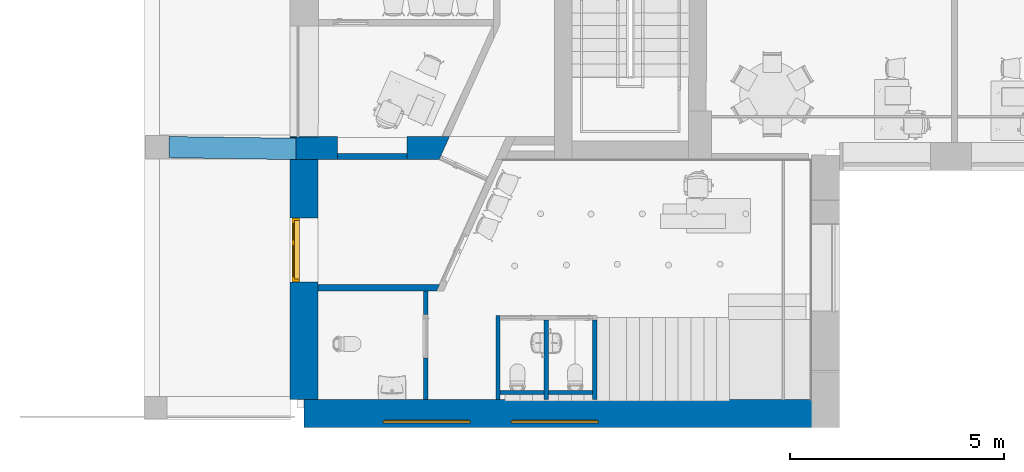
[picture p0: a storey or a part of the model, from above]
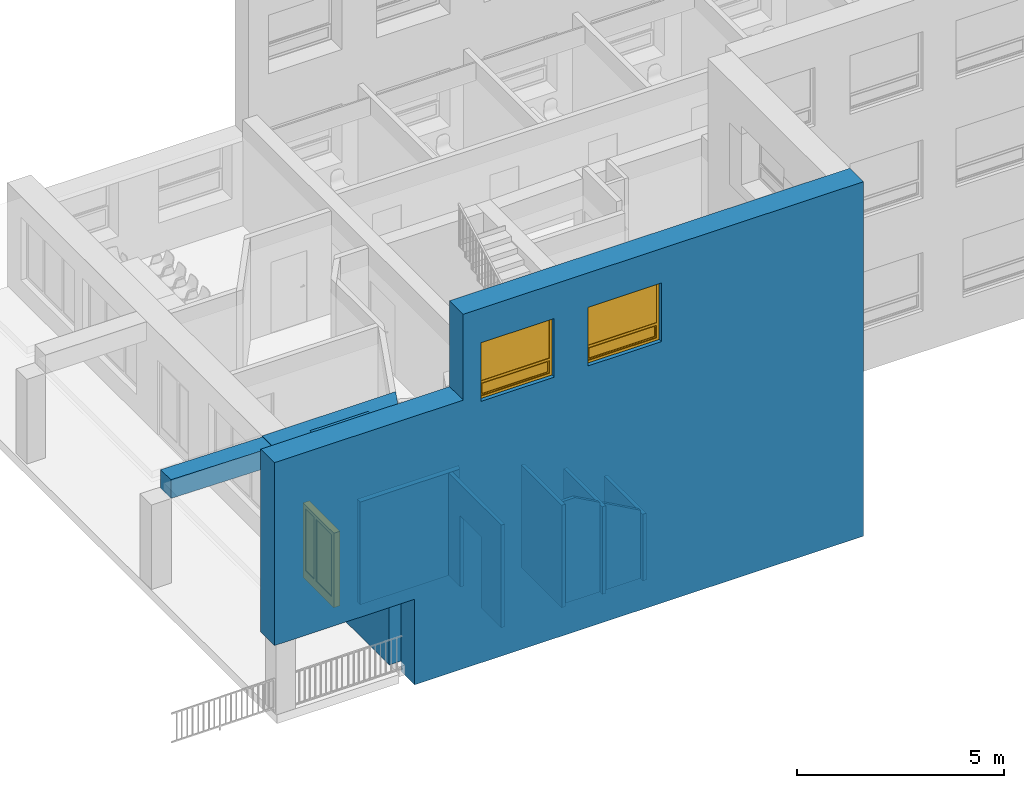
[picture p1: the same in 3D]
Properties of the parts of a building model (IFC2X3), part 1 of 3

# File
Description: ViewDefinition [CoordinationView_V2.0]
Time: 2020-02-19T11:18:32
Written by: The EXPRESS Data Manager Version 5.02.0100.07 : 28 Aug 2013
Made in: 20170223_1515(x64) - Exporter 18.0.0.420 - Alternate UI 18.0.0.420
Comment: STEP Physical File produced by: The EXPRESS Data Manager Version 5.02.0100.07 : 28 Aug 2013 * Module: EDMstepFileFactory/EDMstandAlone * Creation date: Wed Feb 19 11:18:32 2020 * Host: DESKTOP-DB93PQP * Database: C:\Users\Andres\AppData\Local\Temp\{21E9D2BA-BC34-44B0-9190-4E70AA4820ED}\ifc * Database version: 5507 * Database creation date: Wed Feb 19 11:18:06 2020 * Schema: IFC2X3 * Model: DataRepository.ifc * Model creation date: Wed Feb 19 11:18:07 2020 * Header model: DataRepository.ifc_HeaderModel * Header model creation date: Wed Feb 19 11:18:07 2020 * EDMuser: sdai-user * EDMgroup: sdai-group * License ID and type: 5605 : Permanent license. Expiry date: * EDMstepFileFactory options: 020000

# IfcSite, Surface:5336751
RefLatitude: 59, 26, 11, 44921; RefLongitude: 24, 45, 9, 146118; RefElevation: -1800 mm

# IfcBuilding
Pset_BuildingCommon - NumberOfStoreys: 8

# IfcBuildingStorey (8)
Name | LongName | Elevation (mm)
Kelder | Kelder | -1490
1 korrus | 1 korrus | 1800
2 korrus | 2 korrus | 5125
3 korrus | 3 korrus | 8315
Saali lagi | Saali lagi | 8815
Katus 3 | Katus 3 | 9115
Katus | Katus | 11960
Katus 2 | Katus 2 | 14000

# IfcSpace (115)
InteriorOrExteriorSpace: INTERNAL
Pset_SpaceCommon - Category: Rooms
Name | In | LongName = 01 Nimetus | Reference | CeilingCovering | WallCovering | FloorCovering | 02 Number | 03 Kategooria | 04 Ruumi pindala (m2) | 05 Ruumi kõrgus
121 | 1 korrus | KOOSOLEKURUUM | KOOSOLEKURUUM 121 | Akustiline moodulripplagi Ecophon Focus E 600x600x20 T15 karkass valge | Pesemiskindel poolmatt siseviimistlusvärv, värvitoon: Caparol Coelin 50 - hele hall | Linoleum - Forbo Marmoleum 3424 CHAGALL'S CIRCUS 2,5mm helesinine | 121 | Büroo | 27.3967 | 2600
102 | 1 korrus | KABINET | KABINET 102 | Akustiline moodulripplagi Ecophon Focus E 600x600x20 T15 karkass valge | Pesemiskindel poolmatt siseviimistlusvärv värvitoon: Caparol Curry 30 - hele hall | Linoleum - Forbo Marmoleum 2499 SAND 2,5mm helehall | 102 | Büroo | 15.9356 | 2500
103 | 1 korrus | WC | WC 103 | Vinüülkipslagi Gyptone Satinspar 600x600 T15 karkass valge | Keraamiline plaat CE.SI. I COLORI 200 x 200 mm x 6,5 mm, helehall SALGEMMA läikiv; WC tagasein, mosaiik 2.5x2.5 300 x 300 x 5,5 mm võrgul, SHETLAND Sinised toonid | Keraamiline plaat CE.SI I COLORI 200X200 MATT PERLA helehall. Vuugi laius 3 mm. Vuugisegu hall MIRA 121 või analoog. | 103 | Abiruum | 2.84378 | 2400
104 | 1 korrus | WC | WC 104 | Vinüülkipslagi Gyptone Satinspar 600x600 T15 karkass valge | Keraamiline plaat CE.SI. I COLORI 200 x 200 mm x 6,5 mm, helehall SALGEMMA läikiv; WC tagasein, mosaiik 2.5x2.5 300 x 300 x 5,5 mm võrgul, SHETLAND Sinised toonid | Keraamiline plaat CE.SI I COLORI 200X200 MATT PERLA helehall. Vuugi laius 3 mm. Vuugisegu hall MIRA 121 või analoog. | 104 | Abiruum | 2.13432 | 2400
105 | 1 korrus | EESRUUM | EESRUUM 105 | Akustiline moodulripplagi Ecophon Focus E 600x600x20 T15 karkass valge | Pesemiskindel poolmatt siseviimistlusvärv värvitoon: Caparol Coelin 90 - helesinine | Linoleum - Forbo Marmoleum 3219 SPA 2,5mm helesinine | 105 | Abiruum | 5.14885 | 2500
106 | 1 korrus | KABINET | KABINET 106 | Akustiline moodulripplagi Ecophon Focus E 600x600x20 T15 karkass valge | Pesemiskindel poolmatt siseviimistlusvärv värvitoon: Caparol Curry 30 - hele hall | Linoleum - Forbo Marmoleum 2499 SAND 2,5mm helehall | 106 | Büroo | 9.25155 | 2500
107 | 1 korrus | KORISTAJA | KORISTAJA 107 | Poolmatt pestav lateksvärv - toon valge | Pesemiskindel poolmatt siseviimistlusvärv värvitoon: Caparol Granit 55 - hele hall | Keraamiline plaat CE.SI I COLORI 200X200 MATT PERLA helehall. Vuugi laius 3 mm. Vuugisegu hall MIRA 121 või analoog. | 107 | Abiruum | 3.51314 | 2500
108 | 1 korrus | KABINET | KABINET 108 | Akustiline moodulripplagi Ecophon Focus E 600x600x20 T15 karkass valge | Pesemiskindel poolmatt siseviimistlusvärv värvitoon: Caparol Curry 30 - hele hall | Linoleum - Forbo Marmoleum 2499 SAND 2,5mm helehall | 108 | Büroo | 10.4447 | 2500
109 | 1 korrus | KABINET | KABINET 109 | Akustiline moodulripplagi Ecophon Focus E 600x600x20 T15 karkass valge | Pesemiskindel poolmatt siseviimistlusvärv värvitoon: Caparol Curry 30 - hele hall | Linoleum - Forbo Marmoleum 2499 SAND 2,5mm helehall | 109 | Büroo | 16.3038 | 2500
110 | 1 korrus | KORIDOR | KORIDOR 110 | Akustiline moodulripplagi Ecophon Focus E 600x600x20 T15 karkass valge | Pesemiskindel poolmatt siseviimistlusvärv värvitoon: Caparol Coelin 90 - helesinine | Linoleum - Forbo Marmoleum 3219 SPA 2,5mm helesinine | 110 | Abiruum | 51.6014 | 2500
111 | 1 korrus | KABINET | KABINET 111 | Akustiline moodulripplagi Ecophon Focus E 600x600x20 T15 karkass valge | Pesemiskindel poolmatt siseviimistlusvärv värvitoon: Caparol Curry 30 - hele hall | Linoleum - Forbo Marmoleum 2499 SAND 2,5mm helehall | 111 | Büroo | 10.3762 | 2500
112 | 1 korrus | KABINET | KABINET 112 | Akustiline moodulripplagi Ecophon Focus E 600x600x20 T15 karkass valge | Pesemiskindel poolmatt siseviimistlusvärv värvitoon: Caparol Curry 30 - hele hall | Linoleum - Forbo Marmoleum 2499 SAND 2,5mm helehall | 112 | Büroo | 16.3831 | 2500
113 | 1 korrus | KABINET | KABINET 113 | Akustiline moodulripplagi Ecophon Focus E 600x600x20 T15 karkass valge | Pesemiskindel poolmatt siseviimistlusvärv värvitoon: Caparol Curry 30 - hele hall | Linoleum - Forbo Marmoleum 2499 SAND 2,5mm helehall | 113 | Büroo | 10.0195 | 2500
114 | 1 korrus | KABINET | KABINET 114 | Akustiline moodulripplagi Ecophon Focus E 600x600x20 T15 karkass valge | Pesemiskindel poolmatt siseviimistlusvärv värvitoon: Caparol Curry 30 - hele hall | Linoleum - Forbo Marmoleum 2499 SAND 2,5mm helehall | 114 | Büroo | 16.0859 | 2500
115 | 1 korrus | KABINET | KABINET 115 | Akustiline moodulripplagi Ecophon Focus E 600x600x20 T15 karkass valge | Pesemiskindel poolmatt siseviimistlusvärv värvitoon: Caparol Curry 30 - hele hall | Linoleum - Forbo Marmoleum 2499 SAND 2,5mm helehall | 115 | Büroo | 10.4483 | 2500
116 | 1 korrus | KABINET | KABINET 116 | Akustiline moodulripplagi Ecophon Focus E 600x600x20 T15 karkass valge | Pesemiskindel poolmatt siseviimistlusvärv värvitoon: Caparol Curry 30 - hele hall | Linoleum - Forbo Marmoleum 2499 SAND 2,5mm helehall | 116 | Büroo | 28.0264 | 2500
117 | 1 korrus | KABINET | KABINET 117 | Akustiline moodulripplagi Ecophon Focus E 600x600x20 T15 karkass valge | Pesemiskindel poolmatt siseviimistlusvärv värvitoon: Caparol Curry 30 - hele hall | Linoleum - Forbo Marmoleum 2499 SAND 2,5mm helehall | 117 | Büroo | 10.4122 | 2500
118 | 1 korrus | KABINET | KABINET 118 | Akustiline moodulripplagi Ecophon Focus E 600x600x20 T15 karkass valge | Pesemiskindel poolmatt siseviimistlusvärv värvitoon: Caparol Curry 30 - hele hall | Linoleum - Forbo Marmoleum 2499 SAND 2,5mm helehall | 118 | Büroo | 10.088 | 2500
119 | 1 korrus | KABINET | KABINET 119 | Akustiline moodulripplagi Ecophon Focus E 600x600x20 T15 karkass valge | Pesemiskindel poolmatt siseviimistlusvärv värvitoon: Caparol Curry 30 - hele hall | Linoleum - Forbo Marmoleum 2499 SAND 2,5mm helehall | 119 | Büroo | 10.1385 | 2500
120 | 1 korrus | KABINET | KABINET 120 | Akustiline moodulripplagi Ecophon Focus E 600x600x20 T15 karkass valge | Pesemiskindel poolmatt siseviimistlusvärv värvitoon: Caparol Curry 30 - hele hall | Linoleum - Forbo Marmoleum 2499 SAND 2,5mm helehall | 120 | Büroo | 9.63311 | 2500
122 | 1 korrus | OOTERUUM | OOTERUUM 122 | Akustiline moodulripplagi Ecophon Focus E 600x600x20 T15 karkass valge | Pesemiskindel poolmatt siseviimistlusvärv värvitoon: Caparol Coelin 90 - helesinine | Osaliselt - Täismass plaat Mirage GloCal Perfect GC 02 NAT 300x300 helehall. Vuugi laius 3 mm. Vuugisegu hall MIRA 121 või analoog Osaliselt - Harjasmatt Silver Brush 17mm süvistatud | 122 | Abiruum | 17.1304 | 2500
123 | 1 korrus | KORIDOR | KORIDOR 123 | Akustiline moodulripplagi Ecophon Focus E 600x600x20 T15 karkass valge | Pesemiskindel poolmatt siseviimistlusvärv värvitoon: Caparol Coelin 90 - helesinine | Täismass plaat Mirage GloCal Perfect GC 02 NAT 600x300 hall. Vuugi laius 3 mm. Vuugisegu helehall MIRA 121 või analoog. | 123 | Abiruum | 9.21743 | 2500
124 | 1 korrus | TUULEKODA | TUULEKODA 124 | Akustiline moodulripplagi Ecophon Focus E 600x600x20 T15 karkass valge | Pesemiskindel poolmatt siseviimistlusvärv värvitoon: Caparol Coelin 90 - helesinine | Osaliselt - Täismass plaat Mirage GloCal Perfect GC 02 NAT 300x300 helehall. Vuugi laius 3 mm. Vuugisegu hall MIRA 121 või analoog Osaliselt - Harjasmatt Silver Brush 17mm süvistatud | 124 | Abiruum | 9.91318 | 2500
125 | 1 korrus | WC | WC 125 | Vinüülkipslagi Gyptone Satinspar 600x600 T15 karkass valge | Keraamiline plaat CE.SI. I COLORI 200 x 200 mm x 6,5 mm, helehall SALGEMMA läikiv; WC tagasein, mosaiik 2.5x2.5 300 x 300 x 5,5 mm võrgul, SHETLAND Sinised toonid | Keraamiline plaat CE.SI I COLORI 200X200 MATT PERLA helehall. Vuugi laius 3 mm. Vuugisegu hall MIRA 121 või analoog. | 125 | Abiruum | 1.70724 | 2400
126 | 1 korrus | WC | WC 126 | Vinüülkipslagi Gyptone Satinspar 600x600 T15 karkass valge | Keraamiline plaat CE.SI. I COLORI 200 x 200 mm x 6,5 mm, helehall SALGEMMA läikiv; WC tagasein, mosaiik 2.5x2.5 300 x 300 x 5,5 mm võrgul, SHETLAND Sinised toonid | Keraamiline plaat CE.SI I COLORI 200X200 MATT PERLA helehall. Vuugi laius 3 mm. Vuugisegu hall MIRA 121 või analoog. | 126 | Abiruum | 1.70724 | 2400
127 | 1 korrus | KORIDOR | KORIDOR 127 | Akustiline moodulripplagi Ecophon Focus E 600x600x20 T15 karkass valge | Pesemiskindel poolmatt siseviimistlusvärv värvitoon: Caparol Curry 30 - hele hall | Täismass plaat Mirage GloCal Perfect GC 02 NAT 600x300 hall. Vuugi laius 3 mm. Vuugisegu helehall MIRA 121 või analoog. | 127 | Abiruum | 42.2552 | 2500
128 | 1 korrus | INVA WC | INVA WC 128 | Vinüülkipslagi Gyptone Satinspar 600x600 T15 karkass valge | Keraamiline plaat CE.SI. I COLORI 200 x 200 mm x 6,5 mm, helehall SALGEMMA läikiv; WC tagasein, mosaiik 2.5x2.5 300 x 300 x 5,5 mm võrgul, SHETLAND Sinised toonid | Keraamiline plaat CE.SI I COLORI 200X200 MATT PERLA helehall. Vuugi laius 3 mm. Vuugisegu hall MIRA 121 või analoog. | 128 | Abiruum | 6.27659 | 2400
129 | 1 korrus | TREPIKODA | TREPIKODA 129 | Poolmatt pestav lateksvärv - toon valge | Pesemiskindel poolmatt siseviimistlusvärv värvitoon: Caparol Curry 30 - hele hall | Täismass plaat Mirage GloCal Perfect GC 02 NAT 600x300 hall. Trepiastmetel kasutada astmeplaati GRADINO G 300X600. Vuugi laius 3 mm. Vuugisegu helehall MIRA 121 või analoog. | 129 | Abiruum | 13.7087 | 3300
101 | 1 korrus | TREPIKODA | TREPIKODA 101 | Poolmatt pestav lateksvärv - toon valge | Pesemiskindel poolmatt siseviimistlusvärv värvitoon: Caparol Granit 55 - hele hall | Jääb olemasolev | 101 | Abiruum | 16.1449 | 3300
130 | 1 korrus | EESRUUM | EESRUUM 130 | Akustiline moodulripplagi Ecophon Focus E 600x600x20 T15 karkass valge | Pesemiskindel poolmatt siseviimistlusvärv värvitoon: Caparol Coelin 90 - helesinine | Linoleum - Forbo Marmoleum 3219 SPA 2,5mm helesinine | 130 | Abiruum | 9.22994 | 2500
131 | 1 korrus | LIFT | LIFT 131 | Stainless steal Lugano Matt Finish, Spot lightining | Lucerne Brushed | Rubber speckled Anthracite | 131 | Abiruum | 3.55834 | 3300
132 | 1 korrus | KABINET | KABINET 132 | Akustiline moodulripplagi Ecophon Focus E 600x600x20 T15 karkass valge | Pesemiskindel poolmatt siseviimistlusvärv värvitoon: Caparol Curry 30 - hele hall | Linoleum - Forbo Marmoleum 2499 SAND 2,5mm helehall | 132 | Büroo | 15.5216 | 2500
133 | 1 korrus | VARJUALUNE | VARJUALUNE 133 |  |  |  | 133 |  | 62.0822
201 | 2 korrus | TREPIKODA | TREPIKODA 201 | Poolmatt pestav lateksvärv - toon valge | Pesemiskindel poolmatt siseviimistlusvärv värvitoon: Caparol Granit 55 - hele hall | Jääb olemasolev | 201 | Abiruum | 16.857 | 3300
202 | 2 korrus | KABINET | KABINET 202 | Akustiline moodulripplagi Ecophon Focus E 600x600x20 T15 karkass valge | Pesemiskindel poolmatt siseviimistlusvärv värvitoon: Caparol Curry 30 - hele hall | Linoleum - Forbo Marmoleum 3881 GREEN WELLNESS 2,5mm heleroheline | 202 | Büroo | 14.9514 | 2500
203 | 2 korrus | WC | WC 203 | Vinüülkipslagi Gyptone Satinspar 600x600 T15 karkass valge | Plaaditud, CE.SI. I COLORI 200 x 200 mm x 6,5 mm, helehall SALGEMMA läikiv; WC tagasein, mosaiik 2.5x2.5 300 x 300 x 5,5 mm võrgul, FAROER Helesinised toonid | Keraamiline plaat CE.SI I COLORI 200X200 MATT PERLA helehall. Vuugi laius 3 mm. Vuugisegu hall MIRA 121 või analoog. | 203 | Abiruum | 2.85941 | 2400
204 | 2 korrus | WC | WC 204 | Vinüülkipslagi Gyptone Satinspar 600x600 T15 karkass valge | Plaaditud, CE.SI. I COLORI 200 x 200 mm x 6,5 mm, helehall SALGEMMA läikiv; WC tagasein, mosaiik 2.5x2.5 300 x 300 x 5,5 mm võrgul, FAROER Helesinised toonid | Keraamiline plaat CE.SI I COLORI 200X200 MATT PERLA helehall. Vuugi laius 3 mm. Vuugisegu hall MIRA 121 või analoog. | 204 | Abiruum | 2.48936 | 2400
205 | 2 korrus | PESURUUM | PESURUUM 205 | Vinüülkipslagi Gyptone Satinspar 600x600 T15 karkass valge | Keraamiline plaat, CE.SI. I COLORI 200 x 200 mm x 6,5 mm, helehall SALGEMMA läikiv. Vuugi laius 3 mm. Vuugisegu hall MIRA 112 või analoog. | Keraamiline plaat Ce.Si I Colori 200x200 antislip Onno helehalll. Vuugi laius 3 mm. Vuugisegu hall MIRA 121 või analoog. | 205 | Abiruum | 2.55895 | 2400
206 | 2 korrus | KABINET | KABINET 206 | Akustiline moodulripplagi Ecophon Focus E 600x600x20 T15 karkass valge | Pesemiskindel poolmatt siseviimistlusvärv värvitoon: Caparol Curry 30 - hele hall | Linoleum - Forbo Marmoleum 3881 GREEN WELLNESS 2,5mm heleroheline | 206 | Büroo | 8.7395 | 2500
207 | 2 korrus | KABINET | KABINET 207 | Akustiline moodulripplagi Ecophon Focus E 600x600x20 T15 karkass valge | Pesemiskindel poolmatt siseviimistlusvärv värvitoon: Caparol Curry 30 - hele hall | Linoleum - Forbo Marmoleum 3881 GREEN WELLNESS 2,5mm heleroheline | 207 | Büroo | 19.0907 | 2500
208 | 2 korrus | KABINET | KABINET 208 | Akustiline moodulripplagi Ecophon Focus E 600x600x20 T15 karkass valge | Pesemiskindel poolmatt siseviimistlusvärv värvitoon: Caparol Curry 30 - hele hall | Linoleum - Forbo Marmoleum 3881 GREEN WELLNESS 2,5mm heleroheline | 208 | Büroo | 12.2472 | 2500
209 | 2 korrus | KABINET | KABINET 209 | Akustiline moodulripplagi Ecophon Focus E 600x600x20 T15 karkass valge | Pesemiskindel poolmatt siseviimistlusvärv värvitoon: Caparol Curry 30 - hele hall | Linoleum - Forbo Marmoleum 3881 GREEN WELLNESS 2,5mm heleroheline | 209 | Büroo | 30.9839 | 2500
210 | 2 korrus | KABINET | KABINET 210 | Akustiline moodulripplagi Ecophon Focus E 600x600x20 T15 karkass valge | Pesemiskindel poolmatt siseviimistlusvärv, värvitoon: Caparol Onyx 235 - heleoranž | Linoleum - Forbo Marmoleum 3881 GREEN WELLNESS 2,5mm heleroheline | 210 | Büroo | 8.67233 | 2500
211 | 2 korrus | KORIDOR | KORIDOR 211 | Akustiline moodulripplagi Ecophon Focus E 600x600x20 T15 karkass valge | Pesemiskindel poolmatt siseviimistlusvärv värvitoon: Caparol Curry 30 - hele hall | Linoleum - Forbo Marmoleum 3120 ASIAN TIGER 2,5mm oranžikirju | 211 | Abiruum | 76.1199 | 2500
212 | 2 korrus | KABINET | KABINET 212 | Akustiline moodulripplagi Ecophon Focus E 600x600x20 T15 karkass valge | Pesemiskindel poolmatt siseviimistlusvärv värvitoon: Caparol Curry 30 - hele hall | Linoleum - Forbo Marmoleum 3881 GREEN WELLNESS 2,5mm heleroheline | 212 | Büroo | 12.2525 | 2500
213 | 2 korrus | KABINET | KABINET 213 | Akustiline moodulripplagi Ecophon Focus E 600x600x20 T15 karkass valge | Pesemiskindel poolmatt siseviimistlusvärv värvitoon: Caparol Curry 30 - hele hall | Linoleum - Forbo Marmoleum 3881 GREEN WELLNESS 2,5mm heleroheline | 213 | Büroo | 13.6208 | 2500
214 | 2 korrus | KABINET | KABINET 214 | Akustiline moodulripplagi Ecophon Focus E 600x600x20 T15 karkass valge | Pesemiskindel poolmatt siseviimistlusvärv värvitoon: Caparol Curry 30 - hele hall | Linoleum - Forbo Marmoleum 3881 GREEN WELLNESS 2,5mm heleroheline | 214 | Büroo | 8.51741 | 2500
215 | 2 korrus | KABINET | KABINET 215 | Akustiline moodulripplagi Ecophon Focus E 600x600x20 T15 karkass valge | Pesemiskindel poolmatt siseviimistlusvärv värvitoon: Caparol Curry 30 - hele hall | Linoleum - Forbo Marmoleum 3881 GREEN WELLNESS 2,5mm heleroheline | 215 | Büroo | 18.1581 | 2500
216 | 2 korrus | KABINET | KABINET 216 | Akustiline moodulripplagi Ecophon Focus E 600x600x20 T15 karkass valge | Pesemiskindel poolmatt siseviimistlusvärv värvitoon: Caparol Curry 30 - hele hall | Linoleum - Forbo Marmoleum 3881 GREEN WELLNESS 2,5mm heleroheline | 216 | Büroo | 12.4762 | 2500
217 | 2 korrus | KABINET | KABINET 217 | Akustiline moodulripplagi Ecophon Focus E 600x600x20 T15 karkass valge | Pesemiskindel poolmatt siseviimistlusvärv värvitoon: Caparol Curry 30 - hele hall | Linoleum - Forbo Marmoleum 3881 GREEN WELLNESS 2,5mm heleroheline | 217 | Büroo | 9.39956 | 2500
218 | 2 korrus | KABINET | KABINET 218 | Akustiline moodulripplagi Ecophon Focus E 600x600x20 T15 karkass valge | Pesemiskindel poolmatt siseviimistlusvärv värvitoon: Caparol Curry 30 - hele hall | Linoleum - Forbo Marmoleum 3881 GREEN WELLNESS 2,5mm heleroheline | 218 | Büroo | 10.2245 | 2500
220 | 2 korrus | TREPIKODA | TREPIKODA 220 | Poolmatt pestav lateksvärv - toon valge | Pesemiskindel poolmatt siseviimistlusvärv värvitoon: Caparol Curry 30 - hele hall | Täismass plaat Mirage GloCal Perfect GC 02 NAT 600x300 hall. Trepiastmetel kasutada astmeplaati GRADINO G 300X600. Vuugi laius 3 mm. Vuugisegu helehall MIRA 121 või analoog. | 220 | Abiruum | 13.8479 | 3300
221 | 2 korrus | SAAL | SAAL 221 | Akustiline moodulripplagi Ecophon Focus E 600x600x20 T15 karkass valge | Pesemiskindel poolmatt siseviimistlusvärv, värvitoon: Caparol Coelin 50 - hele hall | Linoleum - Forbo Marmoleum 3424 CHAGALL'S CIRCUS 2,5mm helesinine | 221 | Büroo | 52.0077 | 3000
222 | 2 korrus | KORIDOR | KORIDOR 222 | Akustiline moodulripplagi Ecophon Focus E 600x600x20 T15 karkass valge | Pesemiskindel poolmatt siseviimistlusvärv, värvitoon: Caparol Onyx 235 - heleoranž | Linoleum - Forbo Marmoleum 3120 ASIAN TIGER 2,5mm oranžikirju | 222 | Abiruum | 46.6454 | 2500
223 | 2 korrus | KABINET | KABINET 223 | Akustiline moodulripplagi Ecophon Focus E 600x600x20 T15 karkass valge | Pesemiskindel poolmatt siseviimistlusvärv värvitoon: Caparol Curry 30 - hele hall | Linoleum - Forbo Marmoleum 3881 GREEN WELLNESS 2,5mm heleroheline | 223 | Büroo | 10.2749 | 2500
224 | 2 korrus | KOOSOLEKURUUM | KOOSOLEKURUUM 224 | Akustiline moodulripplagi Ecophon Focus E 600x600x20 T15 karkass valge | Pesemiskindel poolmatt siseviimistlusvärv, värvitoon: Caparol Coelin 50 - hele hall | Linoleum - Forbo Marmoleum 3424 CHAGALL'S CIRCUS 2,5mm helesinine | 224 | Büroo | 28.8901 | 2600
225 | 2 korrus | KÖÖK | KÖÖK 225 | Akustiline moodulripplagi Ecophon Focus E 600x600x20 T15 karkass valge | Pesemiskindel poolmatt siseviimistlusvärv, värvitoon: Caparol Coelin 50 - hele hall | Linoleum - Forbo Marmoleum 3424 CHAGALL'S CIRCUS 2,5mm helesinine | 225 | Abiruum | 30.3508 | 3000
226 | 2 korrus | KABINET | KABINET 226 | Akustiline moodulripplagi Ecophon Focus E 600x600x20 T15 karkass valge | Pesemiskindel poolmatt siseviimistlusvärv värvitoon: Caparol Curry 30 - hele hall | Linoleum - Forbo Marmoleum 3881 GREEN WELLNESS 2,5mm heleroheline | 226 | Büroo | 11.8837 | 2500
227 | 2 korrus | EESRUUM | EESRUUM 227 | Akustiline moodulripplagi Ecophon Focus E 600x600x20 T15 karkass valge | Pesemiskindel poolmatt siseviimistlusvärv, värvitoon: Caparol Onyx 235 - heleoranž | Linoleum - Forbo Marmoleum 3120 ASIAN TIGER 2,5mm oranžikirju | 227 | Abiruum | 3.68256 | 2500
228 | 2 korrus | LIFT | LIFT 228 | Stainless steal Lugano Matt Finish, Spot lightining | Lucerne Brushed | Rubber speckled Anthracite | 228 |  | 3.21463 | 3300
301 | 3 korrus | TREPIKODA | TREPIKODA 301 | Poolmatt pestav lateksvärv - toon valge | Pesemiskindel poolmatt siseviimistlusvärv värvitoon: Caparol Granit 55 - hele hall | Jääb olemasolev | 301 | Abiruum | 17.6939 | 3300
302 | 3 korrus | KABINET | KABINET 302 | Akustiline moodulripplagi Ecophon Focus E 600x600x20 T15 karkass valge | Pesemiskindel poolmatt siseviimistlusvärv värvitoon: Caparol Curry 30 - hele hall | Linoleum - Forbo Marmoleum 3413 GREEN MELODY 2,5mm rohelisekirju | 302 | Büroo | 13.4872 | 2500
303 | 3 korrus | WC | WC 303 | Vinüülkipslagi Gyptone Satinspar 600x600 T15 karkass valge | Keraamiline plaat, CE.SI. I COLORI 200 x 200 mm x 6,5 mm, helehall SALGEMMA läikiv; WC tagasein, mosaiik 2.5x2.5 300 x 300 x 5,5 mm võrgul, FALKLAND Helerohelised toonid | Keraamiline plaat CE.SI I COLORI 200X200 MATT PERLA helehall. Vuugi laius 3 mm. Vuugisegu hall MIRA 121 või analoog. | 303 | Abiruum | 3.53134 | 2400
304 | 3 korrus | WC | WC 304 | Vinüülkipslagi Gyptone Satinspar 600x600 T15 karkass valge | Keraamiline plaat, CE.SI. I COLORI 200 x 200 mm x 6,5 mm, helehall SALGEMMA läikiv; WC tagasein, mosaiik 2.5x2.5 300 x 300 x 5,5 mm võrgul, FALKLAND Helerohelised toonid | Keraamiline plaat CE.SI I COLORI 200X200 MATT PERLA helehall. Vuugi laius 3 mm. Vuugisegu hall MIRA 121 või analoog. | 304 | Abiruum | 2.49685 | 2400
305 | 3 korrus | SERVER | SERVER 305 | Poolmatt pestav lateksvärv - toon valge | Pesemiskindel poolmatt siseviimistlusvärv värvitoon: Caparol Curry 30 - hele hall | Antistaatiline kate PVC Upofloor Estrad ESD 47064 roheline | 305 | Tehniline ruum | 4.17183 | 3000
306 | 3 korrus | KABINET | KABINET 306 | Akustiline moodulripplagi Ecophon Focus E 600x600x20 T15 karkass valge | Pesemiskindel poolmatt siseviimistlusvärv värvitoon: Caparol Curry 30 - hele hall | Linoleum - Forbo Marmoleum 3413 GREEN MELODY 2,5mm rohelisekirju | 306 | Büroo | 9.72057 | 2500
307 | 3 korrus | KABINET | KABINET 307 | Akustiline moodulripplagi Ecophon Focus E 600x600x20 T15 karkass valge | Pesemiskindel poolmatt siseviimistlusvärv värvitoon: Caparol Curry 30 - hele hall | Linoleum - Forbo Marmoleum 3413 GREEN MELODY 2,5mm rohelisekirju | 307 | Büroo | 15.807 | 2500
308 | 3 korrus | KABINET | KABINET 308 | Akustiline moodulripplagi Ecophon Focus E 600x600x20 T15 karkass valge | Pesemiskindel poolmatt siseviimistlusvärv värvitoon: Caparol Curry 30 - hele hall | Linoleum - Forbo Marmoleum 3413 GREEN MELODY 2,5mm rohelisekirju | 308 | Büroo | 9.83531 | 2500
311 | 3 korrus | KABINET | KABINET 311 | Akustiline moodulripplagi Ecophon Focus E 600x600x20 T15 karkass valge | Pesemiskindel poolmatt siseviimistlusvärv värvitoon: Caparol Curry 30 - hele hall | Linoleum - Forbo Marmoleum 3413 GREEN MELODY 2,5mm rohelisekirju | 311 | Büroo | 13.0631 | 2500
312 | 3 korrus | KABINET | KABINET 312 | Akustiline moodulripplagi Ecophon Focus E 600x600x20 T15 karkass valge | Pesemiskindel poolmatt siseviimistlusvärv värvitoon: Caparol Curry 30 - hele hall | Linoleum - Forbo Marmoleum 3413 GREEN MELODY 2,5mm rohelisekirju | 312 | Büroo | 16.2423 | 2500
313 | 3 korrus | KABINET | KABINET 313 | Akustiline moodulripplagi Ecophon Focus E 600x600x20 T15 karkass valge | Pesemiskindel poolmatt siseviimistlusvärv värvitoon: Caparol Curry 30 - hele hall | Linoleum - Forbo Marmoleum 3413 GREEN MELODY 2,5mm rohelisekirju | 313 | Büroo | 8.65819 | 2500
314 | 3 korrus | KABINET | KABINET 314 | Akustiline moodulripplagi Ecophon Focus E 600x600x20 T15 karkass valge | Pesemiskindel poolmatt siseviimistlusvärv värvitoon: Caparol Curry 30 - hele hall | Linoleum - Forbo Marmoleum 3413 GREEN MELODY 2,5mm rohelisekirju | 314 | Büroo | 13.139 | 2500
315 | 3 korrus | KABINET | KABINET 315 | Akustiline moodulripplagi Ecophon Focus E 600x600x20 T15 karkass valge | Pesemiskindel poolmatt siseviimistlusvärv värvitoon: Caparol Curry 30 - hele hall | Linoleum - Forbo Marmoleum 3413 GREEN MELODY 2,5mm rohelisekirju | 315 | Büroo | 8.6595 | 2500
316 | 3 korrus | KABINET | KABINET 316 | Akustiline moodulripplagi Ecophon Focus E 600x600x20 T15 karkass valge | Pesemiskindel poolmatt siseviimistlusvärv värvitoon: Caparol Curry 30 - hele hall | Linoleum - Forbo Marmoleum 3413 GREEN MELODY 2,5mm rohelisekirju | 316 | Büroo | 11.9991 | 2500
317 | 3 korrus | KABINET | KABINET 317 | Akustiline moodulripplagi Ecophon Focus E 600x600x20 T15 karkass valge | Pesemiskindel poolmatt siseviimistlusvärv värvitoon: Caparol Curry 30 - hele hall | Linoleum - Forbo Marmoleum 3413 GREEN MELODY 2,5mm rohelisekirju | 317 | Büroo | 15.2359 | 2500
318 | 3 korrus | TREPIKODA | TREPIKODA 318 | Poolmatt pestav lateksvärv - toon valge | Pesemiskindel poolmatt siseviimistlusvärv värvitoon: Caparol Curry 30 - hele hall | Täismass plaat Mirage GloCal Perfect GC 02 NAT 600x300 hall. Trepiastmetel kasutada astmeplaati GRADINO G 300X600. Vuugi laius 3 mm. Vuugisegu helehall MIRA 121 või analoog. | 318 | Abiruum | 13.3701 | 3300
319 | 3 korrus | KOHVIRUUM | KOHVIRUUM 319 | Akustiline moodulripplagi Ecophon Focus E 600x600x20 T15 karkass valge | Pesemiskindel poolmatt siseviimistlusvärv värvitoon: Caparol Curry 30 - hele hall | Linoleum - Forbo Marmoleum 3413 GREEN MELODY 2,5mm rohelisekirju | 319 | Abiruum | 22.1718 | 2600
320 | 3 korrus | KOOSOLEKURUUM | KOOSOLEKURUUM 320 | Akustiline moodulripplagi Ecophon Focus E 600x600x20 T15 karkass valge | Pesemiskindel poolmatt siseviimistlusvärv värvitoon: Caparol Curry 30 - hele hall | Linoleum - Forbo Marmoleum 3413 GREEN MELODY 2,5mm rohelisekirju | 320 | Büroo | 31.4117 | 2600
321 | 3 korrus | KABINET | KABINET 321 | Akustiline moodulripplagi Ecophon Focus E 600x600x20 T15 karkass valge | Pesemiskindel poolmatt siseviimistlusvärv värvitoon: Caparol Curry 30 - hele hall | Linoleum - Forbo Marmoleum 3413 GREEN MELODY 2,5mm rohelisekirju | 321 | Büroo | 15.7154 | 2500
322 | 3 korrus | KABINET | KABINET 322 | Akustiline moodulripplagi Ecophon Focus E 600x600x20 T15 karkass valge | Pesemiskindel poolmatt siseviimistlusvärv värvitoon: Caparol Curry 30 - hele hall | Linoleum - Forbo Marmoleum 3413 GREEN MELODY 2,5mm rohelisekirju | 322 | Büroo | 15.695 | 2500
323 | 3 korrus | EESRUUM | EESRUUM 323 | Akustiline moodulripplagi Ecophon Focus E 600x600x20 T15 karkass valge | Pesemiskindel poolmatt siseviimistlusvärv, värvitoon: Caparol Ginster 110 - helekollane | Linoleum - Forbo Marmoleum 3411 SUNNY DAY 2,5mm kollasekirju | 323 | Abiruum | 3.663 | 2500
324 | 3 korrus | LIFT | LIFT 324 | Stainless steal Lugano Matt Finish, Spot lightining | Lucerne Brushed | Rubber speckled Anthracite | 324 | Abiruum | 3.21463 | 3300
309 | 3 korrus | KABINET | KABINET 309 | Akustiline moodulripplagi Ecophon Focus E 600x600x20 T15 karkass valge | Pesemiskindel poolmatt siseviimistlusvärv värvitoon: Caparol Curry 30 - hele hall | Linoleum - Forbo Marmoleum 3413 GREEN MELODY 2,5mm rohelisekirju | 309 | Büroo | 16.2118 | 2500
325 | 3 korrus | PÖÖNING | PÖÖNING 325 | Poolmatt pestav lateksvärv - toon valge | Pesemiskindel poolmatt siseviimistlusvärv värvitoon: Caparol Granit 55 - hele hall | Tolmuvaba betoon + pinnakõvendi | 325 | Abiruum | 26.4649 | 2600
001 | Kelder | TREPIKODA | TREPIKODA 001 | Poolmatt pestav lateksvärv - toon valge | Pesemiskindel poolmatt siseviimistlusvärv värvitoon: Caparol Granit 55 - hele hall | Jääb olemasolev | 001 | Abiruum | 12.8142 | 3300
002 | Kelder | LADU | LADU 002 | Poolmatt pestav lateksvärv - toon valge | Pesemiskindel poolmatt siseviimistlusvärv värvitoon: Caparol Granit 55 - hele hall | Tolmuvaba betoon + pinnakõvendi | 002 | Abiruum | 22.364 | 2900
003 | Kelder | KORISTAJA | KORISTAJA 003 | Poolmatt pestav lateksvärv - toon valge | Pesemiskindel poolmatt siseviimistlusvärv värvitoon: Caparol Granit 55 - hele hall | Keraamiline plaat CE.SI I COLORI 200X200 MATT PERLA helehall. Vuugi laius 3 mm. Vuugisegu hall MIRA 121 või analoog. | 003 | Abiruum | 6.34179 | 2900
004 | Kelder | EESRUUM | EESRUUM 004 | Poolmatt pestav lateksvärv - toon valge | Pesemiskindel poolmatt siseviimistlusvärv värvitoon: Caparol Granit 55 - hele hall | Täismass plaat Mirage GloCal Classic GC 05 NAT 300x300 tumehall. Vuugi laius 3 mm. Vuugisegu hall MIRA 123 või analoog | 004 | Abiruum | 3.92672 | 2900
005 | Kelder | GARAAŽ | GARAAŽ 005 | Poolmatt pestav lateksvärv - toon valge | Pesemiskindel poolmatt siseviimistlusvärv värvitoon: Caparol Granit 55 - hele hall | Tolmuvaba betoon + pinnakõvendi | 005 | Abiruum | 87.115 | 2900
006 | Kelder | GARAAŽ | GARAAŽ 006 | Poolmatt pestav lateksvärv - toon valge | Pesemiskindel poolmatt siseviimistlusvärv värvitoon: Caparol Granit 55 - hele hall | Tolmuvaba betoon + pinnakõvendi | 006 | Abiruum | 79.2197 | 2900
007 | Kelder | ELEKTRIKILP | ELEKTRIKILP 007 | Poolmatt pestav lateksvärv - toon valge | Pesemiskindel poolmatt siseviimistlusvärv värvitoon: Caparol Granit 55 - hele hall | Tolmuvaba betoon + pinnakõvendi | 007 | Tehniline ruum | 3.61702 | 2900
008 | Kelder | NÕRKVOOL | NÕRKVOOL 008 | Poolmatt pestav lateksvärv - toon valge | Pesemiskindel poolmatt siseviimistlusvärv värvitoon: Caparol Granit 55 - hele hall | Tolmuvaba betoon + pinnakõvendi | 008 | Tehniline ruum | 3.9547 | 2900
009 | Kelder | PESURUUM | PESURUUM 009 | Vinüülkipslagi Gyptone Satinspar 600x600 T15 karkass valge | Keraamiline plaat, CE.SI. I COLORI 200 x 200 mm x 6,5 mm, helehall SALGEMMA läikiv. Vuugi laius 3 mm. Vuugisegu hall MIRA 112 või analoog. | Keraamiline plaat Ce.Si I Colori 200x200 antislip Onno helehalll. Vuugi laius 3 mm. Vuugisegu hall MIRA 121 või analoog. | 009 | Abiruum | 3.03917 | 2900
010 | Kelder | ABIRUUM | ABIRUUM 010 | Poolmatt pestav lateksvärv - toon valge | Pesemiskindel poolmatt siseviimistlusvärv värvitoon: Caparol Granit 55 - hele hall | Antistaatiline kate PVC Upofloor Estrad ESD 47064 roheline | 010 | Abiruum | 3.80988 | 2900
011 | Kelder | EESRUUM | EESRUUM 011 | Poolmatt pestav lateksvärv - toon valge | Pesemiskindel poolmatt siseviimistlusvärv värvitoon: Caparol Granit 55 - hele hall | Antistaatiline kate PVC Upofloor Estrad ESD 47064 roheline | 011 | Abiruum | 4.68155 | 2900
012 | Kelder | WC | WC 012 | Vinüülkipslagi Gyptone Satinspar 600x600 T15 karkass valge | Keraamiline plaat, CE.SI. I COLORI 200 x 200 mm x 6,5 mm, helehall SALGEMMA läikiv. Vuugi laius 3 mm. Vuugisegu hall MIRA 112 või analoog. | Keraamiline plaat CE.SI I COLORI 200X200 MATT PERLA helehall. Vuugi laius 3 mm. Vuugisegu hall MIRA 121 või analoog. | 012 | Abiruum | 1.98973 | 2400
013 | Kelder | TREPIKODA | TREPIKODA 013 | Poolmatt pestav lateksvärv - toon valge | Pesemiskindel poolmatt siseviimistlusvärv värvitoon: Caparol Curry 30 - hele hall | Täismass plaat Mirage GloCal Perfect GC 02 NAT 600x300 hall. Trepiastmetel kasutada astmeplaati GRADINO G 300X600 Vuugi laius 3 mm. Vuugisegu helehall MIRA 121 või analoog. | 013 | Abiruum | 15.4067 | 3300
014 | Kelder | KORIDOR | KORIDOR 014 | Akustiline moodulripplagi Ecophon Focus E 600x600x20 T15 karkass valge | Pesemiskindel poolmatt siseviimistlusvärv värvitoon: Caparol Granit 55 - hele hall | Täismass plaat Mirage GloCal Perfect GC 02 NAT 600x300 hall. Vuugi laius 3 mm. Vuugisegu helehall MIRA 121 või analoog. | 014 | Abiruum | 10.0462 | 2900
015 | Kelder | LADU | LADU 015 | Poolmatt pestav lateksvärv - toon valge | Pesemiskindel poolmatt siseviimistlusvärv värvitoon: Caparol Granit 55 - hele hall | Antistaatiline kate PVC Upofloor Estrad ESD 47064 roheline | 015 | Abiruum | 6.26584 | 2900
016 | Kelder | ARHIIV | ARHIIV 016 | Poolmatt pestav lateksvärv - toon valge | Pesemiskindel poolmatt siseviimistlusvärv värvitoon: Caparol Granit 55 - hele hall | Antistaatiline kate PVC Upofloor Estrad ESD 47064 roheline | 016 | Abiruum | 8.4526 | 2900
017 | Kelder | PUHKERUUM | PUHKERUUM 017 | Akustiline moodulripplagi Ecophon Focus E 600x600x20 T15 karkass valge | Pesemiskindel poolmatt siseviimistlusvärv värvitoon: Caparol Granit 55 - hele hall | Antistaatiline kate PVC Upofloor Estrad ESD 47064 roheline | 017 | Abiruum | 16.7952 | 2500
020 | Kelder | GARAAŽ | GARAAŽ 020 | Poolmatt pestav lateksvärv - toon valge | Pesemiskindel poolmatt siseviimistlusvärv värvitoon: Caparol Granit 55 - hele hall | Tolmuvaba betoon + pinnakõvendi | 020 | Abiruum | 63.9531 | 2900
021 | Kelder | LADU | LADU 021 | Poolmatt pestav lateksvärv - toon valge | Pesemiskindel poolmatt siseviimistlusvärv värvitoon: Caparol Granit 55 - hele hall | Tolmuvaba betoon + pinnakõvendi | 021 | Abiruum | 27.0433 | 2900
022 | Kelder | EESRUUM | EESRUUM 022 | Vinüülkipslagi Gyptone Satinspar 600x600 T15 karkass valge | Pesemiskindel poolmatt siseviimistlusvärv värvitoon: Caparol Granit 55 - hele hall | Osaliselt - Täismass plaat Mirage GloCal Classic GC 05 NAT 300x300 tumehall. Vuugi laius 3 mm. Vuugisegu hall MIRA 123 või analoog Osaliselt - Harjasmatt Silver Brush 17mm süvistatud | 022 | Abiruum | 3.84935 | 2400
023 | Kelder | LIFT | LIFT 023 | Stainless steal Lugano Matt Finish, Spot lightining | Lucerne Brushed | Rubber speckled Anthracite | 023 | Abiruum | 3.42531 | 3300
024 | Kelder | EESRUUM | EESRUUM 024 | Poolmatt pestav lateksvärv - toon valge | Pesemiskindel poolmatt siseviimistlusvärv värvitoon: Caparol Granit 55 - hele hall | Tolmuvaba betoon + pinnakõvendi | 024 | Abiruum | 3.02912 | 2900
025 | Kelder | JAHUTUSE RUUM | JAHUTUSE RUUM 025 | Poolmatt pestav lateksvärv - toon valge | Pesemiskindel poolmatt siseviimistlusvärv värvitoon: Caparol Granit 55 - hele hall | Tolmuvaba betoon + pinnakõvendi | 025 | Tehniline ruum | 3.90322 | 2900
019 | Kelder | SOOJASÕLM | SOOJASÕLM 019 | Poolmatt pestav lateksvärv - toon valge | Pesemiskindel poolmatt siseviimistlusvärv värvitoon: Caparol Granit 55 - hele hall | Tolmuvaba betoon + pinnakõvendi | 019 | Tehniline ruum | 13.004 | 2900
026 | Kelder | VENTILATSIOONIRUUM | VENTILATSIOONIRUUM 026 | Poolmatt pestav lateksvärv - toon valge | Pesemiskindel poolmatt siseviimistlusvärv värvitoon: Caparol Granit 55 - hele hall | Tolmuvaba betoon + pinnakõvendi | 026 | Tehniline ruum | 7.30595 | 2900
018 | Kelder | JÕUSAAL | JÕUSAAL 018 | Akustiline moodulripplagi Ecophon Focus E 600x600x20 T15 karkass valge | Pesemiskindel poolmatt siseviimistlusvärv värvitoon: Caparol Granit 55 - hele hall | Antistaatiline kate PVC Upofloor Estrad ESD 47064 roheline | 018 | Abiruum | 27.9172
018 | Kelder | JÕUSAAL | JÕUSAAL 018 | Akustiline moodulripplagi Ecophon Focus E 600x600x20 T15 karkass valge | Pesemiskindel poolmatt siseviimistlusvärv värvitoon: Caparol Granit 55 - hele hall | Antistaatiline kate PVC Upofloor Estrad ESD 47064 roheline | 018 | Abiruum | 10.0721
018 | Kelder | JÕUSAAL | JÕUSAAL 018 | Akustiline moodulripplagi Ecophon Focus E 600x600x20 T15 karkass valge | Pesemiskindel poolmatt siseviimistlusvärv värvitoon: Caparol Granit 55 - hele hall | Antistaatiline kate PVC Upofloor Estrad ESD 47064 roheline | 018 | Abiruum | 2.41939
310 | 3 korrus | KORIDOR | KORIDOR 310 | Akustiline moodulripplagi Ecophon Focus E 600x600x20 T15 karkass valge | Pesemiskindel poolmatt siseviimistlusvärv, värvitoon: Caparol Ginster 110 - helekollane | Linoleum - Forbo Marmoleum 3411 SUNNY DAY 2,5mm kollasekirju | 310 | Abiruum | 64.714
401 | Katus 3 | VENTILATSIOONIRUUM | VENTILATSIOONIRUUM 401 | Poolmatt pestav lateksvärv - toon valge | Pesemiskindel poolmatt siseviimistlusvärv värvitoon: Caparol Granit 55 - hele hall | Tolmuvaba betoon + pinnakõvendi | 401 | Abiruum | 92.8242
402 | Katus 3 | ÕHUVÕTURUUM | ÕHUVÕTURUUM 402 |  |  |  | 402 |  | 12.4294

# IfcBuildingElementProxy: Default (69)
Type - Material: 829cfb70_be20_4581_b42e_32c71af93796, 7ca0c13d_ce7b_4c37_8589_5645d207e611, b13fd3e2_9592_4012_855b_3a5f8c0977f9
Pset_BuildingElementProxyCommon - Reference: Default
Name (hag_tribute_9021:Default:...) | In | Group
5790902 | 302 | Model Group:Tookoht:5794390
5794472 | 307 | Model Group:Tookoht:5794474
5794535 | 302 | Model Group:Tookoht:5794537
5794660 | 307 | Model Group:Tookoht:5794662
5794718 | 309 | Model Group:Tookoht:5794720
5794768 | 309 | Model Group:Tookoht:5794770
5795206 | 312 | Model Group:Tookoht:5795208
5795210 | 312 | Model Group:Tookoht:5795212
5796124 | 322 | Model Group:Tookoht:5796126
5796189 | 322 | Model Group:Tookoht:5796191
5796258 | 321 | Model Group:Tookoht:5796260
5796307 | 321 | Model Group:Tookoht:5796309
5796707 | 306 | Model Group:Tookoht:5796709
5796770 | 308 | Model Group:Tookoht:5796772
5796822 | 311 | Model Group:Tookoht:5796824
5796874 | 311 | Model Group:Tookoht:5796876
5796992 | 313 | Model Group:Tookoht:5796994
5797046 | 314 | Model Group:Tookoht:5797048
5797050 | 314 | Model Group:Tookoht:5797052
5797100 | 315 | Model Group:Tookoht:5797102
5797151 | 316 | Model Group:Tookoht:5797153
5797155 | 316 | Model Group:Tookoht:5797157
5797212 | 317 | Model Group:Tookoht:5797214
5797309 | 317 | Model Group:Tookoht:5797311
6143709 | 102 | Model Group:Tookoht:6143710
6143715 | 102 | Model Group:Tookoht:6143716
6143718 | 109 | Model Group:Tookoht:6143719
6143721 | 112 | Model Group:Tookoht:6143722
6143739 | 116 | Model Group:Tookoht:6143740
6143745 | 106 | Model Group:Tookoht:6143746
6143748 | 108 | Model Group:Tookoht:6143749
6143751 | 111 | Model Group:Tookoht:6143752
6143757 | 113 | Model Group:Tookoht:6143758
6143760 | 115 | Model Group:Tookoht:6143761
6143766 | 117 | Model Group:Tookoht:6143767
6143769 | 118 | Model Group:Tookoht:6143770
6143775 | 119 | Model Group:Tookoht:6143776
6144008 | 202 | Model Group:Tookoht:6144009
6144014 | 202 | Model Group:Tookoht:6144015
6144026 | 209 | Model Group:Tookoht:6144027
6144029 | 209 | Model Group:Tookoht:6144030
6144035 | 213 | Model Group:Tookoht:6144036
6144038 | 215 | Model Group:Tookoht:6144039
6144044 | 206 | Model Group:Tookoht:6144045
6144047 | 210 | Model Group:Tookoht:6144048
6144050 | 208 | Model Group:Tookoht:6144051
6144053 | 208 | Model Group:Tookoht:6144054
6144059 | 216 | Model Group:Tookoht:6144060
6144062 | 216 | Model Group:Tookoht:6144063
6144065 | 214 | Model Group:Tookoht:6144066
6144074 | 218 | Model Group:Tookoht:6144075
6144663 | 114 | Model Group:Tookoht:6144664
6145406 | 132 | Model Group:Tookoht:6145407
6145640 | 116 | Model Group:Tookoht:6145641
6145697 | 116 | Model Group:Tookoht:6145698
6146131 | 120 | Model Group:Tookoht:6146132
6159965 | 127
6160802 | 215 | Model Group:Tookoht:6160803
6160864 | 213 | Model Group:Tookoht:6160865
6161207 | 215 | Model Group:Tookoht:6161208
6161503 | 207 | Model Group:Tookoht:6161504
6161506 | 207 | Model Group:Tookoht:6161507
6161626 | 209 | Model Group:Tookoht:6161627
6161779 | 209 | Model Group:Tookoht:6161780
6163061 | 212 | Model Group:Tookoht:6163062
6163064 | 212 | Model Group:Tookoht:6163065
6163354 | 217 | Model Group:Tookoht:6163355
6163758 | 226 | Model Group:Tookoht:6163759
6163761 | 226 | Model Group:Tookoht:6163762

# IfcBuildingElementProxy: Generic Models 1, Generic Models 1:Generic Models 1:5060365
In: Kelder
Pset_BuildingElementProxyCommon - Reference: Generic Models 1

# IfcBuildingElementProxy: Generic Models 2, Generic Models 2:Generic Models 2:5065068
In: Kelder
Pset_BuildingElementProxyCommon - Reference: Generic Models 2

# IfcBuildingElementProxy: Generic Models 3, Generic Models 3:Generic Models 3:5134194
In: 001
Pset_BuildingElementProxyCommon - Reference: Generic Models 3

# IfcBuildingElementProxy: Generic Models 4 (2)
In: 001
Pset_BuildingElementProxyCommon - Reference: Generic Models 4
Name
Generic Models 4:Generic Models 4:5137445
Generic Models 5:Generic Models 4:5137557

# IfcBuildingElementProxy: Generic Models 6, Generic Models 6:Generic Models 6:5158038
In: 220
Pset_BuildingElementProxyCommon - Reference: Generic Models 6

# IfcBuildingElementProxy: Generic Models 7 (2)
In: 013
Pset_BuildingElementProxyCommon - Reference: Generic Models 7
Name
Generic Models 7:Generic Models 7:5181193
Generic Models 8:Generic Models 7:5181278

# IfcBuildingElementProxy: Stairs1, Stairs1:Stairs1:5011987
In: Kelder
Pset_BuildingElementProxyCommon - Reference: Stairs1

# IfcBuildingElementProxy: Stairs10 (2)
In: Kelder
Pset_BuildingElementProxyCommon - Reference: Stairs10
Name
Stairs10:Stairs10:5133257
Stairs5:Stairs10:5133334

# IfcBuildingElementProxy: Stairs11, Stairs11:Stairs11:5137849
In: 101
Pset_BuildingElementProxyCommon - Reference: Stairs11

# IfcBuildingElementProxy: Stairs12 (2)
In: 101
Pset_BuildingElementProxyCommon - Reference: Stairs12
Name
Stairs12:Stairs12:5138728
Stairs8:Stairs12:5138837

# IfcBuildingElementProxy: Stairs13, Stairs13:Stairs13:5139831
In: 101
Pset_BuildingElementProxyCommon - Reference: Stairs13

# IfcBuildingElementProxy: Stairs14 (2)
In: 101
Pset_BuildingElementProxyCommon - Reference: Stairs14
Name
Stairs14:Stairs14:5140665
Stairs9:Stairs14:5140731

# IfcBuildingElementProxy: Stairs15, Stairs15:Stairs15:5141020
In: 201
Pset_BuildingElementProxyCommon - Reference: Stairs15

# IfcBuildingElementProxy: Stairs16 (2)
In: 201
Pset_BuildingElementProxyCommon - Reference: Stairs16
Name
Stairs16:Stairs16:5141555
Stairs17:Stairs16:5141586

# IfcBuildingElementProxy: Stairs18, Stairs18:Stairs18:5141838
In: 201
Pset_BuildingElementProxyCommon - Reference: Stairs18

# IfcBuildingElementProxy: Stairs19 (2)
In: 201
Pset_BuildingElementProxyCommon - Reference: Stairs19
Name
Stairs19:Stairs19:5142468
Stairs20:Stairs19:5142519

# IfcBuildingElementProxy: Stairs2, Stairs2:Stairs2:5060902
In: Kelder
Pset_BuildingElementProxyCommon - Reference: Stairs2

# IfcBuildingElementProxy: Stairs21, Stairs21:Stairs21:5146002
In: Kelder
Pset_BuildingElementProxyCommon - Reference: Stairs21

# IfcBuildingElementProxy: Stairs22, Stairs22:Stairs22:5159116
In: 013
Pset_BuildingElementProxyCommon - Reference: Stairs22

# IfcBuildingElementProxy: Stairs23, Stairs23:Stairs23:5162899
In: 220
Pset_BuildingElementProxyCommon - Reference: Stairs23

# IfcBuildingElementProxy: Stairs24, Stairs24:Stairs24:5164293
In: 013
Pset_BuildingElementProxyCommon - Reference: Stairs24

# IfcBuildingElementProxy: Stairs25, Stairs25:Stairs25:5169592
In: 127
Pset_BuildingElementProxyCommon - Reference: Stairs25

# IfcBuildingElementProxy: Stairs26 (2)
In: 127
Pset_BuildingElementProxyCommon - Reference: Stairs26
Name
Stairs26:Stairs26:5170209
Stairs27:Stairs26:5186881

# IfcBuildingElementProxy: Stairs3, Stairs3:Stairs3:5061628
In: Kelder
Pset_BuildingElementProxyCommon - Reference: Stairs3

# IfcBuildingElementProxy: Stairs4, Stairs4:Stairs4:5062771
In: Kelder
Pset_BuildingElementProxyCommon - Reference: Stairs4

# IfcBuildingElementProxy: Stairs6, Stairs6:Stairs6:5065630
In: Kelder
Pset_BuildingElementProxyCommon - Reference: Stairs6

# IfcBuildingElementProxy: Stairs7, Stairs7:Stairs7:5066274
In: Kelder
Pset_BuildingElementProxyCommon - Reference: Stairs7

# IfcColumn: Columns 1 (4)
In: 1 korrus
Type - ElementType: Columns 1; PredefinedType: COLUMN
Pset_ColumnCommon - LoadBearing: no; Reference: Columns 1; IsExternal: no
Name | 06 Maht (kubatuur) (m3)
Columns 1:Columns 1:4951457 | 0.734817
Columns 2:Columns 1:4951597 | 0.676053
Columns 3:Columns 1:4951648 | 0.764975
Columns 5:Columns 1:5071633 | 0.705528

# IfcColumn: Columns 6, Columns 6:Columns 6:5130703
In: Kelder
Type - ElementType: Columns 6; PredefinedType: COLUMN
Pset_ColumnCommon - LoadBearing: no; IsExternal: no; Reference: Columns 6
KONSTRUKTSIOON - 06 Maht (kubatuur): 2.98246 m3

# IfcCovering: Ceilings 12:Ceilings 12, Ceilings 12:Ceilings 12:5203873
In: 2 korrus
PredefinedType: CEILING
Pset_CoveringCommon - Reference: Ceilings 12
ARHITEKTUUR(SISEVIIMISTLUS, RIPPLAGI, PINNAKATED) - 05 Pindala: 0.481374 m2

# IfcCovering: Ceilings 15:Ceilings 15, Ceilings 15:Ceilings 15:5236957
In: 1 korrus
PredefinedType: CEILING
Pset_CoveringCommon - Reference: Ceilings 15
ARHITEKTUUR(SISEVIIMISTLUS, RIPPLAGI, PINNAKATED) - 05 Pindala: 0.468121 m2

# IfcCovering: Ceilings 17:Ceilings 17, Ceilings 17:Ceilings 17:5512851
In: 1 korrus
PredefinedType: CEILING
Pset_CoveringCommon - Reference: Ceilings 17
ARHITEKTUUR(SISEVIIMISTLUS, RIPPLAGI, PINNAKATED) - 05 Pindala: 1.46998 m2

# IfcCovering: Ceilings 1:Ceilings 12, Ceilings 1:Ceilings 12:5512624
In: Katus 3
PredefinedType: CEILING
Pset_CoveringCommon - Reference: Ceilings 12
ARHITEKTUUR(SISEVIIMISTLUS, RIPPLAGI, PINNAKATED) - 05 Pindala: 0.5023 m2

# IfcCovering: Ceilings 5:Ceilings 5, Ceilings 5:Ceilings 5:5183146
In: 1 korrus
PredefinedType: CEILING
Pset_CoveringCommon - Reference: Ceilings 5
ARHITEKTUUR(SISEVIIMISTLUS, RIPPLAGI, PINNAKATED) - 05 Pindala: 1.03788 m2

# IfcCovering: Ceilings 9:Ceilings 9, Ceilings 9:Ceilings 9:5191175
In: 2 korrus
PredefinedType: CEILING
Pset_CoveringCommon - Reference: Ceilings 9
ARHITEKTUUR(SISEVIIMISTLUS, RIPPLAGI, PINNAKATED) - 05 Pindala: 0.969392 m2

# IfcCovering: Compound Ceiling:600 x 600mm Vinyyl (11)
PredefinedType: CEILING; Material: Default 36 mm, Ceiling Tile 600 x 600 8 mm
Pset_CoveringCommon - Reference: 600 x 600mm Vinyyl; Finish: Ceiling Tile 600 x 600;; TotalThickness: 44 mm
Pset_ManufacturerTypeInformation - Manufacturer: Gyptone
ARHITEKTUUR(SISEVIIMISTLUS, RIPPLAGI, PINNAKATED) - 03 Kategooria/Tüüp: RL-2; 04 Paksus: 44 mm; 06 Niiskuskindlus: Max 90% suhteline õhuniiskus; 07 Karkass: T-15; 08 Tulekindlusklass: B-S1,d=; 13 Tootja: Gyptone; 14 Mudel/Toote nimetus: Satinspar
Name (Compound Ceiling:600 x 600mm Vinyyl:...) | In | 05 Pindala (m2)
5541863 | 1 korrus | 6.27659
5541988 | 1 korrus | 1.70724
5542000 | 126 | 1.03193
5543438 | 1 korrus | 9.83869
5543791 | 104 | 2.13432
5543799 | 103 | 2.84189
5548062 | 203 | 2.80485
5548070 | 204 | 2.45478
5556498 | 303 | 3.52497
5556513 | 304 | 2.49635
5558779 | 012 | 2.1182

# IfcCovering: Compound Ceiling:600x600 Focus (69)
PredefinedType: CEILING; Material: EST. Ripplagi. Moodullagi. 600 x 600 mm 35 mm
Pset_CoveringCommon - Reference: 600x600 Focus; Finish: EST. Ripplagi. Moodullagi. 600 x 600 mm;; TotalThickness: 35 mm
Pset_ManufacturerTypeInformation - Manufacturer: Ecophone
ARHITEKTUUR(SISEVIIMISTLUS, RIPPLAGI, PINNAKATED) - 01 Nimetus: Moodulripplagi; 03 Kategooria/Tüüp: RL-1; 04 Paksus: 35 mm; 06 Niiskuskindlus: Max 95% suhteline õhuniiskus; 07 Karkass: T-15; 08 Tulekindlusklass: A2-s1,d0; 13 Tootja: Ecophone; 14 Mudel/Toote nimetus: Focus E
Name (Compound Ceiling:600x600 Focus:...) | In | 05 Pindala (m2)
5539452 | 1 korrus | 27.4541
5539545 | 1 korrus | 8.54706
5539710 | 1 korrus | 8.50449
5539730 | 1 korrus | 8.77784
5539738 | 1 korrus | 8.80822
5539746 | 1 korrus | 8.44672
5539754 | 1 korrus | 8.74747
5539762 | 1 korrus | 8.80523
5539770 | 1 korrus | 7.80127
5539783 | 1 korrus | 14.1304
5539802 | 1 korrus | 14.6047
5539810 | 1 korrus | 14.3233
5539818 | 1 korrus | 13.8208
5539834 | 1 korrus | 14.591
5540613 | 1 korrus | 16.7994
5540630 | 1 korrus | 24.0879
5541447 | 1 korrus | 3.92585
5542360 | 127 | 33.5391
5543060 | 1 korrus | 8.51976
5543078 | 1 korrus | 9.06013
5543812 | 1 korrus | 4.54605
5545509 | 1 korrus | 52.6679
5546838 | 2 korrus | 8.65218
5546846 | 2 korrus | 7.94614
5546854 | 2 korrus | 10.547
5546862 | 2 korrus | 7.2004
5546870 | 2 korrus | 10.3579
5546878 | 2 korrus | 7.33136
5546886 | 2 korrus | 10.3534
5546894 | 2 korrus | 7.38365
5546902 | 2 korrus | 27.7073
5546910 | 2 korrus | 12.1923
5546920 | 2 korrus | 17.0352
5546930 | 2 korrus | 10.5436
5546993 | 2 korrus | 16.3718
5547540 | 2 korrus | 13.2995
5548091 | 2 korrus | 4.503
5548577 | 2 korrus | 3.024
5548845 | 2 korrus | 12.1314
5549146 | 224 | 28.9347
5549826 | 2 korrus | 46.4438
5550362 | 2 korrus | 57.8506
5552509 | 2 korrus | 10.1141
5552517 | 225 | 30.3825
5552529 | 221 | 54.1177
5553212 | 3 korrus | 13.7089
5553220 | 3 korrus | 10.2767
5553228 | 3 korrus | 7.36988
5553236 | 3 korrus | 11.1823
5553244 | 3 korrus | 7.36876
5553252 | 3 korrus | 11.1177
5553260 | 3 korrus | 8.37058
5553268 | 3 korrus | 8.26911
5553276 | 3 korrus | 14.5108
5553284 | 3 korrus | 14.4569
5553293 | 3 korrus | 14.1136
5553302 | 3 korrus | 11.7083
5553311 | 3 korrus | 14.0518
5553410 | 3 korrus | 31.4117
5554081 | 3 korrus | 22.1508
5554463 | 3 korrus | 15.5115
5555039 | 3 korrus | 43.517
5556257 | 3 korrus | 3.10177
5556901 | 3 korrus | 5.6784
5557231 | 018 | 29.6471
5557765 | Kelder | 11.03
5558368 | Kelder | 17.6599
5573121 | 1 korrus | 3.10177
5675611 | 3 korrus | 13.9769

# IfcCovering: Compound Ceiling:Alumiinumripplagi (3)
In: 1 korrus
PredefinedType: CEILING; Material: Aluminium, värvitud valge 10 mm
Pset_CoveringCommon - Reference: Alumiinumripplagi; Finish: Aluminium, värvitud valge;; TotalThickness: 10 mm
Pset_ManufacturerTypeInformation - Manufacturer: Profiline
ARHITEKTUUR(SISEVIIMISTLUS, RIPPLAGI, PINNAKATED) - 01 Nimetus: Metallprofiilist ripplag; 03 Kategooria/Tüüp: RL-4; 04 Paksus: 10 mm; 06 Niiskuskindlus: Jah; 07 Karkass: JK100-4; 08 Tulekindlusklass: A-1; 13 Tootja: Profiline; 14 Mudel/Toote nimetus: Profiline U 100/4
Name (Compound Ceiling:Alumiinumripplagi:...) | 05 Pindala (m2)
5694783 | 16.9077
5695327 | 16.8337
5695712 | 16.9645

# IfcDoor: 1000 x 2100mm SU-9 Tuletokke, sma_D01:1000 x 2100mm SU-9 Tuletokke:5131036
In: Kelder
Type - OperationType: SINGLE_SWING_LEFT; ParameterTakesPrecedence: no; Sizeable: no; Material: Metal - Aluminium, Metalli - teras- valge
Type - sma_D01:1000 x 2100mm SU-9 Tuletokke:5131036 - PanelOperation: SWINGING
OverallHeight: 2100 mm; OverallWidth: 1000 mm
Pset_DoorCommon - IsExternal: no; Reference: 1000 x 2100mm SU-9 Tuletokke; FireRating: EI-30
ARHITEKTUUR(AVATÄITED) - 05 Asukoha info: no; 01 Nimetus: Tuletõkkekuks; 19 Mudel/Toote nimetus: Metalluks, sileuks

# IfcDoor: 1000 x 2100mm SU-9 Tuletokke, sma_D01:1000 x 2100mm SU-9 Tuletokke:5131187
In: Kelder
Type - OperationType: SINGLE_SWING_LEFT; ParameterTakesPrecedence: no; Sizeable: no; Material: Metal - Aluminium, Metalli - teras- valge
Type - sma_D01:1000 x 2100mm SU-9 Tuletokke:5131187 - PanelOperation: SWINGING
OverallHeight: 2100 mm; OverallWidth: 1000 mm
Pset_DoorCommon - IsExternal: no; Reference: 1000 x 2100mm SU-9 Tuletokke; FireRating: EI-30
ARHITEKTUUR(AVATÄITED) - 05 Asukoha info: no; 01 Nimetus: Tuletõkkekuks; 19 Mudel/Toote nimetus: Metalluks, sileuks

# IfcDoor: 1000 x 2100mm SU-9 Tuletokke, sma_D01:1000 x 2100mm SU-9 Tuletokke:5175119
In: Kelder
Type - OperationType: SINGLE_SWING_LEFT; ParameterTakesPrecedence: no; Sizeable: no; Material: Metal - Aluminium, Metalli - teras- valge
Type - sma_D01:1000 x 2100mm SU-9 Tuletokke:5175119 - PanelOperation: SWINGING
OverallHeight: 2100 mm; OverallWidth: 1000 mm
Pset_DoorCommon - IsExternal: no; Reference: 1000 x 2100mm SU-9 Tuletokke; FireRating: EI-30
ARHITEKTUUR(AVATÄITED) - 05 Asukoha info: no; 01 Nimetus: Tuletõkkekuks; 19 Mudel/Toote nimetus: Metalluks, sileuks

# IfcDoor: 1000 x 2100mm SU-9 Tuletokke, sma_D01:1000 x 2100mm SU-9 Tuletokke:5175751
In: Kelder
Type - OperationType: SINGLE_SWING_LEFT; ParameterTakesPrecedence: no; Sizeable: no; Material: Metal - Aluminium, Metalli - teras- valge
Type - sma_D01:1000 x 2100mm SU-9 Tuletokke:5175751 - PanelOperation: SWINGING
OverallHeight: 2100 mm; OverallWidth: 1000 mm
Pset_DoorCommon - IsExternal: no; Reference: 1000 x 2100mm SU-9 Tuletokke; FireRating: EI-30
ARHITEKTUUR(AVATÄITED) - 05 Asukoha info: no; 01 Nimetus: Tuletõkkekuks; 19 Mudel/Toote nimetus: Metalluks, sileuks

# IfcDoor: 1000 x 2100mm SU-9 Tuletokke, sma_D01:1000 x 2100mm SU-9 Tuletokke:5177906
In: Kelder
Type - OperationType: SINGLE_SWING_LEFT; ParameterTakesPrecedence: no; Sizeable: no; Material: Metal - Aluminium, Metalli - teras- valge
Type - sma_D01:1000 x 2100mm SU-9 Tuletokke:5177906 - PanelOperation: SWINGING
OverallHeight: 2100 mm; OverallWidth: 1000 mm
Pset_DoorCommon - IsExternal: no; Reference: 1000 x 2100mm SU-9 Tuletokke; FireRating: EI-30
ARHITEKTUUR(AVATÄITED) - 05 Asukoha info: no; 01 Nimetus: Tuletõkkekuks; 19 Mudel/Toote nimetus: Metalluks, sileuks

# IfcDoor: 1000 x 2100mm SU-9 Tuletokke, sma_D01:1000 x 2100mm SU-9 Tuletokke:5422734
In: 1 korrus
Type - OperationType: SINGLE_SWING_RIGHT; ParameterTakesPrecedence: no; Sizeable: no; Material: Metal - Aluminium, Metalli - teras- valge
Type - sma_D01:1000 x 2100mm SU-9 Tuletokke:5422734 - PanelOperation: SWINGING
OverallHeight: 2100 mm; OverallWidth: 1000 mm
Pset_DoorCommon - IsExternal: no; Reference: 1000 x 2100mm SU-9 Tuletokke; FireRating: EI-30
ARHITEKTUUR(AVATÄITED) - 05 Asukoha info: no; 01 Nimetus: Tuletõkkekuks; 19 Mudel/Toote nimetus: Metalluks, sileuks

# IfcDoor: 1000 x 2100mm SU-9 Tuletokke, sma_D01:1000 x 2100mm SU-9 Tuletokke:5520833
In: Kelder
Type - OperationType: SINGLE_SWING_RIGHT; ParameterTakesPrecedence: no; Sizeable: no; Material: Metal - Aluminium, Metalli - teras- valge
Type - sma_D01:1000 x 2100mm SU-9 Tuletokke:5520833 - PanelOperation: SWINGING
OverallHeight: 2100 mm; OverallWidth: 1000 mm
Pset_DoorCommon - IsExternal: no; Reference: 1000 x 2100mm SU-9 Tuletokke; FireRating: EI-30
ARHITEKTUUR(AVATÄITED) - 05 Asukoha info: no; 01 Nimetus: Tuletõkkekuks; 19 Mudel/Toote nimetus: Metalluks, sileuks

# IfcDoor: 1000 x 2100mm SU-9 Tuletokke, sma_D01:1000 x 2100mm SU-9 Tuletokke:5645348
In: Saali lagi
Type - OperationType: SINGLE_SWING_RIGHT; ParameterTakesPrecedence: no; Sizeable: no; Material: Metal - Aluminium, Metalli - teras- valge
Type - sma_D01:1000 x 2100mm SU-9 Tuletokke:5645348 - PanelOperation: SWINGING
OverallHeight: 2100 mm; OverallWidth: 1000 mm
Pset_DoorCommon - IsExternal: no; Reference: 1000 x 2100mm SU-9 Tuletokke; FireRating: EI-30
ARHITEKTUUR(AVATÄITED) - 05 Asukoha info: no; 01 Nimetus: Tuletõkkekuks; 19 Mudel/Toote nimetus: Metalluks, sileuks

# IfcDoor: 1000 x 2100mm SU-9 Tuletokke, sma_D01:1000 x 2100mm SU-9 Tuletokke:5678858
In: Kelder
Type - OperationType: SINGLE_SWING_RIGHT; ParameterTakesPrecedence: no; Sizeable: no; Material: Metal - Aluminium, Metalli - teras- valge
Type - sma_D01:1000 x 2100mm SU-9 Tuletokke:5678858 - PanelOperation: SWINGING
OverallHeight: 2100 mm; OverallWidth: 1000 mm
Pset_DoorCommon - IsExternal: no; Reference: 1000 x 2100mm SU-9 Tuletokke; FireRating: EI-30
ARHITEKTUUR(AVATÄITED) - 05 Asukoha info: no; 01 Nimetus: Tuletõkkekuks; 19 Mudel/Toote nimetus: Metalluks, sileuks

# IfcDoor: 1000 x 2100mm Tuletokke_old, sma_D01:1000 x 2100mm Tuletokke_old:5520700
In: Kelder
Type - OperationType: SINGLE_SWING_LEFT; ParameterTakesPrecedence: no; Sizeable: no; Material: Metal - Aluminium, NCS S 2005-Y50R Vaalea beige, matta, ruisku
Type - sma_D01:1000 x 2100mm Tuletokke_old:5520700 - PanelOperation: SWINGING
OverallHeight: 2100 mm; OverallWidth: 1000 mm
Pset_DoorCommon - IsExternal: no; Reference: 1000 x 2100mm Tuletokke_old
ARHITEKTUUR(AVATÄITED) - 05 Asukoha info: no

# IfcDoor: 1010 x 2110_SU-03 Siseuks, sma_D01:1010 x 2110_SU-03 Siseuks:5175248
In: Kelder
Type - OperationType: SINGLE_SWING_LEFT; ConstructionType: USERDEFINED; ParameterTakesPrecedence: no; Sizeable: no; Material: Metal - Aluminium, Door - Panel_valge
Type - sma_D01:1010 x 2110_SU-03 Siseuks:5175248 - PanelOperation: SWINGING
OverallHeight: 2100 mm; OverallWidth: 1010 mm
Pset_DoorCommon - IsExternal: no; Reference: 1010 x 2110_SU-03 Siseuks
ARHITEKTUUR(AVATÄITED) - 05 Asukoha info: no; 01 Nimetus: Siseuks; 08 Veepidavus: -; 09 Õhuläbilaskvus: -; 11 Vastupanu tuulekoormusele: -; 14 Päikesekiirgustegur: -; 16 Liigendatus: -

# IfcDoor: 1010 x 2110_SU-03 Siseuks, sma_D01:1010 x 2110_SU-03 Siseuks:5217891
In: 3 korrus
Type - OperationType: SINGLE_SWING_LEFT; ConstructionType: USERDEFINED; ParameterTakesPrecedence: no; Sizeable: no; Material: Metal - Aluminium, Door - Panel_valge
Type - sma_D01:1010 x 2110_SU-03 Siseuks:5217891 - PanelOperation: SWINGING
OverallHeight: 2100 mm; OverallWidth: 1010 mm
Pset_DoorCommon - IsExternal: no; Reference: 1010 x 2110_SU-03 Siseuks
ARHITEKTUUR(AVATÄITED) - 05 Asukoha info: no; 01 Nimetus: Siseuks; 08 Veepidavus: -; 09 Õhuläbilaskvus: -; 11 Vastupanu tuulekoormusele: -; 14 Päikesekiirgustegur: -; 16 Liigendatus: -

# IfcDoor: 1010 x 2110_SU-03 Siseuks, sma_D01:1010 x 2110_SU-03 Siseuks:5538980
In: Kelder
Type - OperationType: SINGLE_SWING_LEFT; ConstructionType: USERDEFINED; ParameterTakesPrecedence: no; Sizeable: no; Material: Metal - Aluminium, Door - Panel_valge
Type - sma_D01:1010 x 2110_SU-03 Siseuks:5538980 - PanelOperation: SWINGING
OverallHeight: 2100 mm; OverallWidth: 1010 mm
Pset_DoorCommon - IsExternal: no; Reference: 1010 x 2110_SU-03 Siseuks
ARHITEKTUUR(AVATÄITED) - 05 Asukoha info: no; 01 Nimetus: Siseuks; 08 Veepidavus: -; 09 Õhuläbilaskvus: -; 11 Vastupanu tuulekoormusele: -; 14 Päikesekiirgustegur: -; 16 Liigendatus: -

# IfcDoor: 1010 x 2110_SU-03 Siseuks, sma_D01:1010 x 2110_SU-03 Siseuks:5423794
In: 1 korrus
Type - OperationType: SINGLE_SWING_RIGHT; ConstructionType: USERDEFINED; ParameterTakesPrecedence: no; Sizeable: no; Material: Metal - Aluminium, Door - Panel_valge
Type - sma_D01:1010 x 2110_SU-03 Siseuks:5423794 - PanelOperation: SWINGING
OverallHeight: 2100 mm; OverallWidth: 1010 mm
Pset_DoorCommon - IsExternal: no; Reference: 1010 x 2110_SU-03 Siseuks
ARHITEKTUUR(AVATÄITED) - 05 Asukoha info: no; 01 Nimetus: Siseuks; 08 Veepidavus: -; 09 Õhuläbilaskvus: -; 11 Vastupanu tuulekoormusele: -; 14 Päikesekiirgustegur: -; 16 Liigendatus: -

# IfcDoor: 1010 x 2110_SU-05 Siseuks, sma_D01:1010 x 2110_SU-05 Siseuks:5418990
In: 1 korrus
Type - OperationType: SINGLE_SWING_RIGHT; ParameterTakesPrecedence: no; Sizeable: no; Material: Metal - Aluminium, Door - Panel_valge
Type - sma_D01:1010 x 2110_SU-05 Siseuks:5418990 - PanelOperation: SWINGING
OverallHeight: 2100 mm; OverallWidth: 1010 mm
Pset_DoorCommon - IsExternal: no; Reference: 1010 x 2110_SU-05 Siseuks; FireRating: -
ARHITEKTUUR(AVATÄITED) - 05 Asukoha info: no; 01 Nimetus: Puituks siirdeõhurestiga 400 x100; 08 Veepidavus: -; 09 Õhuläbilaskvus: -; 11 Vastupanu tuulekoormusele: -; 14 Päikesekiirgustegur: -; 16 Liigendatus: -

# IfcDoor: 1010 x 2110_SU-05 Siseuks, sma_D01:1010 x 2110_SU-05 Siseuks:5424565
In: 1 korrus
Type - OperationType: SINGLE_SWING_RIGHT; ParameterTakesPrecedence: no; Sizeable: no; Material: Metal - Aluminium, Door - Panel_valge
Type - sma_D01:1010 x 2110_SU-05 Siseuks:5424565 - PanelOperation: SWINGING
OverallHeight: 2100 mm; OverallWidth: 1010 mm
Pset_DoorCommon - IsExternal: no; Reference: 1010 x 2110_SU-05 Siseuks; FireRating: -
ARHITEKTUUR(AVATÄITED) - 05 Asukoha info: no; 01 Nimetus: Puituks siirdeõhurestiga 400 x100; 08 Veepidavus: -; 09 Õhuläbilaskvus: -; 11 Vastupanu tuulekoormusele: -; 14 Päikesekiirgustegur: -; 16 Liigendatus: -

# IfcDoor: 1010 x 2110_Siseuks, sma_D01:1010 x 2110_Siseuks:5678905
In: Kelder
Type - OperationType: SINGLE_SWING_LEFT; ParameterTakesPrecedence: no; Sizeable: no; Material: Metal - Aluminium, Door - Frame, Door - Panel
Type - sma_D01:1010 x 2110_Siseuks:5678905 - PanelOperation: SWINGING
OverallHeight: 2100 mm; OverallWidth: 1000 mm
Pset_DoorCommon - IsExternal: no; Reference: 1010 x 2110_Siseuks
ARHITEKTUUR(AVATÄITED) - 05 Asukoha info: no

# IfcDoor: 1010 x 2110_Siseuks, sma_D01:1010 x 2110_Siseuks:5679099
In: Kelder
Type - OperationType: SINGLE_SWING_RIGHT; ParameterTakesPrecedence: no; Sizeable: no; Material: Metal - Aluminium, Door - Frame, Door - Panel
Type - sma_D01:1010 x 2110_Siseuks:5679099 - PanelOperation: SWINGING
OverallHeight: 2100 mm; OverallWidth: 1000 mm
Pset_DoorCommon - IsExternal: no; Reference: 1010 x 2110_Siseuks
ARHITEKTUUR(AVATÄITED) - 05 Asukoha info: no

# IfcDoor: 1200 x 2100mm SU-11 Tuletokke (6)
Type - ParameterTakesPrecedence: no; Sizeable: no; Material: Metal - Aluminium
OverallHeight: 2100 mm; OverallWidth: 1200 mm
Pset_DoorCommon - IsExternal: no; Reference: 1200 x 2100mm SU-11 Tuletokke; FireRating: EI-30
ARHITEKTUUR(AVATÄITED) - 05 Asukoha info: no; 01 Nimetus: Tuletõkkekuks liigendiga; 08 Veepidavus: -; 09 Õhuläbilaskvus: -; 11 Vastupanu tuulekoormusele: -; 14 Päikesekiirgustegur: -; 16 Liigendatus: Liigendiga siseuks; 19 Mudel/Toote nimetus: Metalluks, sileuks
Name (sma_D02:1200 x 2100mm SU-11 Tuletokke:...) | In
5504033 | 3 korrus
5505960 | 3 korrus
5522984 | 1 korrus
5524844 | 2 korrus
5525689 | 2 korrus
5734521 | 1 korrus

# IfcDoor: 1200 x 2100mm SU-7 Liigendiga siseuks (3)
In: 1 korrus
Type - ConstructionType: USERDEFINED; ParameterTakesPrecedence: no; Sizeable: no; Material: Metal - Aluminium
OverallHeight: 2100 mm; OverallWidth: 1200 mm
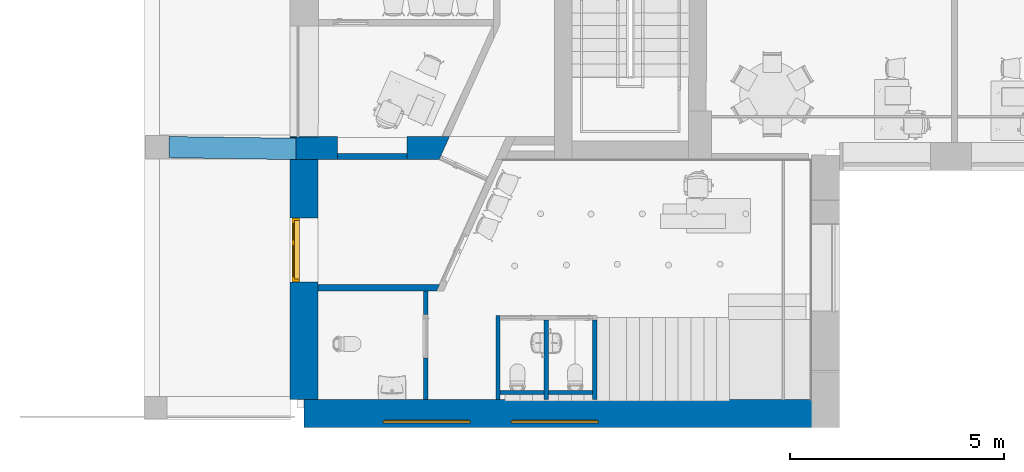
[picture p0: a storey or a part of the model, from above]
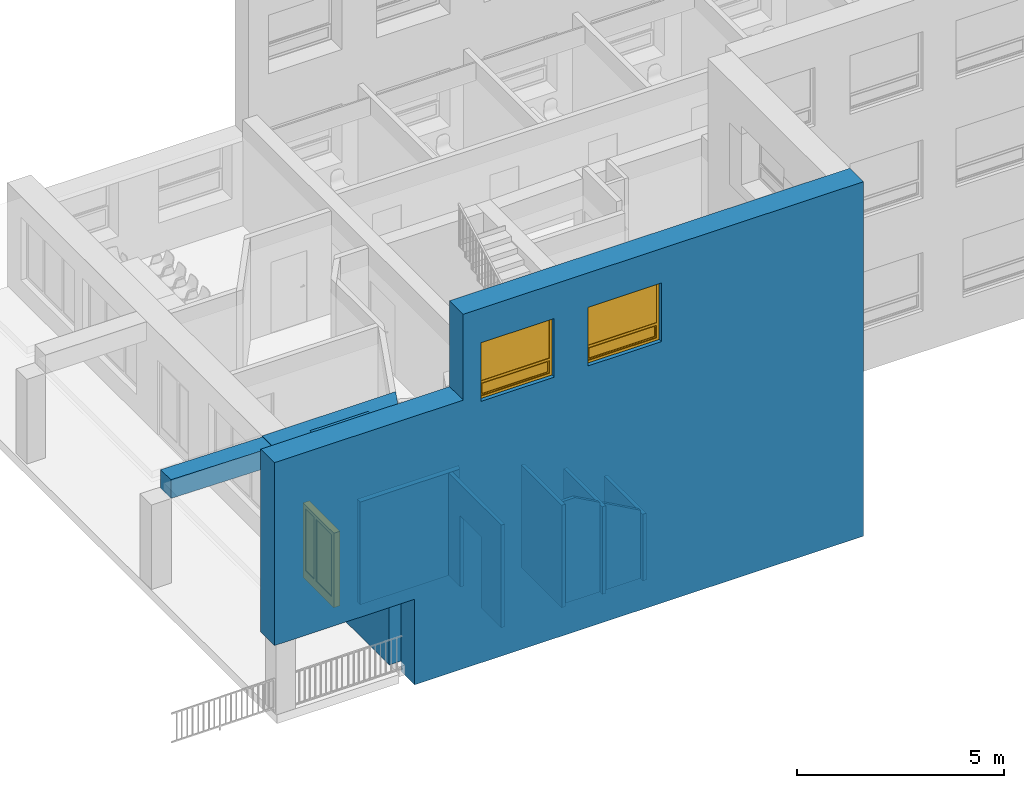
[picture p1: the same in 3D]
Properties of the parts of a building model (IFC2X3), part 2 of 3

# IfcDoor: 1200 x 2100mm SU-7 Liigendiga siseuks (3)
Pset_DoorCommon - IsExternal: no; Reference: 1200 x 2100mm SU-7 Liigendiga siseuks
ARHITEKTUUR(AVATÄITED) - 05 Asukoha info: no; 08 Veepidavus: -; 09 Õhuläbilaskvus: -; 11 Vastupanu tuulekoormusele: -; 14 Päikesekiirgustegur: -; 16 Liigendatus: Liigendiga siseuks
Name (sma_D02:1200 x 2100mm SU-7 Liigendiga siseuks:...)
5421839
5598054
5662786

# IfcDoor: 1200 x 2200mm, Concept ExtSgl:1200 x 2200mm:5030536
In: 1 korrus
Type - OperationType: SINGLE_SWING_RIGHT; ParameterTakesPrecedence: no; Sizeable: no; Material: Concept
Type - Concept ExtSgl:1200 x 2200mm:5030536 - PanelOperation: SWINGING
OverallHeight: 2200 mm; OverallWidth: 1200 mm
Pset_DoorCommon - IsExternal: yes; Reference: 1200 x 2200mm
ARHITEKTUUR(AVATÄITED) - 05 Asukoha info: yes

# IfcDoor: 1300 x 2290mm 3, sma_D01:1300 x 2290mm 3:5024698
In: Kelder
Type - OperationType: SINGLE_SWING_RIGHT; ParameterTakesPrecedence: no; Sizeable: no; Material: Metal - Aluminium
Type - sma_D01:1300 x 2290mm 3:5024698 - PanelOperation: SWINGING
OverallHeight: 2290 mm; OverallWidth: 1300 mm
Pset_DoorCommon - IsExternal: no; Reference: 1300 x 2290mm 3
ARHITEKTUUR(AVATÄITED) - 05 Asukoha info: no

# IfcDoor: 1360 x 2270mm 2, sma_D01:1360 x 2270mm 2:5024613
In: Kelder
Type - OperationType: SINGLE_SWING_LEFT; ParameterTakesPrecedence: no; Sizeable: no; Material: Metal - Aluminium
Type - sma_D01:1360 x 2270mm 2:5024613 - PanelOperation: SWINGING
OverallHeight: 2270 mm; OverallWidth: 1360 mm
Pset_DoorCommon - IsExternal: no; Reference: 1360 x 2270mm 2
ARHITEKTUUR(AVATÄITED) - 05 Asukoha info: no

# IfcDoor: 1400x2200 VU-1 Välisuks, ULO1 - ulkolasipariovi:1400x2200 VU-1 Välisuks:5497654
In: 1 korrus
Type - OperationType: DOUBLE_DOOR_SINGLE_SWING; ConstructionType: USERDEFINED; ParameterTakesPrecedence: no; Sizeable: no; Material: Metal - Paint Finish - Grey, Metal, Lasi - 1 lasilevy, kuvio, RAL Classic 9010, matta, ruisku
Type - ULO1 - ulkolasipariovi:1400x2200 VU-1 Välisuks:5497654 - PanelOperation: SWINGING
OverallHeight: 2200 mm; OverallWidth: 1490 mm
Pset_DoorCommon - IsExternal: yes; Reference: 1400x2200 VU-1 Välisuks; FireRating: -
Pset_ManufacturerTypeInformation - Manufacturer: -
ARHITEKTUUR(AVATÄITED) - 05 Asukoha info: yes; 01 Nimetus: -; 08 Veepidavus: 2A; 09 Õhuläbilaskvus: klass 1; 11 Vastupanu tuulekoormusele: C1; 14 Päikesekiirgustegur: -; 19 Mudel/Toote nimetus: -; 20 Tootja: -

# IfcDoor: 1400x2200 VU-2 Välisuks, ULO1 - ulkolasipariovi:1400x2200 VU-2 Välisuks:5497573
In: 1 korrus
Type - OperationType: DOUBLE_DOOR_SINGLE_SWING; ConstructionType: USERDEFINED; ParameterTakesPrecedence: no; Sizeable: no; Material: Metal - Paint Finish - Grey, Metal, Lasi - 1 lasilevy, kuvio, RAL Classic 9010, matta, ruisku
Type - ULO1 - ulkolasipariovi:1400x2200 VU-2 Välisuks:5497573 - PanelOperation: SWINGING
OverallHeight: 2200 mm; OverallWidth: 1490 mm
Pset_DoorCommon - IsExternal: yes; Reference: 1400x2200 VU-2 Välisuks; FireRating: -
Pset_ManufacturerTypeInformation - Manufacturer: -
ARHITEKTUUR(AVATÄITED) - 05 Asukoha info: yes; 01 Nimetus: -; 08 Veepidavus: 2A; 09 Õhuläbilaskvus: klass 1; 11 Vastupanu tuulekoormusele: C1; 14 Päikesekiirgustegur: -; 19 Mudel/Toote nimetus: -; 20 Tootja: -

# IfcDoor: 1600X2100 SU-6 Kahepoolne siseuks (2)
In: 2 korrus
Type - ParameterTakesPrecedence: no; Sizeable: no; Classification: B2030200 (Uniformat); Material: Metal - Stainless Steel, Cherry, EST. Puit. Avatäited. Värvitud. Valge
OverallHeight: 2200 mm; OverallWidth: 1700 mm
Pset_DoorCommon - IsExternal: yes; Reference: 1600X2100 SU-6 Kahepoolne siseuks
ARHITEKTUUR(AVATÄITED) - 05 Asukoha info: yes; 08 Veepidavus: -; 09 Õhuläbilaskvus: -; 11 Vastupanu tuulekoormusele: -; 14 Päikesekiirgustegur: -; 16 Liigendatus: Kahepoolne
Name (M_Door-Exterior-Double:1600X2100 SU-6 Kahepoolne siseuks:...)
5526639
5526771

# IfcDoor: 285 x 228mm (2)
In: Kelder
Type - OperationType: SINGLE_SWING_RIGHT; ParameterTakesPrecedence: no; Sizeable: no; Material: NCS S 1502-G50Y Helmenharmaa, matta, ruisku
Type - SMA_Overhead-Sectional_3000mm +käiguuks 1000.0002:285 x 228mm:5028002 - PanelOperation: SWINGING
OverallHeight: 2280 mm; OverallWidth: 2850 mm
Pset_DoorCommon - IsExternal: yes; Reference: 285 x 228mm
ARHITEKTUUR(AVATÄITED) - 05 Asukoha info: yes
Name (SMA_Overhead-Sectional_3000mm +käiguuks 1000.0002:285 x 228mm:...)
5028002
5028430

# IfcDoor: 2890 x 2470mm 2, SMA_Overhead-Sectional_3000mm +käiguuks 1000.0002:2890 x 2470mm 2:5028620
In: Kelder
Type - OperationType: SINGLE_SWING_RIGHT; ParameterTakesPrecedence: no; Sizeable: no; Material: NCS S 1502-G50Y Helmenharmaa, matta, ruisku
Type - SMA_Overhead-Sectional_3000mm +käiguuks 1000.0002:2890 x 2470mm 2:5028620 - PanelOperation: SWINGING
OverallHeight: 2470 mm; OverallWidth: 2890 mm
Pset_DoorCommon - IsExternal: yes; Reference: 2890 x 2470mm 2
ARHITEKTUUR(AVATÄITED) - 05 Asukoha info: yes

# IfcDoor: 700 x 2100mm PVC siseuks, sma_D01:700 x 2100mm PVC siseuks:5177202
In: Kelder
Type - OperationType: SINGLE_SWING_RIGHT; ConstructionType: USERDEFINED; ParameterTakesPrecedence: no; Sizeable: no; Material: Metal - Aluminium, PVC
Type - sma_D01:700 x 2100mm PVC siseuks:5177202 - PanelOperation: SWINGING
OverallHeight: 2100 mm; OverallWidth: 700 mm
Pset_DoorCommon - IsExternal: no; Reference: 700 x 2100mm PVC siseuks; FireRating: -
ARHITEKTUUR(AVATÄITED) - 05 Asukoha info: no; 01 Nimetus: PVC siseuks; 08 Veepidavus: -; 09 Õhuläbilaskvus: -; 11 Vastupanu tuulekoormusele: -; 14 Päikesekiirgustegur: -; 16 Liigendatus: -

# IfcDoor: 700 x 2100mm PVC siseuks, sma_D01:700 x 2100mm PVC siseuks:5177402
In: Kelder
Type - OperationType: SINGLE_SWING_RIGHT; ConstructionType: USERDEFINED; ParameterTakesPrecedence: no; Sizeable: no; Material: Metal - Aluminium, PVC
Type - sma_D01:700 x 2100mm PVC siseuks:5177402 - PanelOperation: SWINGING
OverallHeight: 2100 mm; OverallWidth: 700 mm
Pset_DoorCommon - IsExternal: no; Reference: 700 x 2100mm PVC siseuks; FireRating: -
ARHITEKTUUR(AVATÄITED) - 05 Asukoha info: no; 01 Nimetus: PVC siseuks; 08 Veepidavus: -; 09 Õhuläbilaskvus: -; 11 Vastupanu tuulekoormusele: -; 14 Päikesekiirgustegur: -; 16 Liigendatus: -

# IfcDoor: 700 x 2100mm SU-13 Tuletokke, sma_D01:700 x 2100mm SU-13 Tuletokke:5656155
In: 2 korrus
Type - OperationType: SINGLE_SWING_LEFT; ParameterTakesPrecedence: no; Sizeable: no; Material: Metal - Aluminium, Metalli - teras- valge
Type - sma_D01:700 x 2100mm SU-13 Tuletokke:5656155 - PanelOperation: SWINGING
OverallHeight: 2100 mm; OverallWidth: 700 mm
Pset_DoorCommon - IsExternal: no; Reference: 700 x 2100mm SU-13 Tuletokke; FireRating: EI-30
ARHITEKTUUR(AVATÄITED) - 05 Asukoha info: no; 01 Nimetus: Tuletõkkekuks; 09 Õhuläbilaskvus: -; 14 Päikesekiirgustegur: -; 16 Liigendatus: -; 19 Mudel/Toote nimetus: Metalluks, sileuks

# IfcDoor: 700 x 2100mm SU-13 Tuletokke, sma_D01:700 x 2100mm SU-13 Tuletokke:5659354
In: 3 korrus
Type - OperationType: SINGLE_SWING_LEFT; ParameterTakesPrecedence: no; Sizeable: no; Material: Metal - Aluminium, Metalli - teras- valge
Type - sma_D01:700 x 2100mm SU-13 Tuletokke:5659354 - PanelOperation: SWINGING
OverallHeight: 2100 mm; OverallWidth: 700 mm
Pset_DoorCommon - IsExternal: no; Reference: 700 x 2100mm SU-13 Tuletokke; FireRating: EI-30
ARHITEKTUUR(AVATÄITED) - 05 Asukoha info: no; 01 Nimetus: Tuletõkkekuks; 09 Õhuläbilaskvus: -; 14 Päikesekiirgustegur: -; 16 Liigendatus: -; 19 Mudel/Toote nimetus: Metalluks, sileuks

# IfcDoor: 700 x 2100mm Tuletokke, sma_D01:700 x 2100mm Tuletokke:5655986
In: 1 korrus
Type - OperationType: SINGLE_SWING_LEFT; ParameterTakesPrecedence: no; Sizeable: no; Material: Metal - Aluminium, NCS S 2005-Y50R Vaalea beige, matta, ruisku
Type - sma_D01:700 x 2100mm Tuletokke:5655986 - PanelOperation: SWINGING
OverallHeight: 2100 mm; OverallWidth: 700 mm
Pset_DoorCommon - IsExternal: no; Reference: 700 x 2100mm Tuletokke
ARHITEKTUUR(AVATÄITED) - 05 Asukoha info: no

# IfcDoor: 810 x 2110_SU-01 Siseuks (2)
In: Kelder
Type - OperationType: SINGLE_SWING_LEFT; ParameterTakesPrecedence: no; Sizeable: no; Material: Metal - Aluminium, Door - Panel_valge
Type - sma_D01:810 x 2110_SU-01 Siseuks:5176089 - PanelOperation: SWINGING
OverallHeight: 2100 mm; OverallWidth: 810 mm
Pset_DoorCommon - IsExternal: no; Reference: 810 x 2110_SU-01 Siseuks; FireRating: -
ARHITEKTUUR(AVATÄITED) - 05 Asukoha info: no; 08 Veepidavus: -; 09 Õhuläbilaskvus: -; 11 Vastupanu tuulekoormusele: -; 14 Päikesekiirgustegur: -; 16 Liigendatus: -
Name (sma_D01:810 x 2110_SU-01 Siseuks:...)
5176089
5176099

# IfcDoor: 810 x 2110_SU-01 Siseuks (27)
Type - OperationType: SINGLE_SWING_LEFT; ParameterTakesPrecedence: no; Sizeable: no; Material: Metal - Aluminium, Door - Panel_valge
Type - sma_D01:810 x 2110_SU-01 Siseuks:5419649 - PanelOperation: SWINGING
OverallHeight: 2100 mm; OverallWidth: 810 mm
Pset_DoorCommon - IsExternal: no; Reference: 810 x 2110_SU-01 Siseuks; FireRating: -
ARHITEKTUUR(AVATÄITED) - 05 Asukoha info: no; 08 Veepidavus: -; 09 Õhuläbilaskvus: -; 11 Vastupanu tuulekoormusele: -; 14 Päikesekiirgustegur: -; 16 Liigendatus: -
Name (sma_D01:810 x 2110_SU-01 Siseuks:...) | In
5419649 | 1 korrus
5419751 | 1 korrus
5420076 | 1 korrus
5420207 | 1 korrus
5420376 | 1 korrus
5420581 | 1 korrus
5420668 | 1 korrus
5420805 | 1 korrus
5501827 | 2 korrus
5501829 | 2 korrus
5501831 | 2 korrus
5501832 | 2 korrus
5501833 | 2 korrus
5501834 | 2 korrus
5501856 | 3 korrus
5501857 | 3 korrus
5501858 | 3 korrus
5501859 | 3 korrus
5501860 | 3 korrus
5501861 | 3 korrus
5501862 | 3 korrus
5505673 | 3 korrus
5525862 | 2 korrus
5525972 | 2 korrus
5659131 | 3 korrus
6162313 | 2 korrus
6162709 | 2 korrus

# IfcDoor: 810 x 2110_SU-01 Siseuks, sma_D01:810 x 2110_SU-01 Siseuks:5421560
In: 1 korrus
Type - OperationType: SINGLE_SWING_LEFT; ParameterTakesPrecedence: no; Sizeable: no; Material: Metal - Aluminium, Door - Panel_valge
Type - sma_D01:810 x 2110_SU-01 Siseuks:5421560 - PanelOperation: SWINGING
OverallHeight: 2100 mm; OverallWidth: 810 mm
Pset_DoorCommon - IsExternal: no; Reference: 810 x 2110_SU-01 Siseuks; FireRating: -
ARHITEKTUUR(AVATÄITED) - 05 Asukoha info: no; 08 Veepidavus: -; 09 Õhuläbilaskvus: -; 11 Vastupanu tuulekoormusele: -; 14 Päikesekiirgustegur: -; 16 Liigendatus: -

# IfcDoor: 810 x 2110_SU-01 Siseuks (2)
Type - OperationType: SINGLE_SWING_LEFT; ParameterTakesPrecedence: no; Sizeable: no; Material: Metal - Aluminium, Door - Panel_valge
Type - sma_D01:810 x 2110_SU-01 Siseuks:5505375 - PanelOperation: SWINGING
OverallHeight: 2100 mm; OverallWidth: 810 mm
Pset_DoorCommon - IsExternal: no; Reference: 810 x 2110_SU-01 Siseuks; FireRating: -
ARHITEKTUUR(AVATÄITED) - 05 Asukoha info: no; 08 Veepidavus: -; 09 Õhuläbilaskvus: -; 11 Vastupanu tuulekoormusele: -; 14 Päikesekiirgustegur: -; 16 Liigendatus: -
Name (sma_D01:810 x 2110_SU-01 Siseuks:...) | In
5505375 | 3 korrus
5525801 | 2 korrus

# IfcDoor: 810 x 2110_SU-01 Siseuks, sma_D01:810 x 2110_SU-01 Siseuks:5605626
In: 2 korrus
Type - OperationType: SINGLE_SWING_LEFT; ParameterTakesPrecedence: no; Sizeable: no; Material: Metal - Aluminium, Door - Panel_valge
Type - sma_D01:810 x 2110_SU-01 Siseuks:5605626 - PanelOperation: SWINGING
OverallHeight: 2100 mm; OverallWidth: 810 mm
Pset_DoorCommon - IsExternal: no; Reference: 810 x 2110_SU-01 Siseuks; FireRating: -
ARHITEKTUUR(AVATÄITED) - 05 Asukoha info: no; 08 Veepidavus: -; 09 Õhuläbilaskvus: -; 11 Vastupanu tuulekoormusele: -; 14 Päikesekiirgustegur: -; 16 Liigendatus: -

# IfcDoor: 810 x 2110_SU-01 Siseuks, sma_D01:810 x 2110_SU-01 Siseuks:5176282
In: Kelder
Type - OperationType: SINGLE_SWING_RIGHT; ParameterTakesPrecedence: no; Sizeable: no; Material: Metal - Aluminium, Door - Panel_valge
Type - sma_D01:810 x 2110_SU-01 Siseuks:5176282 - PanelOperation: SWINGING
OverallHeight: 2100 mm; OverallWidth: 810 mm
Pset_DoorCommon - IsExternal: no; Reference: 810 x 2110_SU-01 Siseuks; FireRating: -
ARHITEKTUUR(AVATÄITED) - 05 Asukoha info: no; 08 Veepidavus: -; 09 Õhuläbilaskvus: -; 11 Vastupanu tuulekoormusele: -; 14 Päikesekiirgustegur: -; 16 Liigendatus: -

# IfcDoor: 810 x 2110_SU-01 Siseuks, sma_D01:810 x 2110_SU-01 Siseuks:5176459
In: Kelder
Type - OperationType: SINGLE_SWING_RIGHT; ParameterTakesPrecedence: no; Sizeable: no; Material: Metal - Aluminium, Door - Panel_valge
Type - sma_D01:810 x 2110_SU-01 Siseuks:5176459 - PanelOperation: SWINGING
OverallHeight: 2100 mm; OverallWidth: 810 mm
Pset_DoorCommon - IsExternal: no; Reference: 810 x 2110_SU-01 Siseuks; FireRating: -
ARHITEKTUUR(AVATÄITED) - 05 Asukoha info: no; 08 Veepidavus: -; 09 Õhuläbilaskvus: -; 11 Vastupanu tuulekoormusele: -; 14 Päikesekiirgustegur: -; 16 Liigendatus: -

# IfcDoor: 810 x 2110_SU-01 Siseuks (4)
Type - OperationType: SINGLE_SWING_RIGHT; ParameterTakesPrecedence: no; Sizeable: no; Material: Metal - Aluminium, Door - Panel_valge
Type - sma_D01:810 x 2110_SU-01 Siseuks:5212508 - PanelOperation: SWINGING
OverallHeight: 2100 mm; OverallWidth: 810 mm
Pset_DoorCommon - IsExternal: no; Reference: 810 x 2110_SU-01 Siseuks; FireRating: -
ARHITEKTUUR(AVATÄITED) - 05 Asukoha info: no; 08 Veepidavus: -; 09 Õhuläbilaskvus: -; 11 Vastupanu tuulekoormusele: -; 14 Päikesekiirgustegur: -; 16 Liigendatus: -
Name (sma_D01:810 x 2110_SU-01 Siseuks:...) | In
5212508 | 3 korrus
5525805 | 2 korrus
5525809 | 2 korrus
5525812 | 2 korrus

# IfcDoor: 810 x 2110_SU-01 Siseuks (6)
Type - OperationType: SINGLE_SWING_RIGHT; ParameterTakesPrecedence: no; Sizeable: no; Material: Metal - Aluminium, Door - Panel_valge
Type - sma_D01:810 x 2110_SU-01 Siseuks:5212962 - PanelOperation: SWINGING
OverallHeight: 2100 mm; OverallWidth: 810 mm
Pset_DoorCommon - IsExternal: no; Reference: 810 x 2110_SU-01 Siseuks; FireRating: -
ARHITEKTUUR(AVATÄITED) - 05 Asukoha info: no; 08 Veepidavus: -; 09 Õhuläbilaskvus: -; 11 Vastupanu tuulekoormusele: -; 14 Päikesekiirgustegur: -; 16 Liigendatus: -
Name (sma_D01:810 x 2110_SU-01 Siseuks:...) | In
5212962 | 3 korrus
5213255 | 3 korrus
5421071 | 1 korrus
5421125 | 1 korrus
5421278 | 1 korrus
5529007 | 1 korrus

# IfcDoor: 810 x 2110_SU-01 Siseuks, sma_D01:810 x 2110_SU-01 Siseuks:5213346
In: 3 korrus
Type - OperationType: SINGLE_SWING_RIGHT; ParameterTakesPrecedence: no; Sizeable: no; Material: Metal - Aluminium, Door - Panel_valge
Type - sma_D01:810 x 2110_SU-01 Siseuks:5213346 - PanelOperation: SWINGING
OverallHeight: 2100 mm; OverallWidth: 810 mm
Pset_DoorCommon - IsExternal: no; Reference: 810 x 2110_SU-01 Siseuks; FireRating: -
ARHITEKTUUR(AVATÄITED) - 05 Asukoha info: no; 08 Veepidavus: -; 09 Õhuläbilaskvus: -; 11 Vastupanu tuulekoormusele: -; 14 Päikesekiirgustegur: -; 16 Liigendatus: -

# IfcDoor: 810 x 2110_SU-01 Siseuks (2)
In: 1 korrus
Type - OperationType: SINGLE_SWING_RIGHT; ParameterTakesPrecedence: no; Sizeable: no; Material: Metal - Aluminium, Door - Panel_valge
Type - sma_D01:810 x 2110_SU-01 Siseuks:5421597 - PanelOperation: SWINGING
OverallHeight: 2100 mm; OverallWidth: 810 mm
Pset_DoorCommon - IsExternal: no; Reference: 810 x 2110_SU-01 Siseuks; FireRating: -
ARHITEKTUUR(AVATÄITED) - 05 Asukoha info: no; 08 Veepidavus: -; 09 Õhuläbilaskvus: -; 11 Vastupanu tuulekoormusele: -; 14 Päikesekiirgustegur: -; 16 Liigendatus: -
Name (sma_D01:810 x 2110_SU-01 Siseuks:...)
5421597
5423834

# IfcDoor: 810 x 2110_SU-04 Siseuks, sma_D01:810 x 2110_SU-04 Siseuks:5176937
In: Kelder
Type - OperationType: SINGLE_SWING_LEFT; ParameterTakesPrecedence: no; Sizeable: no; Material: Metal - Aluminium, Door - Panel_valge
Type - sma_D01:810 x 2110_SU-04 Siseuks:5176937 - PanelOperation: SWINGING
OverallHeight: 2100 mm; OverallWidth: 810 mm
Pset_DoorCommon - IsExternal: no; Reference: 810 x 2110_SU-04 Siseuks; FireRating: -
ARHITEKTUUR(AVATÄITED) - 05 Asukoha info: no; 01 Nimetus: Puituks siirdeõhurestiga 400 x100; 08 Veepidavus: -; 09 Õhuläbilaskvus: -; 11 Vastupanu tuulekoormusele: -; 14 Päikesekiirgustegur: -; 16 Liigendatus: -

# IfcDoor: 810 x 2110_SU-04 Siseuks (6)
Type - OperationType: SINGLE_SWING_LEFT; ParameterTakesPrecedence: no; Sizeable: no; Material: Metal - Aluminium, Door - Panel_valge
Type - sma_D01:810 x 2110_SU-04 Siseuks:5418429 - PanelOperation: SWINGING
OverallHeight: 2100 mm; OverallWidth: 810 mm
Pset_DoorCommon - IsExternal: no; Reference: 810 x 2110_SU-04 Siseuks; FireRating: -
ARHITEKTUUR(AVATÄITED) - 05 Asukoha info: no; 01 Nimetus: Puituks siirdeõhurestiga 400 x100; 08 Veepidavus: -; 09 Õhuläbilaskvus: -; 11 Vastupanu tuulekoormusele: -; 14 Päikesekiirgustegur: -; 16 Liigendatus: -
Name (sma_D01:810 x 2110_SU-04 Siseuks:...) | In
5418429 | 1 korrus
5418777 | 1 korrus
5501825 | 2 korrus
5501826 | 2 korrus
5501854 | 3 korrus
5501855 | 3 korrus

# IfcDoor: 810 x 2110_SU-04 Siseuks (2)
In: 1 korrus
Type - OperationType: SINGLE_SWING_LEFT; ParameterTakesPrecedence: no; Sizeable: no; Material: Metal - Aluminium, Door - Panel_valge
Type - sma_D01:810 x 2110_SU-04 Siseuks:5424028 - PanelOperation: SWINGING
OverallHeight: 2100 mm; OverallWidth: 810 mm
Pset_DoorCommon - IsExternal: no; Reference: 810 x 2110_SU-04 Siseuks; FireRating: -
ARHITEKTUUR(AVATÄITED) - 05 Asukoha info: no; 01 Nimetus: Puituks siirdeõhurestiga 400 x100; 08 Veepidavus: -; 09 Õhuläbilaskvus: -; 11 Vastupanu tuulekoormusele: -; 14 Päikesekiirgustegur: -; 16 Liigendatus: -
Name (sma_D01:810 x 2110_SU-04 Siseuks:...)
5424028
5424665

# IfcDoor: 810 x 2110_SU-04 Siseuks, sma_D01:810 x 2110_SU-04 Siseuks:5525817
In: 2 korrus
Type - OperationType: SINGLE_SWING_RIGHT; ParameterTakesPrecedence: no; Sizeable: no; Material: Metal - Aluminium, Door - Panel_valge
Type - sma_D01:810 x 2110_SU-04 Siseuks:5525817 - PanelOperation: SWINGING
OverallHeight: 2100 mm; OverallWidth: 810 mm
Pset_DoorCommon - IsExternal: no; Reference: 810 x 2110_SU-04 Siseuks; FireRating: -
ARHITEKTUUR(AVATÄITED) - 05 Asukoha info: no; 01 Nimetus: Puituks siirdeõhurestiga 400 x100; 08 Veepidavus: -; 09 Õhuläbilaskvus: -; 11 Vastupanu tuulekoormusele: -; 14 Päikesekiirgustegur: -; 16 Liigendatus: -

# IfcDoor: 810 x 2110_SU-08 Tuletõkkeuks, sma_D01:810 x 2110_SU-08 Tuletõkkeuks:5644861
In: Saali lagi
Type - OperationType: SINGLE_SWING_LEFT; ParameterTakesPrecedence: no; Sizeable: no; Material: Metal - Aluminium, EST. Metall. Teras. Värvitud. RAL9010 (Valge)
Type - sma_D01:810 x 2110_SU-08 Tuletõkkeuks:5644861 - PanelOperation: SWINGING
OverallHeight: 2100 mm; OverallWidth: 910 mm
Pset_DoorCommon - IsExternal: no; Reference: 810 x 2110_SU-08 Tuletõkkeuks; FireRating: EI-30
ARHITEKTUUR(AVATÄITED) - 05 Asukoha info: no; 08 Veepidavus: -; 09 Õhuläbilaskvus: -; 11 Vastupanu tuulekoormusele: -; 14 Päikesekiirgustegur: -; 16 Liigendatus: -

# IfcDoor: 810 x 2110_SU-08 Tuletõkkeuks, sma_D01:810 x 2110_SU-08 Tuletõkkeuks:5505347
In: 3 korrus
Type - OperationType: SINGLE_SWING_RIGHT; ParameterTakesPrecedence: no; Sizeable: no; Material: Metal - Aluminium, EST. Metall. Teras. Värvitud. RAL9010 (Valge)
Type - sma_D01:810 x 2110_SU-08 Tuletõkkeuks:5505347 - PanelOperation: SWINGING
OverallHeight: 2100 mm; OverallWidth: 910 mm
Pset_DoorCommon - IsExternal: no; Reference: 810 x 2110_SU-08 Tuletõkkeuks; FireRating: EI-30
ARHITEKTUUR(AVATÄITED) - 05 Asukoha info: no; 08 Veepidavus: -; 09 Õhuläbilaskvus: -; 11 Vastupanu tuulekoormusele: -; 14 Päikesekiirgustegur: -; 16 Liigendatus: -

# IfcDoor: 900 x 2100mm Tuletokke, sma_D01:900 x 2100mm Tuletokke:5125999
In: Kelder
Type - OperationType: SINGLE_SWING_LEFT; ParameterTakesPrecedence: no; Sizeable: no; Material: Metal - Aluminium, Metalli - teras- valge
Type - sma_D01:900 x 2100mm Tuletokke:5125999 - PanelOperation: SWINGING
OverallHeight: 2100 mm; OverallWidth: 900 mm
Pset_DoorCommon - IsExternal: no; Reference: 900 x 2100mm Tuletokke; FireRating: EI-30
ARHITEKTUUR(AVATÄITED) - 05 Asukoha info: no; 01 Nimetus: Tuletõkkekuks; 19 Mudel/Toote nimetus: Metalluks, sileuks

# IfcDoor: 900 x 2100mm Tuletokke (2)
In: Kelder
Type - OperationType: SINGLE_SWING_LEFT; ParameterTakesPrecedence: no; Sizeable: no; Material: Metal - Aluminium, Metalli - teras- valge
Type - sma_D01:900 x 2100mm Tuletokke:5539298 - PanelOperation: SWINGING
OverallHeight: 2100 mm; OverallWidth: 900 mm
Pset_DoorCommon - IsExternal: no; Reference: 900 x 2100mm Tuletokke; FireRating: EI-30
ARHITEKTUUR(AVATÄITED) - 05 Asukoha info: no; 01 Nimetus: Tuletõkkekuks; 19 Mudel/Toote nimetus: Metalluks, sileuks
Name (sma_D01:900 x 2100mm Tuletokke:...)
5539298
5663521

# IfcDoor: 910 x 2110_SU-02 Siseuks, sma_D01:910 x 2110_SU-02 Siseuks:5216460
In: 3 korrus
Type - OperationType: SINGLE_SWING_LEFT; ParameterTakesPrecedence: no; Sizeable: no; Material: Metal - Aluminium, Door - Panel_valge
Type - sma_D01:910 x 2110_SU-02 Siseuks:5216460 - PanelOperation: SWINGING
OverallHeight: 2100 mm; OverallWidth: 910 mm
Pset_DoorCommon - IsExternal: no; Reference: 910 x 2110_SU-02 Siseuks
ARHITEKTUUR(AVATÄITED) - 05 Asukoha info: no; 08 Veepidavus: -; 09 Õhuläbilaskvus: -; 11 Vastupanu tuulekoormusele: -; 14 Päikesekiirgustegur: -; 16 Liigendatus: -

# IfcDoor: 910 x 2110_SU-02 Siseuks (2)
Type - OperationType: SINGLE_SWING_LEFT; ParameterTakesPrecedence: no; Sizeable: no; Material: Metal - Aluminium, Door - Panel_valge
Type - sma_D01:910 x 2110_SU-02 Siseuks:5526233 - PanelOperation: SWINGING
OverallHeight: 2100 mm; OverallWidth: 910 mm
Pset_DoorCommon - IsExternal: no; Reference: 910 x 2110_SU-02 Siseuks
ARHITEKTUUR(AVATÄITED) - 05 Asukoha info: no; 08 Veepidavus: -; 09 Õhuläbilaskvus: -; 11 Vastupanu tuulekoormusele: -; 14 Päikesekiirgustegur: -; 16 Liigendatus: -
Name (sma_D01:910 x 2110_SU-02 Siseuks:...) | In
5526233 | 2 korrus
5610694 | 3 korrus

# IfcDoor: 910 x 2110_SU-02 Siseuks, sma_D01:910 x 2110_SU-02 Siseuks:5526406
In: 2 korrus
Type - OperationType: SINGLE_SWING_RIGHT; ParameterTakesPrecedence: no; Sizeable: no; Material: Metal - Aluminium, Door - Panel_valge
Type - sma_D01:910 x 2110_SU-02 Siseuks:5526406 - PanelOperation: SWINGING
OverallHeight: 2100 mm; OverallWidth: 910 mm
Pset_DoorCommon - IsExternal: no; Reference: 910 x 2110_SU-02 Siseuks
ARHITEKTUUR(AVATÄITED) - 05 Asukoha info: no; 08 Veepidavus: -; 09 Õhuläbilaskvus: -; 11 Vastupanu tuulekoormusele: -; 14 Päikesekiirgustegur: -; 16 Liigendatus: -

# IfcDoor: Tostuks 200 x 228mm, SMA_Overhead-Sectional_3000mm +käiguuks 1000.0002:Tostuks 200 x 228mm:5521871
In: Kelder
Type - OperationType: SINGLE_SWING_RIGHT; ParameterTakesPrecedence: no; Sizeable: no; Material: NCS S 1502-G50Y Helmenharmaa, matta, ruisku
Type - SMA_Overhead-Sectional_3000mm +käiguuks 1000.0002:Tostuks 200 x 228mm:5521871 - PanelOperation: SWINGING
OverallHeight: 2280 mm; OverallWidth: 2050 mm
Pset_DoorCommon - IsExternal: yes; Reference: Tostuks 200 x 228mm
ARHITEKTUUR(AVATÄITED) - 05 Asukoha info: yes

# IfcDoor: Valisuks 1000x2100, M_Door-Exterior-Single-Two_Lite:Valisuks 1000x2100:5521471
In: Kelder
Type - ParameterTakesPrecedence: no; Sizeable: no; Classification: B2030100 (Uniformat); Material: Metal - Stainless Steel, Metal - Painted - Grey
OverallHeight: 2200 mm; OverallWidth: 1100 mm
Pset_DoorCommon - IsExternal: yes; Reference: Valisuks 1000x2100
ARHITEKTUUR(AVATÄITED) - 05 Asukoha info: yes; 01 Nimetus: Välisuks; 19 Mudel/Toote nimetus: Metalluks, sileuks

# IfcFlowTerminal: 152mm Incandescent - 120V (10)
In: 127
Type - Classification: D5020220 (Uniformat); Material: Steel, Paint Finish, Dark Gray, Matte, Glass, White, High Luminance
Pset_DistributionFlowElementCommon - Reference: 152mm Incandescent - 120V
Name (M_Downlight - Recessed Can:152mm Incandescent - 120V:...)
5771424
5771944
5772568
5772926
5773659
5773799
5774183
5774771
5775035
5776111

# IfcFlowTerminal: 455 mmx455 mm - Public (3)
Material: Aluminio, Metal - Stainless Steel,Polished
Pset_DistributionFlowElementCommon - Reference: 455 mmx455 mm - Public
Name (Sink - Island - Single:455 mmx455 mm - Public:...) | In
6143539 | 319
6168684 | 225
6186155 | 224

# IfcFlowTerminal: 470 x 320 (2)
Material: Metalli - teräs, kromattu, Posliini - valkoinen, Muovi - valkoinen
Pset_ManufacturerTypeInformation - Manufacturer: -
Pset_DistributionFlowElementCommon - Reference: 470 x 320
Name (Pesuallas Pieni:470 x 320:...) | In
5757311 | 125
5757312 | 126

# IfcFlowTerminal: 560 x 420 (6)
Material: Muovi - valkoinen, Metalli - teräs, kromattu, Posliini - valkoinen
Pset_ManufacturerTypeInformation - Manufacturer: -
Pset_DistributionFlowElementCommon - Reference: 560 x 420
Name (Pesuallas Iso:560 x 420:...) | In
5757309 | 104
5757310 | 103
5758418 | 303
5758437 | 204
5758556 | 203
5758622 | 304

# IfcFlowTerminal: D0280/01, Sanitary_Accessories_Goman_D0280-01:D0280/01:5757344
In: 128
Material: White
Pset_DistributionFlowElementCommon - Reference: D0280/01

# IfcFlowTerminal: WC-istuin seinäk (8)
Material: Posliini - valkoinen, Muovi - valkoinen
Pset_ManufacturerTypeInformation - Manufacturer: -
Pset_DistributionFlowElementCommon - Reference: WC-istuin seinäk
Name (wc-istuin_seinäkiinnitteinen:WC-istuin seinäk:...) | In
5757480 | 125
5757505 | 126
5757745 | 104
5757793 | 103
5758072 | 204
5758073 | 203
5758079 | 303
5758133 | 304

# IfcFlowTerminal: Wc-istuin, wc-istuin:Wc-istuin:5757313
In: 128
Material: Muovi - valkoinen, Posliini - valkoinen
Pset_ManufacturerTypeInformation - Manufacturer: -
Pset_DistributionFlowElementCommon - Reference: Wc-istuin

# IfcFlowTerminal: shower_head_elephant_8031 (2)
Material: Metal
Pset_DistributionFlowElementCommon - Reference: shower_head_elephant_8031
Name (shower_head_elephant_8031:shower_head_elephant_8031:...) | In
5179004 | 009
5203363 | 205

# IfcFurnishingElement: 1525mm Diameter (3)
Type - ElementType: 1525mm Diameter; Material: Pine, Laminate, Linen, Matte
Name (M_Table-Dining Round w Chairs:1525mm Diameter:...) | In
5783165 | 116
5784111 | 225
5784385 | 319

# IfcFurnishingElement: 2200x1100mm (7)
In: 221
Type - ElementType: 2200x1100mm; Material: ABS Plastic
Pset_ManufacturerTypeInformation - Manufacturer: Andersen Furniture
Name (Furniture_Table_IconsOfDenmark_byKato_Unlimited:2200x1100mm:...)
6180233
6180863
6180921
6180922
6180969
6180970
6181127

# IfcFurnishingElement: 64321 (7)
Type - ElementType: 64321; Classification: E2020200 (Uniformat); Material: Fabric - Sauder® Manufacturing Co - Sample - Linen Beige, Wood - Sauder® Manufacturing Co - Sample - Cherry - Stained
Pset_ManufacturerTypeInformation - Manufacturer: Sauder® Manufacturing Co
Name (Chair-Sauder_MFG_CO.-Rally-Indulge:64321:...) | In
6123977 | 310
6170457 | 225
6170573 | 225
6181462 | 222
6181466 | 222
6181666 | 017
6181670 | 017

# IfcFurnishingElement: Barlow Coffee Table (4)
Type - ElementType: Barlow Coffee Table; Material: Meyer Wells - Metal - Matte Black, Meyer Wells - Specialty Veneer - Gun Metal Ebony
Pset_ManufacturerTypeInformation - Manufacturer: Meyer Wells
Name (Furniture_Tables_Meyer-Wells_Barlow-Coffee-Table-Veneer:Barlow Coffee Table:...) | In
6126424 | 310
6170460 | 225
6181465 | 222
6181669 | 017

# IfcFurnishingElement: Body Colour - (Chestnut) Front Colour - (High Gloss White), Furniture_Office-Desks-Tables_MDD_RECEPTION-DESK-FORO:Body Colour - (Chestnut) Front Colour - (High Gloss White):6160154
In: 127
Type - ElementType: Body Colour - (Chestnut) Front Colour - (High Gloss White); Material: Wood-MDD-Chestnut, Plastic-MDD-High Gloss White, Other-MDD-Black, Metal-MDD-Silver

# IfcFurnishingElement: COLOUR - (Beige) (5)
Type - ElementType: COLOUR - (Beige); Material: b778a556_05a0_493c_881c_631cd100f656, cc3e65c7_b8b7_42b7_8786_03d2160d08ff, fe885133_f34e_493d_a534_8c58479e4704
Name (gap_lounge:COLOUR - (Beige):...) | In
6120918 | 310
6170456 | 225
6181461 | 222
6181603 | 222
6181733 | 017

# IfcFurnishingElement: Chair KT-2 (73)
Type - ElementType: Chair KT-2; Classification: E2020200 (Uniformat); Material: Haworth - Paint -White, Haworth - Metal - Steel
Pset_ManufacturerTypeInformation - Manufacturer: Haworth
Name (Haworth_Chair_Tate_Color_Chair:Chair KT-2:...) | In
6112880 | 302
6113058 | 302
6113135 | 307
6113203 | 307
6113298 | 309
6113372 | 309
6113450 | 312
6113483 | 312
6113719 | 322
6113800 | 322
6113869 | 321
6113955 | 321
6114076 | 306
6114161 | 308
6114171 | 313
6114181 | 315
6114189 | 317
6114295 | 311
6114296 | 311
6114333 | 314
6114334 | 314
6114410 | 317
6114620 | 316
6114621 | 316
6143927 | 102
6143929 | 102
6143933 | 112
6143940 | 106
6143941 | 108
6143942 | 113
6143943 | 117
6143944 | 119
6144226 | 202
6144228 | 202
6144233 | 209
6144236 | 213
6144239 | 206
6144240 | 210
6144242 | 214
6144243 | 218
6144244 | 208
6144245 | 208
6144246 | 216
6144247 | 216
6144505 | 109
6144666 | 114
6145409 | 132
6146235 | 116
6146279 | 120
6146372 | 122
6146412 | 122
6146422 | 122
6146432 | 122
6146446 | 127
6146510 | 127
6146520 | 127
6147127 | 111
6147167 | 115
6147177 | 118
6160977 | 213
6161291 | 215
6161292 | 215
6161330 | 215
6161516 | 207
6161517 | 207
6161629 | 209
6162046 | 209
6162169 | 209
6163068 | 212
6163069 | 212
6163357 | 217
6163648 | 226
6163649 | 226

# IfcFurnishingElement: Default (68)
Type - ElementType: Default; Material: Black 655E2F3C, White 1D9B2C88, Gray 1D965131
Name (Furniture_Shelving-Storage_PALMBERG_Containers-on-castors:Default:...) | In | Group
5800246 | 321 | Model Group:Tookoht:5796260
5801411 | 302 | Model Group:Tookoht:5794390
5801461 | 307 | Model Group:Tookoht:5794474
5801486 | 302 | Model Group:Tookoht:5794537
5801511 | 307 | Model Group:Tookoht:5794662
5801536 | 309 | Model Group:Tookoht:5794720
5801561 | 309 | Model Group:Tookoht:5794770
5801586 | 312 | Model Group:Tookoht:5795208
5801611 | 312 | Model Group:Tookoht:5795212
5801636 | 322 | Model Group:Tookoht:5796126
5801661 | 322 | Model Group:Tookoht:5796191
5801686 | 321 | Model Group:Tookoht:5796309
5801711 | 306 | Model Group:Tookoht:5796709
5801736 | 308 | Model Group:Tookoht:5796772
5801761 | 311 | Model Group:Tookoht:5796824
5801786 | 311 | Model Group:Tookoht:5796876
5801811 | 313 | Model Group:Tookoht:5796994
5801836 | 314 | Model Group:Tookoht:5797048
5801861 | 314 | Model Group:Tookoht:5797052
5801886 | 315 | Model Group:Tookoht:5797102
5801911 | 316 | Model Group:Tookoht:5797153
5801936 | 316 | Model Group:Tookoht:5797157
5801961 | 317 | Model Group:Tookoht:5797214
5801986 | 317 | Model Group:Tookoht:5797311
6143804 | 116 | Model Group:Tookoht:6143740
6143806 | 102 | Model Group:Tookoht:6143710
6143808 | 102 | Model Group:Tookoht:6143716
6143809 | 109 | Model Group:Tookoht:6143719
6143810 | 112 | Model Group:Tookoht:6143722
6143817 | 106 | Model Group:Tookoht:6143746
6143818 | 108 | Model Group:Tookoht:6143749
6143819 | 111 | Model Group:Tookoht:6143752
6143821 | 113 | Model Group:Tookoht:6143758
6143822 | 115 | Model Group:Tookoht:6143761
6143824 | 117 | Model Group:Tookoht:6143767
6143825 | 118 | Model Group:Tookoht:6143770
6143827 | 119 | Model Group:Tookoht:6143776
6144103 | 215 | Model Group:Tookoht:6144039
6144105 | 202 | Model Group:Tookoht:6144009
6144107 | 202 | Model Group:Tookoht:6144015
6144111 | 209 | Model Group:Tookoht:6144027
6144112 | 209 | Model Group:Tookoht:6144030
6144114 | 213 | Model Group:Tookoht:6144036
6144116 | 206 | Model Group:Tookoht:6144045
6144117 | 210 | Model Group:Tookoht:6144048
6144118 | 208 | Model Group:Tookoht:6144051
6144119 | 208 | Model Group:Tookoht:6144054
6144121 | 216 | Model Group:Tookoht:6144060
6144122 | 216 | Model Group:Tookoht:6144063
6144123 | 214 | Model Group:Tookoht:6144066
6144126 | 218 | Model Group:Tookoht:6144075
6144665 | 114 | Model Group:Tookoht:6144664
6145408 | 132 | Model Group:Tookoht:6145407
6145642 | 116 | Model Group:Tookoht:6145641
6145699 | 116 | Model Group:Tookoht:6145698
6146133 | 120 | Model Group:Tookoht:6146132
6160804 | 215 | Model Group:Tookoht:6160803
6160866 | 213 | Model Group:Tookoht:6160865
6161209 | 215 | Model Group:Tookoht:6161208
6161512 | 207 | Model Group:Tookoht:6161504
6161513 | 207 | Model Group:Tookoht:6161507
6161628 | 209 | Model Group:Tookoht:6161627
6161781 | 209 | Model Group:Tookoht:6161780
6163066 | 212 | Model Group:Tookoht:6163062
6163067 | 212 | Model Group:Tookoht:6163065
6163356 | 217 | Model Group:Tookoht:6163355
6163763 | 226 | Model Group:Tookoht:6163759
6163764 | 226 | Model Group:Tookoht:6163762

# IfcFurnishingElement: Default (4)
Type - ElementType: Default; Material: Laminate Oak DAA67F30, Oak 7886ABE3, Black F5380830
Name (Furniture_Office-Desks-Tables_Kinnarps_Nexus-Meeting-NEXM189-900x1800:Default:...) | In
6116260 | 320
6116570 | 320
6146632 | 121
6146633 | 121

# IfcFurnishingElement: Desk top material - (White pastel) (68)
Type - ElementType: Desk top material - (White pastel); Material: Plastic-MDD-Black, Metal-MDD-M009 Aluminium semi-matt, MFC-MDD-M067 White pastel, Plastic-MDD-White
Name (Furniture_Office-Desks-Tables_MDD_OGI-DRIVE-desk:Desk top material - (White pastel):...) | In | Group
5787357 | 302 | Model Group:Tookoht:5794390
5794471 | 307 | Model Group:Tookoht:5794474
5794534 | 302 | Model Group:Tookoht:5794537
5794659 | 307 | Model Group:Tookoht:5794662
5794717 | 309 | Model Group:Tookoht:5794720
5794767 | 309 | Model Group:Tookoht:5794770
5795205 | 312 | Model Group:Tookoht:5795208
5795209 | 312 | Model Group:Tookoht:5795212
5796123 | 322 | Model Group:Tookoht:5796126
5796188 | 322 | Model Group:Tookoht:5796191
5796257 | 321 | Model Group:Tookoht:5796260
5796306 | 321 | Model Group:Tookoht:5796309
5796706 | 306 | Model Group:Tookoht:5796709
5796769 | 308 | Model Group:Tookoht:5796772
5796821 | 311 | Model Group:Tookoht:5796824
5796873 | 311 | Model Group:Tookoht:5796876
5796991 | 313 | Model Group:Tookoht:5796994
5797045 | 314 | Model Group:Tookoht:5797048
5797049 | 314 | Model Group:Tookoht:5797052
5797099 | 315 | Model Group:Tookoht:5797102
5797150 | 316 | Model Group:Tookoht:5797153
5797154 | 316 | Model Group:Tookoht:5797157
5797211 | 317 | Model Group:Tookoht:5797214
5797308 | 317 | Model Group:Tookoht:5797311
6143708 | 102 | Model Group:Tookoht:6143710
6143714 | 102 | Model Group:Tookoht:6143716
6143717 | 109 | Model Group:Tookoht:6143719
6143720 | 112 | Model Group:Tookoht:6143722
6143738 | 116 | Model Group:Tookoht:6143740
6143744 | 106 | Model Group:Tookoht:6143746
6143747 | 108 | Model Group:Tookoht:6143749
6143750 | 111 | Model Group:Tookoht:6143752
6143756 | 113 | Model Group:Tookoht:6143758
6143759 | 115 | Model Group:Tookoht:6143761
6143765 | 117 | Model Group:Tookoht:6143767
6143768 | 118 | Model Group:Tookoht:6143770
6143774 | 119 | Model Group:Tookoht:6143776
6144007 | 202 | Model Group:Tookoht:6144009
6144013 | 202 | Model Group:Tookoht:6144015
6144025 | 209 | Model Group:Tookoht:6144027
6144028 | 209 | Model Group:Tookoht:6144030
6144034 | 213 | Model Group:Tookoht:6144036
6144037 | 215 | Model Group:Tookoht:6144039
6144043 | 206 | Model Group:Tookoht:6144045
6144046 | 210 | Model Group:Tookoht:6144048
6144049 | 208 | Model Group:Tookoht:6144051
6144052 | 208 | Model Group:Tookoht:6144054
6144058 | 216 | Model Group:Tookoht:6144060
6144061 | 216 | Model Group:Tookoht:6144063
6144064 | 214 | Model Group:Tookoht:6144066
6144073 | 218 | Model Group:Tookoht:6144075
6144662 | 114 | Model Group:Tookoht:6144664
6145405 | 132 | Model Group:Tookoht:6145407
6145639 | 116 | Model Group:Tookoht:6145641
6145696 | 116 | Model Group:Tookoht:6145698
6146130 | 120 | Model Group:Tookoht:6146132
6160801 | 215 | Model Group:Tookoht:6160803
6160863 | 213 | Model Group:Tookoht:6160865
6161206 | 215 | Model Group:Tookoht:6161208
6161502 | 207 | Model Group:Tookoht:6161504
6161505 | 207 | Model Group:Tookoht:6161507
6161625 | 209 | Model Group:Tookoht:6161627
6161778 | 209 | Model Group:Tookoht:6161780
6163060 | 212 | Model Group:Tookoht:6163062
6163063 | 212 | Model Group:Tookoht:6163065
6163353 | 217 | Model Group:Tookoht:6163355
6163757 | 226 | Model Group:Tookoht:6163759
6163760 | 226 | Model Group:Tookoht:6163762

# IfcFurnishingElement: Flädie_Conference Table_CJ9, Flädie_Conference Table_CJ9:Flädie_Conference Table_CJ9:6167763
In: 224
Type - ElementType: Flädie_Conference Table_CJ9; Material: Flädie Möbler PlyWood, Flädie Möbler Wood

# IfcFurnishingElement: Front variables - (Two drawers) (7)
Type - ElementType: Front variables - (Two drawers); Material: Black, Aluminio, Roble Denver, Blanco Medio
Name (Kitchen_Cabinets_FINSA_Pro-Base-Drawer-unit-600:Front variables - (Two drawers):...) | In
6143533 | 319
6143536 | 319
6168678 | 225
6168681 | 225
6168947 | 225
6186151 | 224
6186154 | 224

# IfcFurnishingElement: ICS armchair metal slide base (78)
Type - ElementType: ICS armchair metal slide base
Name (Furniture_Office-Chairs_Capdell_ICS-armchair-metal-slide-base:ICS armchair metal slide base:...) | In
6118588 | 320
6118914 | 320
6119118 | 320
6119149 | 320
6119180 | 320
6119211 | 320
6119293 | 320
6119294 | 320
6119295 | 320
6119296 | 320
6119297 | 320
6119298 | 320
6119378 | 320
6119486 | 320
6146634 | 121
6146635 | 121
6146636 | 121
6146637 | 121
6146638 | 121
6146639 | 121
6146640 | 121
6146641 | 121
6146642 | 121
6146643 | 121
6146644 | 121
6146645 | 121
6146646 | 121
6146647 | 121
6165714 | 224
6165715 | 224
6165716 | 224
6165717 | 224
6165718 | 224
6165720 | 224
6165721 | 224
6165722 | 224
6165723 | 224
6165724 | 224
6165726 | 224
6165727 | 224
6165905 | 224
6165938 | 224
6165971 | 224
6166004 | 224
6166039 | 224
6168426 | 224
6172177 | 221
6172178 | 221
6172179 | 221
6172180 | 221
6172181 | 221
6172182 | 221
6172281 | 221
6172282 | 221
6173182 | 221
6173183 | 221
6173184 | 221
6173185 | 221
6173186 | 221
6173187 | 221
6173385 | 221
6173386 | 221
6173387 | 221
6173388 | 221
6173389 | 221
6173390 | 221
6173434 | 221
6173435 | 221
6173436 | 221
6173437 | 221
6173438 | 221
6173439 | 221
6173505 | 221
6173506 | 221
6173507 | 221
6173508 | 221
6173509 | 221
6173510 | 221

# IfcFurnishingElement: M_Chair-Breuer (18)
Type - ElementType: M_Chair-Breuer; Material: Puu - kovapuu, Steel, Chrome Plated
Name (M_Chair-Breuer:M_Chair-Breuer:...) | In
5783166 | 116
5783167 | 116
5783168 | 116
5783169 | 116
5783919 | 116
5783920 | 116
5784112 | 225
5784113 | 225
5784114 | 225
5784115 | 225
5784116 | 225
5784117 | 225
5784386 | 319
5784387 | 319
5784388 | 319
5784389 | 319
5784390 | 319
5784391 | 319

# IfcFurnishingElement: Opening Type - (One left hinged door) Height - (700 mm) (3)
Type - ElementType: Opening Type - (One left hinged door) Height - (700 mm); Material: Blanco Medio, Brown, Roble Denver, Aluminio, Black
Name (Kitchen_Cabinets_FINSA_Pro-Base-unit-500:Opening Type - (One left hinged door) Height - (700 mm):...) | In
6143535 | 319
6168680 | 225
6186153 | 224

# IfcFurnishingElement: Opening Type - (Two hinged doors) Height - (700 mm) (2)
Type - ElementType: Opening Type - (Two hinged doors) Height - (700 mm); Material: Aluminio, Blanco Medio, Roble Denver, Black
Name (Kitchen_Cabinets_FINSA_Pro-Base-Sink-unit-700:Opening Type - (Two hinged doors) Height - (700 mm):...) | In
6168679 | 225
6186152 | 224

# IfcFurnishingElement: Opening Type - (Two hinged doors) Height - (700 mm), Kitchen_Cabinets_FINSA_Pro-Base-Sink-unit-700:Opening Type - (Two hinged doors) Height - (700 mm):6143534
In: 319
Type - ElementType: Opening Type - (Two hinged doors) Height - (700 mm); Material: Black, Blanco Medio, Roble Denver, Aluminio

# IfcFurnishingElement: Opening Type - (Two right hinged doors (up + down)) Height - (2000 mm), Kitchen_Cabinets_FINSA_Pro-Oven-Microwave-Larder-unit:Opening Type - (Two right hinged doors (up + down)) Height - (2000 mm):6143532
In: 319
Type - ElementType: Opening Type - (Two right hinged doors (up + down)) Height - (2000 mm); Material: Black, Aluminio, Black Glass, Grey Glass, Blanco Medio, Brown, Roble Denver

# IfcFurnishingElement: Opening Type - (Two right hinged doors) Height - (2000 mm) (2)
Type - ElementType: Opening Type - (Two right hinged doors) Height - (2000 mm); Material: Roble Denver, Blanco Medio, Brown, Black, Aluminio
Name (Kitchen_Cabinets_FINSA_Pro-Larder-unit-600:Opening Type - (Two right hinged doors) Height - (2000 mm):...) | In
6143531 | 319
6168676 | 225

# IfcFurnishingElement: Paksusega 20mm, Kitchen_Counter-tops_FINSA_Fintop-Kitchen-worktop:Paksusega 20mm:6171894
In: 225
Type - ElementType: Paksusega 20mm; Material: Fintop+ Kitchen worktop - Finsa-worktops-fintop-plus - Arido_Pino Arido

# IfcFurnishingElement: Thickness 20mm (3)
Type - ElementType: Thickness 20mm; Material: Fintop+ Kitchen worktop - Finsa-worktops-fintop-plus - Arido_Pino Arido
Name (Kitchen_Counter-tops_FINSA_Fintop-Kitchen-worktop:Thickness 20mm:...) | In
6143537 | 319
6168682 | 225
6185761 | 224

# IfcFurnishingElement: Wood (14)
Type - ElementType: Wood; Material: Wood - Sauder® Manufacturing Co - Sample - Cherry - Stained
Pset_ManufacturerTypeInformation - Manufacturer: Sauder® Manufacturing Co
Name (Leg-Sauder_MFG_CO.-Rally-Wood:Wood:...) | In
6123978 | 310
6123979 | 310
6170458 | 225
6170459 | 225
6170574 | 225
6170575 | 225
6181463 | 222
6181464 | 222
6181467 | 222
6181468 | 222
6181667 | Kelder
6181668 | Kelder
6181671 | Kelder
6181672 | Kelder

# IfcFurnishingElement: skirt_01 (6)
Type - ElementType: skirt_01; Material: White skirt
Name (skirt_01:skirt_01:...) | In
6143541 | 319
6143542 | 319
6168685 | 225
6168686 | 225
6185764 | 2 korrus
6185765 | 2 korrus

# IfcFurnishingElement: skirt_04 (3)
Type - ElementType: skirt_04; Material: Skirt
Name (skirt_04:skirt_04:...) | In
6143543 | 319
6168687 | 225
6185971 | 224

# IfcMember: Carriage:Carriage - 50 mm Width (10)
Type - PredefinedType: STRINGER
Pset_MemberCommon - IsExternal: no; LoadBearing: yes
Name (Assembled Stair:Stair:...) | In | Reference | Span (mm) | Slope (deg)
5508512 Stringer 1 | 1 korrus | 190mm max riser 250mm kesktrepp | 50 | 0
5508512 Stringer 2 | 1 korrus | 190mm max riser 250mm kesktrepp | 50 | 0
5508512 Stringer 3 | 1 korrus | 190mm max riser 250mm kesktrepp | 50 | 0
5508512 Stringer 4 | 1 korrus | 190mm max riser 250mm kesktrepp | 50 | 0
5508512 Stringer 5 | 1 korrus | 190mm max riser 250mm kesktrepp | 301.412 | 0
5508512 Stringer 6 | 1 korrus | 190mm max riser 250mm kesktrepp
5508512 Stringer 7 | 1 korrus | 190mm max riser 250mm kesktrepp
5508512 Stringer 8 | 1 korrus | 190mm max riser 250mm kesktrepp | 301.412 | 0
5648093 Stringer 1 | 3 korrus | 220mm max riser 220mm pooningutrepp | 50 | 0
5648093 Stringer 2 | 3 korrus | 220mm max riser 220mm pooningutrepp | 50 | 0

# IfcOpeningElement: Opening (224)
Name | In
2 x Basic Wall:40_Betoon:4940457 | 1 korrus
Basic Wall:76_Betoon 5:4953727 | Kelder
2 x Basic Wall:54_Betoon 2:4958210 | 1 korrus
Basic Wall:39_Betoon 3:4984559:1 | Kelder
Basic Wall:54_Betoon 2:4986084 | Kelder
Basic Wall:11_Betoon 2:5005212 | 3 korrus
Basic Wall:39_Betoon 3:5005466:1 | 3 korrus
3 x Basic Wall:52_Betoon 2:5006746 | Kelder
3 x Basic Wall:74_Betoon 2:5009205 | 3 korrus
sma_D02:1200 x 2100mm SU-11 Tuletokke:5734521:1 | 1 korrus
Basic Wall:Olemasolev Soojustatud Välissein:5376043 | 1 korrus | Classification: VS-1 (Uniformat)
3 x Basic Wall:Olemasolev Soojustatud Välissein:5381178 | 1 korrus | Classification: VS-1 (Uniformat)
Basic Wall:Olemasolev Soojustatud Välissein:5383293 | 1 korrus | Classification: VS-1 (Uniformat)
2 x Basic Wall:50_Betoon + UUS Soojustus 2:5383708 | 1 korrus
Basic Wall:10_FIBO + 2xKROHV:5397222 | 1 korrus
Basic Wall:Uus Välissein + Soojustus:5441409 | 1 korrus
 | 1 korrus
Floor:Paneel 220 +80 tasandus:5498146:2 | 1 korrus
3 x  | 2 korrus
Floor:Paneel 220 +80 tasandus:5500753:2 | 2 korrus
2 x  | 3 korrus
sma_D01:900 x 2100mm Tuletokke:5663521:1 | Kelder
2 x  | Katus
Basic Wall:15_FIBO:5504936 | 3 korrus
4 x Basic Wall:19_Betoon 2:5520045 | Kelder
Basic Wall:15_FIBO:5610483 | 3 korrus
Basic Wall:15_FIBO:5684356 | 2 korrus
sma_D02:1200 x 2100mm SU-7 Liigendiga siseuks:5662786:1 | 1 korrus
sma_D01:1010 x 2110_Siseuks:5679099:1 | Kelder
Basic Wall:Kips plaat_tagasein:5770740 | 1 korrus
sma_D01:700 x 2100mm SU-13 Tuletokke:5659354:1 | 3 korrus
sma_D01:810 x 2110_SU-01 Siseuks:5659131:1 | 3 korrus
sma_D01:700 x 2100mm Tuletokke:5655986:1 | 1 korrus
sma_D01:1000 x 2100mm SU-9 Tuletokke:5645348:1 | Saali lagi
sma_D01:910 x 2110_SU-02 Siseuks:5610694:1 | 3 korrus
sma_D02:1200 x 2100mm SU-7 Liigendiga siseuks:5598054:1 | 1 korrus
sma_D01:900 x 2100mm Tuletokke:5539298:1 | Kelder
sma_D01:1010 x 2110_SU-03 Siseuks:5538980:1 | Kelder
sma_D01:810 x 2110_SU-08 Tuletõkkeuks:5644861:1 | Saali lagi
sma_D02:1200 x 2100mm SU-11 Tuletokke:5525689:1 | 2 korrus
sma_D02:1200 x 2100mm SU-11 Tuletokke:5524844:1 | 2 korrus
SMA_Overhead-Sectional_3000mm +käiguuks 1000.0002:Tostuks 200 x 228mm:5521871:1 | Kelder
sma_D01:1000 x 2100mm SU-9 Tuletokke:5520833:1 | Kelder
sma_D01:1000 x 2100mm Tuletokke_old:5520700:1 | Kelder
M_Door-Exterior-Single-Two_Lite:Valisuks 1000x2100:5521471:1 | Kelder
sma_D01:910 x 2110_SU-02 Siseuks:5526233:1 | 2 korrus
sma_D01:910 x 2110_SU-02 Siseuks:5526406:1 | 2 korrus
sma_D01:810 x 2110_SU-01 Siseuks:5525972:1 | 2 korrus
sma_D02:1200 x 2100mm SU-11 Tuletokke:5505960:1 | 3 korrus
sma_D01:810 x 2110_SU-01 Siseuks:5505673:1 | 3 korrus
sma_D02:1200 x 2100mm SU-11 Tuletokke:5504033:1 | 3 korrus
sma_D01:810 x 2110_SU-01 Siseuks:5525862:1 | 2 korrus
M_Door-Exterior-Double:1600X2100 SU-6 Kahepoolne siseuks:5526771:1 | 2 korrus
sma_D01:810 x 2110_SU-01 Siseuks:5501862:1 | 3 korrus
sma_D01:810 x 2110_SU-01 Siseuks:5501861:1 | 3 korrus
sma_D01:810 x 2110_SU-01 Siseuks:5501860:1 | 3 korrus
sma_D01:810 x 2110_SU-01 Siseuks:5501859:1 | 3 korrus
sma_D01:810 x 2110_SU-01 Siseuks:5501858:1 | 3 korrus
sma_D01:810 x 2110_SU-01 Siseuks:5501857:1 | 3 korrus
sma_D01:810 x 2110_SU-01 Siseuks:5501856:1 | 3 korrus
sma_D01:810 x 2110_SU-04 Siseuks:5501855:1 | 3 korrus
sma_D01:810 x 2110_SU-04 Siseuks:5501854:1 | 3 korrus
sma_D01:810 x 2110_SU-01 Siseuks:6162709:1 | 2 korrus
sma_D01:810 x 2110_SU-01 Siseuks:6162313:1 | 2 korrus
sma_D01:810 x 2110_SU-01 Siseuks:5501834:1 | 2 korrus
sma_D01:810 x 2110_SU-01 Siseuks:5501833:1 | 2 korrus
sma_D02:1200 x 2100mm SU-7 Liigendiga siseuks:5421839:1 | 1 korrus
Basic Wall:14_Betoon 2:4946090 | 1 korrus
sma_D01:810 x 2110_SU-01 Siseuks:5421071:1 | 1 korrus
sma_D01:810 x 2110_SU-01 Siseuks:5421125:1 | 1 korrus
sma_D01:810 x 2110_SU-01 Siseuks:5421278:1 | 1 korrus
sma_D01:810 x 2110_SU-01 Siseuks:5529007:1 | 1 korrus
sma_D01:1010 x 2110_SU-05 Siseuks:5418990:1 | 1 korrus
sma_D01:1000 x 2100mm SU-9 Tuletokke:5177906:1 | Kelder
SMA_Overhead-Sectional_3000mm +käiguuks 1000.0002:2890 x 2470mm 2:5028620:1 | Kelder
sma_D01:810 x 2110_SU-04 Siseuks:5176937:1 | Kelder
sma_D01:810 x 2110_SU-01 Siseuks:5176459:1 | Kelder
sma_D01:700 x 2100mm PVC siseuks:5177202:1 | Kelder
sma_D01:1010 x 2110_Siseuks:5678905:1 | Kelder
sma_D01:1000 x 2100mm SU-9 Tuletokke:5678858:1 | Kelder
sma_D01:810 x 2110_SU-01 Siseuks:5421560:1 | 1 korrus
sma_D01:1000 x 2100mm SU-9 Tuletokke:5131036:1 | Kelder
sma_D01:1300 x 2290mm 3:5024698:1 | Kelder
SMA_Overhead-Sectional_3000mm +käiguuks 1000.0002:285 x 228mm:5028430:1 | Kelder
SMA_Overhead-Sectional_3000mm +käiguuks 1000.0002:285 x 228mm:5028002:1 | Kelder
sma_D01:700 x 2100mm PVC siseuks:5177402:1 | Kelder
sma_D01:810 x 2110_SU-01 Siseuks:5176099:1 | Kelder
sma_D01:810 x 2110_SU-01 Siseuks:5176089:1 | Kelder
sma_D01:1000 x 2100mm SU-9 Tuletokke:5175119:1 | Kelder
sma_D01:1010 x 2110_SU-03 Siseuks:5175248:1 | Kelder
sma_D01:810 x 2110_SU-01 Siseuks:5605626:1 | 2 korrus
sma_D01:810 x 2110_SU-04 Siseuks:5525817:1 | 2 korrus
Basic Wall:16_Betoon 2:4997248 | 2 korrus
sma_D01:810 x 2110_SU-01 Siseuks:5525812:1 | 2 korrus
sma_D01:810 x 2110_SU-01 Siseuks:5525809:1 | 2 korrus
sma_D01:810 x 2110_SU-01 Siseuks:5525805:1 | 2 korrus
sma_D01:810 x 2110_SU-01 Siseuks:5525801:1 | 2 korrus
sma_D01:700 x 2100mm SU-13 Tuletokke:5656155:1 | 2 korrus
Basic Wall:42_Betoon:4998442 | 2 korrus
Basic Wall:122_Betoon 8:4999173 | 2 korrus
M_Door-Exterior-Double:1600X2100 SU-6 Kahepoolne siseuks:5526639:1 | 2 korrus
sma_D01:810 x 2110_SU-01 Siseuks:5505375:1 | 3 korrus
sma_D01:810 x 2110_SU-08 Tuletõkkeuks:5505347:1 | 3 korrus
sma_D01:810 x 2110_SU-01 Siseuks:5212508:1 | 3 korrus
Basic Wall:12_Betoon:5005175 | 3 korrus
sma_D01:810 x 2110_SU-01 Siseuks:5213255:1 | 3 korrus
sma_D01:810 x 2110_SU-01 Siseuks:5212962:1 | 3 korrus
sma_D01:910 x 2110_SU-02 Siseuks:5216460:1 | 3 korrus
sma_D01:1010 x 2110_SU-03 Siseuks:5217891:1 | 3 korrus
sma_D01:1360 x 2270mm 2:5024613:1 | Kelder
Concept ExtSgl:1200 x 2200mm:5030536:1 | 2 korrus
Family7:Family7:5032530:1 | 2 korrus
Family8:Family8:5048661:1 | 2 korrus
Family8:Family8:5049596:1 | 2 korrus
sma_D01:900 x 2100mm Tuletokke:5125999:1 | Kelder
sma_D01:1000 x 2100mm SU-9 Tuletokke:5131187:1 | Kelder
sma_D01:1000 x 2100mm SU-9 Tuletokke:5175751:1 | Kelder
sma_D01:810 x 2110_SU-01 Siseuks:5176282:1 | Kelder
sma_D01:810 x 2110_SU-01 Siseuks:5213346:1 | 3 korrus
sma_W2:A-1* 2050 x 1730mm Avatav:5378157:1 | 1 korrus
sma_W2:A-1* 2050 x 1730mm Avatav:5377839:1 | 1 korrus
sma_W2:A-1* 2050 x 1730mm Avatav:5378010:1 | 1 korrus
sma_W2:A-1* 2050 x 1730mm Avatav:5376354:1 | 1 korrus
sma_W2:A-1* 2050 x 1730mm Avatav:5376976:1 | 1 korrus
sma_W2:A-1* 2050 x 1730mm Avatav:5377496:1 | 1 korrus
sma_W2:A-1* 2050 x 1730mm Avatav:5377605:1 | 1 korrus
sma_W2:A-1* 2050 x 1730mm Avatav:5377736:1 | 1 korrus
sma_W2:A-1* 2050 x 1730mm Avatav:5379609:1 | 1 korrus
sma_W2:A-1* 2050 x 1730mm Avatav:5379610:1 | 1 korrus
sma_W2:A-1* 2050 x 1730mm Avatav:5379611:1 | 1 korrus
sma_W2:A-1* 2050 x 1730mm Avatav:5379612:1 | 1 korrus
sma_W2:A-1* 2050 x 1730mm Avatav:5379613:1 | 1 korrus
sma_W2:A-1* 2050 x 1730mm Avatav:5379614:1 | 1 korrus
sma_W2:A-1* 2050 x 1730mm Avatav:5379615:1 | 1 korrus
sma_W2:A-1* 2050 x 1730mm Avatav:5379619:1 | 1 korrus
sma_W2:A-1* 2050 x 1730mm Avatav:5379620:1 | 1 korrus
sma_W2:A-1* 2050 x 1730mm Avatav:5379621:1 | 1 korrus
sma_W2:A-1* 2050 x 1730mm Avatav:5379622:1 | 1 korrus
sma_W2:A-1* 2050 x 1730mm Avatav:5379623:1 | 1 korrus
sma_W2:A-1* 2050 x 1730mm Avatav:5379624:1 | 1 korrus
sma_W2:A-1* 2050 x 1730mm Avatav:5379625:1 | 1 korrus
sma_W2:A-1* 2050 x 1730mm Avatav:5379659:1 | 1 korrus
sma_W2:A-1* 2050 x 1730mm Avatav:5379691:1 | 1 korrus
sma_W2:A-1* 2050 x 1730mm Avatav:5382365:1 | 1 korrus
sma_W2:A-1* 2050 x 1730mm Avatav:5382360:1 | 1 korrus
sma_W2:A-1* 2050 x 1730mm Avatav:5382361:1 | 1 korrus
sma_W2:A-1* 2050 x 1730mm Avatav:5382351:1 | 1 korrus
sma_W2:A-1* 2050 x 1730mm Avatav:5382352:1 | 1 korrus
sma_W2:A-1* 2050 x 1730mm Avatav:5382353:1 | 1 korrus
sma_W2:A-1* 2050 x 1730mm Avatav:5382350:1 | 1 korrus
sma_W2:A-1* 2050 x 1730mm Avatav:5381426:1 | 1 korrus
sma_W2:A-1* 2050 x 1730mm Avatav:5381567:1 | 1 korrus
sma_W2:A-1* 2050 x 1730mm Avatav:5381680:1 | 1 korrus
sma_W2:A-1* 2050 x 1730mm Avatav:5381827:1 | 1 korrus
sma_W2:A-1* 2050 x 1730mm Avatav:5381942:1 | 1 korrus
sma_W2:A-1* 2050 x 1730mm Avatav:5382079:1 | 1 korrus
sma_W2:A-1* 2050 x 1730mm Avatav:5382204:1 | 1 korrus
sma_W2:A-1* 2050 x 1730mm Avatav:5382349:1 | 1 korrus
sma_W2:A-1* 2050 x 1730mm Avatav:5382354:1 | 1 korrus
sma_W2:A-1* 2050 x 1730mm Avatav:5382355:1 | 1 korrus
sma_W2:A-1* 2050 x 1730mm Avatav:5382359:1 | 1 korrus
sma_W2:A-1* 2050 x 1730mm Avatav:5382362:1 | 1 korrus
sma_W2:A-1* 2050 x 1730mm Avatav:5382363:1 | 1 korrus
sma_W2:A-1* 2050 x 1730mm Avatav:5382364:1 | 1 korrus
sma_W2:A-1 UUS 2050 x 1730mm Avatav:5383687:1 | 1 korrus
3 x Basic Wall:Olemasolev Soojustatud Välissein:5383293 | 1 korrus
sma_W2:A-1* 2050 x 1730mm Avatav:5383425:1 | 1 korrus
sma_W2:A-1 UUS 2050 x 1730mm Avatav:5383691:1 | 1 korrus
sma_D01:810 x 2110_SU-01 Siseuks:5501832:1 | 2 korrus
sma_W2:A-1 UUS 2050 x 1730mm Avatav:5516155:1 | 1 korrus
sma_W2:A-1 UUS 2050 x 1730mm Avatav:5516291:1 | 1 korrus
ULO1 - ulkolasipariovi:1400x2200 VU-2 Välisuks:5497573:1 | 1 korrus
sma_W5:A-4 2470 x 1200mm Avatav:5516456:1 | 2 korrus
sma_W5:A-3 3490 x 1700mm Avatav:5516959:1 | 2 korrus
sma_W5:A-4 2470 x 1200mm Avatav:5517125:1 | 2 korrus
VR-03:VR-03 LAI REST:5613851:1 | 2 korrus
sma_W2:A-1 UUS 2050 x 1730mm Avatav:5388931:1 | 2 korrus
sma_D01:810 x 2110_SU-01 Siseuks:5421597:1 | 1 korrus
sma_D01:810 x 2110_SU-04 Siseuks:5418429:1 | 1 korrus
sma_D01:810 x 2110_SU-04 Siseuks:5418777:1 | 1 korrus
sma_D01:810 x 2110_SU-01 Siseuks:5419649:1 | 1 korrus
sma_D01:810 x 2110_SU-01 Siseuks:5419751:1 | 1 korrus
sma_D01:810 x 2110_SU-01 Siseuks:5420076:1 | 1 korrus
sma_D01:810 x 2110_SU-01 Siseuks:5420207:1 | 1 korrus
sma_D01:1010 x 2110_SU-03 Siseuks:5423794:1 | 1 korrus
sma_D01:810 x 2110_SU-01 Siseuks:5423834:1 | 1 korrus
sma_D02:1200 x 2100mm SU-11 Tuletokke:5522984:1 | 1 korrus
sma_D01:1010 x 2110_SU-05 Siseuks:5424565:1 | 1 korrus
sma_D01:810 x 2110_SU-04 Siseuks:5424028:1 | 1 korrus
sma_D01:810 x 2110_SU-04 Siseuks:5424665:1 | 1 korrus
sma_D01:810 x 2110_SU-01 Siseuks:5420376:1 | 1 korrus
sma_D01:810 x 2110_SU-01 Siseuks:5420581:1 | 1 korrus
sma_D01:810 x 2110_SU-01 Siseuks:5420668:1 | 1 korrus
sma_D01:810 x 2110_SU-01 Siseuks:5420805:1 | 1 korrus
sma_D01:1000 x 2100mm SU-9 Tuletokke:5422734:1 | 1 korrus
sma_W5:A-6 2590 x 1700mm Mitteavatav:5444269:1 | 1 korrus
ULO1 - ulkolasipariovi:1400x2200 VU-1 Välisuks:5497654:1 | 1 korrus
sma_W5:A-6 2590 x 1700mm Mitteavatav:5443895:1 | 1 korrus
sma_W5:A-6 2590 x 1700mm Mitteavatav:5444136:1 | 1 korrus
sma_W2:A-2 2050 x 1430mm Avatav:5443804:1 | 1 korrus
sma_W2:A-2 2050 x 1430mm Avatav:5441705:1 | 1 korrus
sma_D01:810 x 2110_SU-04 Siseuks:5501825:1 | 2 korrus
sma_D01:810 x 2110_SU-04 Siseuks:5501826:1 | 2 korrus
sma_D01:810 x 2110_SU-01 Siseuks:5501827:1 | 2 korrus
sma_D01:810 x 2110_SU-01 Siseuks:5501829:1 | 2 korrus
sma_D01:810 x 2110_SU-01 Siseuks:5501831:1 | 2 korrus

# IfcRailing: Railing:1100mm, Railing:1100mm:5509949
In: 1 korrus
Pset_RailingCommon - IsExternal: no; Reference: 1100mm; Height: 1219.2 mm

# IfcRailing: Railing:Kasipuu (6)
In: 3 korrus
Pset_RailingCommon - IsExternal: no; Reference: Kasipuu; Height: 1219.2 mm
Name (Railing:Kasipuu:...)
5648493
5648497
5688198
5690274
5690784
5691263

# IfcRailing: Railings 1, Railings 1:Railings 1:5079102
In: Kelder
Pset_RailingCommon - IsExternal: no; Reference: Railings 1

# IfcRailing: Railings 2, Railings 2:Railings 2:5095353
In: Kelder
Pset_RailingCommon - IsExternal: no; Reference: Railings 2

# IfcRailing: Railings 3, Railings 3:Railings 3:5278858
In: 1 korrus
Pset_RailingCommon - IsExternal: no; Reference: Railings 3

# IfcRailing: Railings 4, Railings 4:Railings 4:5283503
In: 1 korrus
Pset_RailingCommon - IsExternal: no; Reference: Railings 4

# IfcRailing: Railings 5, Railings 5:Railings 5:5293692
In: Kelder
Pset_RailingCommon - IsExternal: no; Reference: Railings 5

# IfcRailing: Railings 6, Railings 6:Railings 6:5297767
In: Kelder
Pset_RailingCommon - IsExternal: no; Reference: Railings 6

# IfcRailing: Railings 7, Railings 7:Railings 7:5305380
In: Kelder
Pset_RailingCommon - IsExternal: no; Reference: Railings 7

# IfcRoof: Basic Roof:Generic - 200mm, Basic Roof:Generic - 200mm:5514972
In: Katus
Pset_RoofCommon - IsExternal: yes; Reference: Generic - 200mm; TotalArea: 8.93722 m2; ProjectedArea: 8.45031 m2

# IfcRoof: Basic Roof:Generic - 200mm:5057396 (5)
Material: Default Roof
Pset_RoofCommon - IsExternal: yes; Reference: Generic - 200mm
Name (Basic Roof:Generic - 200mm:...) | In | TotalArea (m2) | ProjectedArea (m2)
5057020 | 3 korrus | 122.063 | 116.182
5331569 | Katus | 370.089 | 351.789
5332790 | Katus | 1.53483 | 1.44875
5333655 | Katus | 104.722 | 99.9049
5647085 | Katus | 59.6701 | 56.9776

# IfcRoof: Basic Roof:Soojustus 300 min vill:5647558 (2)
In: Katus
Material: Rock Wool(1)
Pset_RoofCommon - IsExternal: yes; Reference: Soojustus 300 min vill
Name (Basic Roof:Soojustus 300 min vill:...) | TotalArea (m2) | ProjectedArea (m2)
5647505 | 81.7434 | 77.9234
5647910 | 57.7722 | 55.1611

# IfcRoof: Roofs 1:Roofs 1:5051280, Roofs 1:Roofs 1:5051282
In: Katus 3
Pset_RoofCommon - IsExternal: yes; Reference: Roofs 1; TotalArea: 0.561442 m2

# IfcSlab: Assembled Stair:190mm max riser 250mm kesktrepp:5627275, Assembled Stair:Stair:5508512 Landing 1
In: 1 korrus
PredefinedType: LANDING; Material: Metalli - teräs, sinkitty
Pset_SlabCommon - IsExternal: no; PitchAngle: 0 deg; Reference: Non-Monolithic Landing

# IfcSlab: Basic Roof:Generic - 200mm, Basic Roof:Generic - 200mm:5514972
In: Katus
PredefinedType: ROOF; Material: NCS S 2570-R Syvä punainen, matta, ruisku 1 mm, Default Roof 200 mm
Pset_SlabCommon - IsExternal: yes; Reference: Generic - 200mm; PitchAngle: 19 deg

# IfcSlab: Floor:200 soojustus (3)
In: 1 korrus
PredefinedType: FLOOR; Material: Polyethylene, High Density 200 mm
Pset_SlabCommon - LoadBearing: no; IsExternal: no; Reference: 200 soojustus; ThermalTransmittance: 2.51 kg/K/s3
ARHITEKTUUR - 06 Kandev: no; 05 Asukoht(välis): no
Name (Floor:200 soojustus:...)
5651606 | Pset_SlabCommon - PitchAngle: 0 deg
5651730
5651730:2

# IfcSlab: Floor:Generic 150mm (13)
In: Kelder
PredefinedType: FLOOR; Material: Concrete - Cast In Situ 150 mm
Pset_SlabCommon - LoadBearing: no; IsExternal: no; PitchAngle: 0 deg; Reference: Generic 150mm
ARHITEKTUUR - 06 Kandev: no; 02 Materjal: Concrete - Cast In Situ; 03 Kategooria/Tüüp: P-I-E; 05 Asukoht(välis): no
Name (Floor:Generic 150mm:...)
5218586
5218624
5219220
5219333
5219365
5219603
5219647
5220084
5220120
5220161
5220669
5220717
5236477

# IfcSlab: Floor:Generic 2000mm 2, Floor:Generic 2000mm 2:5219691
In: Kelder
PredefinedType: FLOOR; Material: Concrete - Cast In Situ 200 mm
Pset_SlabCommon - LoadBearing: no; IsExternal: no; PitchAngle: 0 deg; Reference: Generic 2000mm 2
ARHITEKTUUR - 06 Kandev: no; 05 Asukoht(välis): no; 02 Materjal: Concrete - Cast In Situ

# IfcSlab: Floor:Generic 250mm 3, Floor:Generic 250mm 3:5219722
In: Kelder
PredefinedType: FLOOR; Material: Concrete - Cast In Situ 250 mm
Pset_SlabCommon - LoadBearing: no; IsExternal: no; PitchAngle: 0 deg; Reference: Generic 250mm 3
ARHITEKTUUR - 06 Kandev: no; 05 Asukoht(välis): no; 02 Materjal: Concrete - Cast In Situ

# IfcSlab: Floor:Generic 260mm 2, Floor:Generic 260mm 2:5222463
In: 1 korrus
PredefinedType: FLOOR; Material: Concrete - Cast In Situ 260 mm
Pset_SlabCommon - LoadBearing: no; IsExternal: no; PitchAngle: 0 deg; Reference: Generic 260mm 2
ARHITEKTUUR - 06 Kandev: no; 05 Asukoht(välis): no; 02 Materjal: Concrete - Cast In Situ

# IfcSlab: Floor:Keraamiline plaat 200x200 (14)
PredefinedType: FLOOR; Material: EST. Põrand. Plaatkate 3 mm
Pset_SlabCommon - LoadBearing: no; IsExternal: no; Reference: Keraamiline plaat 200x200
ARHITEKTUUR - 06 Kandev: no; 05 Asukoht(välis): no; 03 Kategooria/Tüüp: KP-4
Name (Floor:Keraamiline plaat 200x200:...) | In | PitchAngle (deg)
5745716 | 1 korrus
5745716:2 | 1 korrus
5745716:3 | 1 korrus
5745988 | 1 korrus
5745988:2 | 1 korrus
5746071 | 1 korrus | 0
5752362 | 2 korrus | 0
5752393 | 2 korrus | 0
5752426 | 2 korrus | 0
5753537 | 3 korrus | 0
5753570 | 3 korrus | 0
5755074 | Kelder | 0
5755140 | Kelder | 0
5755574 | Kelder | 0

# IfcSlab: Floor:Keraamiline plaat 600X300 (6)
PredefinedType: FLOOR; Material: Plaadi muster 3 mm
Pset_SlabCommon - LoadBearing: no; IsExternal: no; PitchAngle: 0 deg; Reference: Keraamiline plaat 600X300
ARHITEKTUUR - 06 Kandev: no; 05 Asukoht(välis): no; 03 Kategooria/Tüüp: KP-1
Name (Floor:Keraamiline plaat 600X300:...) | In
5747261 | 1 korrus
5748409 | 1 korrus
5749387 | 1 korrus
5750543 | 1 korrus
5756289 | Kelder
5757208 | Kelder

# IfcSlab: Floor:Paneel 220 +80 tasandus (4)
PredefinedType: FLOOR; Material: EST. Linoleum 3 mm, Concrete - Cast In Situ 70 mm, Concrete - Cast In Situ 220 mm
Pset_SlabCommon - LoadBearing: no; IsExternal: no; Reference: Paneel 220 +80 tasandus
ARHITEKTUUR - 06 Kandev: no; 05 Asukoht(välis): no; 02 Materjal: Concrete - Cast In Situ
Name (Floor:Paneel 220 +80 tasandus:...) | In
5498146 | 1 korrus
5500753 | 2 korrus
5500776 | 3 korrus
5535982 | Saali lagi | Pset_SlabCommon - PitchAngle: 0 deg

# IfcSlab: Floor:Paneel 220+300 soojustus (2)
In: Katus
PredefinedType: FLOOR; Material: Rock Wool 300 mm, Concrete - Cast In Situ 220 mm
Pset_SlabCommon - LoadBearing: no; IsExternal: no; Reference: Paneel 220+300 soojustus; ThermalTransmittance: 0.113333 kg/K/s3
ARHITEKTUUR - 06 Kandev: no; 05 Asukoht(välis): no; 02 Materjal: Concrete - Cast In Situ
Name (Floor:Paneel 220+300 soojustus:...)
5504254
5625389 | Pset_SlabCommon - PitchAngle: 0 deg

# IfcSlab: Floor:Porand 200 soojustus+SBS, Floor:Porand 200 soojustus+SBS:5646431
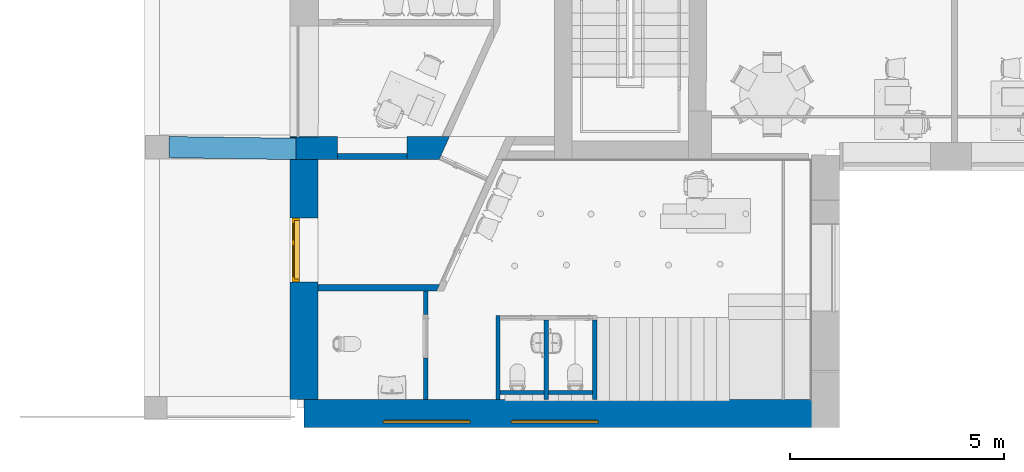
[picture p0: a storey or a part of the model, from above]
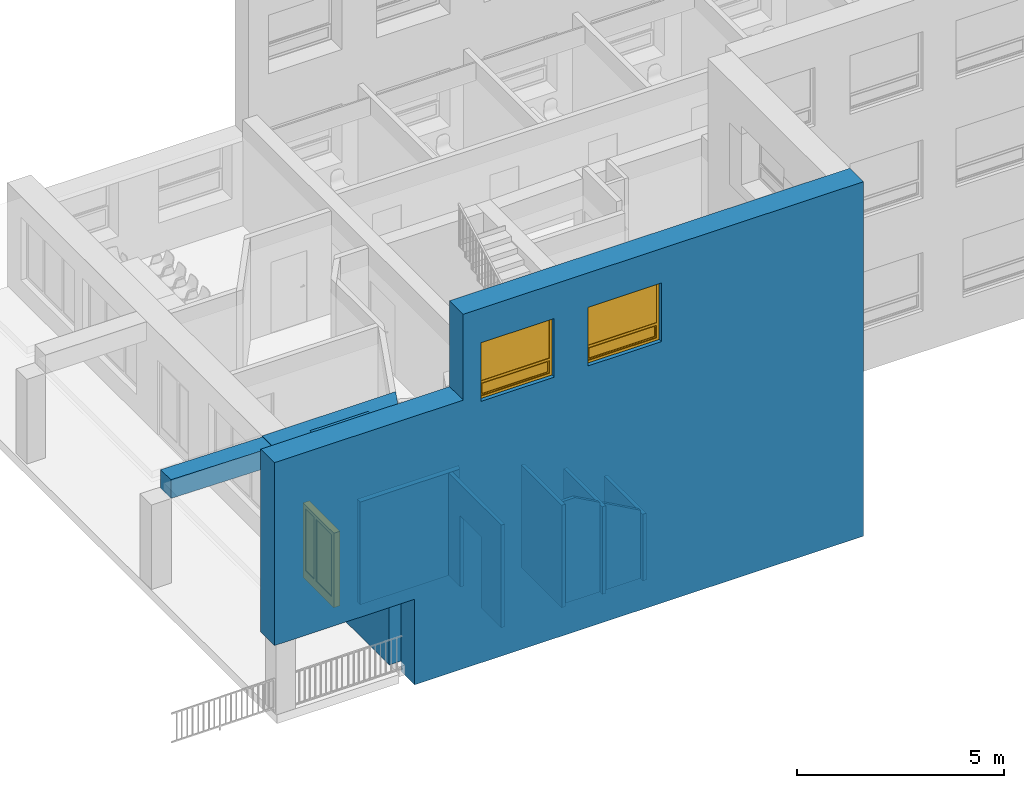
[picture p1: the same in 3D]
Properties of the parts of a building model (IFC2X3), part 3 of 3

# IfcSlab: Floor:Porand 200 soojustus+SBS, Floor:Porand 200 soojustus+SBS:5646431
In: Saali lagi
PredefinedType: FLOOR; Material: 2DMat 57EDF21F 10 mm, Polyethylene, High Density 200 mm
Pset_SlabCommon - LoadBearing: no; IsExternal: no; PitchAngle: 0 deg; Reference: Porand 200 soojustus+SBS; ThermalTransmittance: 2.51 kg/K/s3
ARHITEKTUUR - 06 Kandev: no; 05 Asukoht(välis): no

# IfcSlab: Floor:Porand 200+150 soojustus, Floor:Porand 200+150 soojustus:5626787
In: Kelder
PredefinedType: FLOOR; Material: Concrete - Cast In Situ 200 mm, Polyethylene, High Density 150 mm
Pset_SlabCommon - LoadBearing: no; IsExternal: no; PitchAngle: 0 deg; Reference: Porand 200+150 soojustus; ThermalTransmittance: 3.34667 kg/K/s3
ARHITEKTUUR - 06 Kandev: no; 05 Asukoht(välis): no; 02 Materjal: Concrete - Cast In Situ

# IfcSlab: Pad:Pad 1, Pad:Pad 1:5338360
In: Kelder
PredefinedType: FLOOR; Material: <Unnamed> 300 mm
Pset_SlabCommon - IsExternal: no; Reference: Pad 1

# IfcSlab: Roofs 1:Roofs 1:5051280, Roofs 1:Roofs 1:5051282:1
In: Katus 3
PredefinedType: ROOF
Pset_SlabCommon - IsExternal: yes; Reference: Roofs 1; PitchAngle: 0 deg

# IfcStair: Assembled Stair:190mm max riser 250mm kesktrepp:5627275, Assembled Stair:Stair:5508512
In: 1 korrus
Pset_StairCommon - IsExternal: no; Reference: 190mm max riser 250mm kesktrepp; NumberOfRiser: 21; NumberOfTreads: 19; RiserHeight: 158.333 mm; TreadLength: 300 mm
ARHITEKTUUR - 05 Asukoht(välis): no

# IfcStair: Assembled Stair:220mm max riser 220mm pooningutrepp:5648573, Assembled Stair:Stair:5648093
In: 3 korrus
Pset_StairCommon - IsExternal: no; Reference: 220mm max riser 220mm pooningutrepp; NumberOfRiser: 4; NumberOfTreads: 3; RiserHeight: 200 mm; TreadLength: 250 mm
ARHITEKTUUR - 05 Asukoht(välis): no

# IfcStairFlight: Assembled Stair:190mm max riser 250mm kesktrepp:5627275 (2)
In: 1 korrus
RiserHeight: 0.519466 mm; TreadLength: 0.984252 mm; Material: Metalli - teräs, sinkitty
Pset_StairFlightCommon - Reference: 50 mm Tread 13 mm Riser; NumberOfRiser: 21; NumberOfTreads: 19; RiserHeight: 158.333 mm; TreadLength: 300 mm; TreadLengthAtOffset: 300 mm; NosingLength: 0 mm; WalkingLineOffset: 650 mm; WaistThickness: 1300 mm
Name (Assembled Stair:Stair:...) | NumberOfRiser | NumberOfTreads
5508512 Run 1 | 10 | 9
5508512 Run 2 | 11 | 10

# IfcStairFlight: Assembled Stair:220mm max riser 220mm pooningutrepp:5648573, Assembled Stair:Stair:5648093 Run 1
In: 3 korrus
NumberOfRiser: 4; NumberOfTreads: 3; RiserHeight: 0.656168 mm; TreadLength: 0.82021 mm; Material: Metalli - teräs, sinkitty
Pset_StairFlightCommon - Reference: 50 mm Tread 13 mm Riser; NosingLength: 0 mm; NumberOfRiser: 4; NumberOfTreads: 3; RiserHeight: 200 mm; TreadLength: 250 mm; TreadLengthAtOffset: 250 mm; WalkingLineOffset: 500 mm; WaistThickness: 1000 mm

# IfcWall: Basic Wall:15_Betoon, Basic Wall:15_Betoon:4955718
In: Kelder
Type - PredefinedType: STANDARD; Material: __Betoonelement 150 mm
Pset_WallCommon - LoadBearing: no; IsExternal: yes; ExtendToStructure: yes; Reference: 15_Betoon
ARHITEKTUUR - 05 Asukoht(välis): yes; 06 Kandev: no; 02 Materjal: __Betoonelement

# IfcWall: Basic Wall:17_Betoon, Basic Wall:17_Betoon:4992077
In: 2 korrus
Material: NCS S 2570-R Syvä punainen, matta, ruisku, __Betoonelement
Pset_WallCommon - LoadBearing: no; ExtendToStructure: no; IsExternal: yes; Reference: 17_Betoon
ARHITEKTUUR - 05 Asukoht(välis): yes; 06 Kandev: no; 02 Materjal: __Betoonelement

# IfcWall: Basic Wall:25_Betoon, Basic Wall:25_Betoon:4952343
In: Kelder
Material: __Betoonelement
Pset_WallCommon - LoadBearing: no; IsExternal: yes; ExtendToStructure: yes; Reference: 25_Betoon
ARHITEKTUUR - 05 Asukoht(välis): yes; 06 Kandev: no; 02 Materjal: __Betoonelement

# IfcWall: Basic Wall:35_Betoon 3, Basic Wall:35_Betoon 3:4979218
In: Kelder
Material: __Betoonelement
Pset_WallCommon - LoadBearing: no; IsExternal: yes; ExtendToStructure: yes; Reference: 35_Betoon 3
ARHITEKTUUR - 05 Asukoht(välis): yes; 06 Kandev: no; 02 Materjal: __Betoonelement

# IfcWall: Basic Wall:38_Betoon 2, Basic Wall:38_Betoon 2:4997899
In: 2 korrus
Type - PredefinedType: STANDARD; Material: __Betoonelement 380 mm
Pset_WallCommon - LoadBearing: no; IsExternal: yes; ExtendToStructure: yes; Reference: 38_Betoon 2
ARHITEKTUUR - 05 Asukoht(välis): yes; 06 Kandev: no; 02 Materjal: __Betoonelement

# IfcWall: Basic Wall:41_Betoon 2 (3)
Type - PredefinedType: STANDARD; Material: __Betoonelement 410 mm
Pset_WallCommon - LoadBearing: no; IsExternal: yes; ExtendToStructure: yes; Reference: 41_Betoon 2
ARHITEKTUUR - 05 Asukoht(välis): yes; 06 Kandev: no; 02 Materjal: __Betoonelement
Name (Basic Wall:41_Betoon 2:...) | In
4947888 | 1 korrus
4983925 | Kelder
4999085 | 2 korrus

# IfcWall: Basic Wall:44_Betoon (3)
Material: NCS S 2570-R Syvä punainen, matta, ruisku, __Betoonelement
Pset_WallCommon - LoadBearing: no; ExtendToStructure: no; IsExternal: yes; Reference: 44_Betoon
ARHITEKTUUR - 05 Asukoht(välis): yes; 06 Kandev: no; 02 Materjal: __Betoonelement
Name (Basic Wall:44_Betoon:...) | In
4942499 | 1 korrus
5515533 | 2 korrus
5679993 | 1 korrus

# IfcWall: Basic Wall:45_Betoon, Basic Wall:45_Betoon:5000912
In: 2 korrus
Type - PredefinedType: STANDARD; Material: __Betoonelement 450 mm
Pset_WallCommon - LoadBearing: no; IsExternal: yes; ExtendToStructure: yes; Reference: 45_Betoon
ARHITEKTUUR - 05 Asukoht(välis): yes; 06 Kandev: no; 02 Materjal: __Betoonelement

# IfcWall: Basic Wall:51_Betoon 2, Basic Wall:51_Betoon 2:4984831
In: Kelder
Type - PredefinedType: STANDARD; Material: __Betoonelement 510 mm
Pset_WallCommon - LoadBearing: no; IsExternal: yes; ExtendToStructure: yes; Reference: 51_Betoon 2
ARHITEKTUUR - 05 Asukoht(välis): yes; 06 Kandev: no; 02 Materjal: __Betoonelement

# IfcWall: Basic Wall:54_Betoon 2, Basic Wall:54_Betoon 2:4955147
In: Kelder
Type - PredefinedType: STANDARD; Material: __Betoonelement 540 mm
Pset_WallCommon - LoadBearing: no; IsExternal: yes; ExtendToStructure: yes; Reference: 54_Betoon 2
ARHITEKTUUR - 05 Asukoht(välis): yes; 06 Kandev: no; 02 Materjal: __Betoonelement

# IfcWall: Basic Wall:60_Betoon, Basic Wall:60_Betoon:4952713
In: Kelder
Material: __Betoonelement
Pset_WallCommon - LoadBearing: no; ExtendToStructure: no; IsExternal: yes; Reference: 60_Betoon
ARHITEKTUUR - 05 Asukoht(välis): yes; 06 Kandev: no; 02 Materjal: __Betoonelement

# IfcWall: Basic Wall:63_Betoon 3, Basic Wall:63_Betoon 3:5009334
In: 3 korrus
Material: __Betoonelement
Pset_WallCommon - LoadBearing: no; ExtendToStructure: no; IsExternal: yes; Reference: 63_Betoon 3
ARHITEKTUUR - 05 Asukoht(välis): yes; 06 Kandev: no; 02 Materjal: __Betoonelement

# IfcWall: Basic Wall:68_Betoon (2)
In: Kelder
Material: __Betoonelement
Pset_WallCommon - LoadBearing: no; IsExternal: yes; ExtendToStructure: yes; Reference: 68_Betoon
ARHITEKTUUR - 05 Asukoht(välis): yes; 06 Kandev: no; 02 Materjal: __Betoonelement
Name (Basic Wall:68_Betoon:...)
4983080
4983466

# IfcWall: Basic Wall:75_Betoon 3, Basic Wall:75_Betoon 3:5334024
In: 3 korrus
Material: __Betoonelement
Pset_WallCommon - LoadBearing: no; IsExternal: yes; ExtendToStructure: yes; Reference: 75_Betoon 3
ARHITEKTUUR - 05 Asukoht(välis): yes; 06 Kandev: no; 02 Materjal: __Betoonelement

# IfcWall: Basic Wall:83_Betoon 5, Basic Wall:83_Betoon 5:4986352
In: Kelder
Type - PredefinedType: STANDARD; Material: __Betoonelement 830 mm
Pset_WallCommon - LoadBearing: no; IsExternal: yes; ExtendToStructure: yes; Reference: 83_Betoon 5
ARHITEKTUUR - 05 Asukoht(välis): yes; 06 Kandev: no; 02 Materjal: __Betoonelement

# IfcWall: Basic Wall:8_Betoon 2 (2)
In: 2 korrus
Type - PredefinedType: STANDARD; Material: NCS S 2570-R Syvä punainen, matta, ruisku 1 mm, __Betoonelement 90 mm
Pset_WallCommon - LoadBearing: no; ExtendToStructure: no; IsExternal: yes; Reference: 8_Betoon 2
ARHITEKTUUR - 05 Asukoht(välis): yes; 06 Kandev: no; 02 Materjal: __Betoonelement
Name (Basic Wall:8_Betoon 2:...)
5686806
5690771

# IfcWall: Basic Wall:9_Betoon 2 (2)
In: Kelder
Type - PredefinedType: STANDARD; Material: __Betoonelement 90 mm
Pset_WallCommon - LoadBearing: no; IsExternal: yes; Reference: 9_Betoon 2
ARHITEKTUUR - 05 Asukoht(välis): yes; 06 Kandev: no; 02 Materjal: __Betoonelement
Name (Basic Wall:9_Betoon 2:...) | ExtendToStructure
4986008 | yes
5176024 | no

# IfcWall: Basic Wall:Olemasolev Soojustatud Välissein, Basic Wall:Olemasolev Soojustatud Välissein:5684787
In: 1 korrus
Type - PredefinedType: STANDARD; Material: Plaster 10 mm, Polystyrene 150 mm, __Betoonelement 500 mm
Classification: VS-1 (Uniformat)
Pset_WallCommon - LoadBearing: no; ExtendToStructure: no; IsExternal: yes; Reference: Olemasolev Soojustatud Välissein; FireRating: EI 240; ThermalTransmittance: 0.527814 kg/K/s3
ARHITEKTUUR - 05 Asukoht(välis): yes; 06 Kandev: no; 01 Nimetus: Välissein; 02 Materjal: __Betoonelement; 04 Tulepüsivus: EI 240; 07 Helipidavus: 49 dB; 08 Soojusläbivus: 0.17 W/m2K

# IfcWall: Basic Wall:Uus Välissein + Soojustus (2)
In: 1 korrus
Type - PredefinedType: STANDARD; Material: Plaster 10 mm, EST. Soojustus. Kivivill. Default 200 mm, EST. Müüritis. Väikeplokk. Kergkruusplokk 450 mm, Plaster 10 mm
Pset_WallCommon - LoadBearing: no; ExtendToStructure: no; IsExternal: yes; Reference: Uus Välissein + Soojustus; ThermalTransmittance: 25.5 kg/K/s3
ARHITEKTUUR - 05 Asukoht(välis): yes; 06 Kandev: no; 02 Materjal: EST. Müüritis. Väikeplokk. Kergkruusplokk; 07 Helipidavus: 49 dB; 08 Soojusläbivus: 0.15 W/m2K
Name (Basic Wall:Uus Välissein + Soojustus:...)
5684988
5685313

# IfcWall: Walls 10:Walls 10, Walls 10:Walls 10:5008487
In: Kelder
Pset_WallCommon - LoadBearing: no; ExtendToStructure: yes; IsExternal: no; Reference: Walls 10
ARHITEKTUUR - 04 Tulepüsivus: EI 240

# IfcWall: Walls 11:Walls 11, Walls 11:Walls 11:5052966
In: Katus 3
Type - Material: Wood - Sheathing - plywood
Pset_WallCommon - LoadBearing: no; ExtendToStructure: no; IsExternal: no; Reference: Walls 11
ARHITEKTUUR - 02 Materjal: Wood - Sheathing - plywood

# IfcWall: Walls 12:Walls 12, Walls 12:Walls 12:5054575
In: Saali lagi
Pset_WallCommon - LoadBearing: no; ExtendToStructure: no; IsExternal: no; Reference: Walls 12

# IfcWall: Walls 14:Walls 14, Walls 14:Walls 14:5059089
In: Kelder
Pset_WallCommon - LoadBearing: no; ExtendToStructure: no; IsExternal: no; Reference: Walls 14

# IfcWall: Walls 16:Walls 16, Walls 16:Walls 16:5131910
In: Kelder
Pset_WallCommon - LoadBearing: no; ExtendToStructure: no; IsExternal: no; Reference: Walls 16

# IfcWall: Walls 17:Walls 17, Walls 17:Walls 17:5132869
In: Kelder
Pset_WallCommon - LoadBearing: no; ExtendToStructure: no; IsExternal: no; Reference: Walls 17

# IfcWall: Walls 19:Walls 19, Walls 19:Walls 19:5175451
In: Kelder
Pset_WallCommon - LoadBearing: no; ExtendToStructure: no; IsExternal: no; Reference: Walls 19

# IfcWall: Walls 1:Walls 1, Walls 1:Walls 1:4962672
In: 1 korrus
Pset_WallCommon - LoadBearing: no; ExtendToStructure: yes; IsExternal: no; Reference: Walls 1

# IfcWall: Walls 52:Walls 52, Walls 52:Walls 52:5252691
In: 1 korrus
Pset_WallCommon - LoadBearing: no; ExtendToStructure: no; IsExternal: no; Reference: Walls 52

# IfcWall: Walls 53:Walls 53, Walls 53:Walls 53:5252886
In: 1 korrus
Pset_WallCommon - LoadBearing: no; ExtendToStructure: no; IsExternal: no; Reference: Walls 53
ARHITEKTUUR - 04 Tulepüsivus: EI 240

# IfcWall: Walls 5:Walls 5, Walls 5:Walls 5:4987932
In: Kelder
Pset_WallCommon - LoadBearing: no; ExtendToStructure: yes; IsExternal: no; Reference: Walls 5

# IfcWall: Walls 6:Walls 6, Walls 6:Walls 6:5056805
In: Katus 3
Pset_WallCommon - LoadBearing: no; ExtendToStructure: no; IsExternal: no; Reference: Walls 6

# IfcWallStandardCase: Basic Wall:1.5_Betoon 3, Basic Wall:1.5_Betoon 3:5182176
In: Kelder
Type - PredefinedType: STANDARD; Material: __Betoonelement 15 mm
Pset_WallCommon - LoadBearing: no; ExtendToStructure: no; IsExternal: yes; Reference: 1.5_Betoon 3
ARHITEKTUUR - 05 Asukoht(välis): yes; 06 Kandev: no; 02 Materjal: __Betoonelement

# IfcWallStandardCase: Basic Wall:10_Betoon (3)
Type - PredefinedType: STANDARD; Material: __Betoonelement 100 mm
Pset_WallCommon - LoadBearing: no; ExtendToStructure: no; IsExternal: yes; Reference: 10_Betoon
ARHITEKTUUR - 05 Asukoht(välis): yes; 06 Kandev: no; 02 Materjal: __Betoonelement
Name (Basic Wall:10_Betoon:...) | In
5236356 | 3 korrus
5239870 | 2 korrus
5240913 | 3 korrus

# IfcWallStandardCase: Basic Wall:10_FIBO + 2xKROHV (19)
Type - PredefinedType: STANDARD; Material: Plaster 5 mm, CMU, Lightweight 90 mm, Plaster 5 mm
Pset_WallCommon - LoadBearing: no; IsExternal: yes; Reference: 10_FIBO + 2xKROHV; FireRating: EI 120; ThermalTransmittance: 2.12944 kg/K/s3
ARHITEKTUUR - 05 Asukoht(välis): yes; 06 Kandev: no; 01 Nimetus: Kergplokksein; 02 Materjal: CMU, Lightweight; 03 Kategooria/Tüüp: SS-3/2; 07 Helipidavus: 43 dB; 08 Soojusläbivus: -
Name (Basic Wall:10_FIBO + 2xKROHV:...) | In | ExtendToStructure
5396990 | 1 korrus | yes
5397222 | 1 korrus | no
5397334 | 1 korrus | yes
5397426 | 1 korrus | no
5397553 | 1 korrus | no
5639233 | Katus | yes
5655795 | 1 korrus | no
5655946 | 1 korrus | no
5656126 | 2 korrus | no
5656127 | 2 korrus | no
5656130 | 3 korrus | no | ARHITEKTUUR - 04 Tulepüsivus: EI 120
5656131 | 3 korrus | no | ARHITEKTUUR - 04 Tulepüsivus: EI 120
5656792 | 2 korrus | no | ARHITEKTUUR - 04 Tulepüsivus: EI 120
5656941 | 2 korrus | no | ARHITEKTUUR - 04 Tulepüsivus: EI 240
5657056 | 2 korrus | no | ARHITEKTUUR - 04 Tulepüsivus: EI 240
5657140 | 2 korrus | no | ARHITEKTUUR - 04 Tulepüsivus: EI 240
5657166 | 3 korrus | no | ARHITEKTUUR - 04 Tulepüsivus: EI 120
5719236 | Katus | no
5719338 | Katus | no

# IfcWallStandardCase: Basic Wall:10_FIBO + 4xKROHV, Basic Wall:10_FIBO + 4xKROHV:5685651
In: 3 korrus
Type - PredefinedType: STANDARD; Material: Plaster 10 mm, CMU, Lightweight 100 mm, Plaster 10 mm
Pset_WallCommon - LoadBearing: no; ExtendToStructure: no; IsExternal: yes; Reference: 10_FIBO + 4xKROHV; ThermalTransmittance: 1.85455 kg/K/s3
ARHITEKTUUR - 05 Asukoht(välis): yes; 06 Kandev: no; 02 Materjal: CMU, Lightweight

# IfcWallStandardCase: Basic Wall:11_Betoon 2 (3)
Type - PredefinedType: STANDARD; Material: __Betoonelement 110 mm
Pset_WallCommon - LoadBearing: no; IsExternal: yes; Reference: 11_Betoon 2
ARHITEKTUUR - 05 Asukoht(välis): yes; 06 Kandev: no; 02 Materjal: __Betoonelement
Name (Basic Wall:11_Betoon 2:...) | In | ExtendToStructure
4954186 | Kelder | yes
5005212 | 3 korrus | no
5685650 | 3 korrus | no

# IfcWallStandardCase: Basic Wall:122_Betoon 8, Basic Wall:122_Betoon 8:4999173
In: 2 korrus
Type - PredefinedType: STANDARD; Material: __Betoonelement 1220 mm
Pset_WallCommon - LoadBearing: no; IsExternal: yes; ExtendToStructure: yes; Reference: 122_Betoon 8
ARHITEKTUUR - 05 Asukoht(välis): yes; 06 Kandev: no; 02 Materjal: __Betoonelement

# IfcWallStandardCase: Basic Wall:12_Betoon (3)
Type - PredefinedType: STANDARD; Material: __Betoonelement 120 mm
Pset_WallCommon - LoadBearing: no; IsExternal: yes; Reference: 12_Betoon
ARHITEKTUUR - 05 Asukoht(välis): yes; 06 Kandev: no; 02 Materjal: __Betoonelement
Name (Basic Wall:12_Betoon:...) | In | ExtendToStructure
4953629 | Kelder | yes
4954409 | Kelder | yes
5005175 | 3 korrus | no

# IfcWallStandardCase: Basic Wall:13_Betoon 2 (3)
In: Kelder
Type - PredefinedType: STANDARD; Material: __Betoonelement 130 mm
Pset_WallCommon - LoadBearing: no; IsExternal: yes; ExtendToStructure: yes; Reference: 13_Betoon 2
ARHITEKTUUR - 05 Asukoht(välis): yes; 06 Kandev: no; 02 Materjal: __Betoonelement
Name (Basic Wall:13_Betoon 2:...)
4979450
4984902
4984976

# IfcWallStandardCase: Basic Wall:14_Betoon 2 (6)
Type - PredefinedType: STANDARD; Material: __Betoonelement 140 mm
Pset_WallCommon - LoadBearing: no; IsExternal: yes; ExtendToStructure: yes; Reference: 14_Betoon 2
ARHITEKTUUR - 05 Asukoht(välis): yes; 06 Kandev: no; 02 Materjal: __Betoonelement
Name (Basic Wall:14_Betoon 2:...) | In
4946090 | 1 korrus
4954324 | Kelder
4954525 | Kelder
4978971 | Kelder
4996912 | 2 korrus
4997318 | 2 korrus

# IfcWallStandardCase: Basic Wall:15 soojustus (7)
In: Katus
Type - PredefinedType: STANDARD; Material: Plasterboard 150 mm
Pset_WallCommon - LoadBearing: no; IsExternal: yes; Reference: 15 soojustus
ARHITEKTUUR - 05 Asukoht(välis): yes; 06 Kandev: no; 02 Materjal: Plasterboard
Name (Basic Wall:15 soojustus:...) | ExtendToStructure
5637782 | no
5637876 | yes
5637969 | yes
5638561 | yes
5639543 | yes
5719567 | yes
5719909 | no

# IfcWallStandardCase: Basic Wall:150 FIBO + UUS Soojustus 150 (2)
In: Saali lagi
Type - PredefinedType: STANDARD; Material: Polystyrene, Expanded 150 mm, CMU, Lightweight 150 mm
Pset_WallCommon - LoadBearing: no; IsExternal: yes; ExtendToStructure: yes; Reference: 150 FIBO + UUS Soojustus 150; ThermalTransmittance: 0.198582 kg/K/s3
ARHITEKTUUR - 05 Asukoht(välis): yes; 06 Kandev: no; 02 Materjal: CMU, Lightweight
Name (Basic Wall:150 FIBO + UUS Soojustus 150:...)
5534829
5644672

# IfcWallStandardCase: Basic Wall:154_Betoon 8, Basic Wall:154_Betoon 8:4998557
In: 2 korrus
Type - PredefinedType: STANDARD; Material: __Betoonelement 1540 mm
Pset_WallCommon - LoadBearing: no; IsExternal: yes; ExtendToStructure: yes; Reference: 154_Betoon 8
ARHITEKTUUR - 05 Asukoht(välis): yes; 06 Kandev: no; 02 Materjal: __Betoonelement

# IfcWallStandardCase: Basic Wall:15_Betoon (8)
Type - PredefinedType: STANDARD; Material: __Betoonelement 150 mm
Pset_WallCommon - LoadBearing: no; IsExternal: yes; Reference: 15_Betoon
ARHITEKTUUR - 05 Asukoht(välis): yes; 06 Kandev: no; 02 Materjal: __Betoonelement
Name (Basic Wall:15_Betoon:...) | In | ExtendToStructure
4945916 | 1 korrus | yes
4962467 | 1 korrus | yes
4996980 | 2 korrus | yes
4998134 | 2 korrus | yes
5003448 | 3 korrus | no
5004899 | 3 korrus | no
5004950 | 3 korrus | no
5199898 | 2 korrus | no

# IfcWallStandardCase: Basic Wall:15_FIBO (73)
Type - PredefinedType: STANDARD; Material: Plaster 10 mm, EST. Müüritis. Väikeplokk. Kergkruusplokk 130 mm, Plaster 10 mm
Pset_WallCommon - LoadBearing: no; IsExternal: yes; Reference: 15_FIBO; FireRating: EI 240; ThermalTransmittance: 25.5 kg/K/s3
ARHITEKTUUR - 05 Asukoht(välis): yes; 06 Kandev: no; 01 Nimetus: Sisesein; 02 Materjal: EST. Müüritis. Väikeplokk. Kergkruusplokk; 03 Kategooria/Tüüp: SS-03/1; 07 Helipidavus: 49 dB; 08 Soojusläbivus: -
Name (Basic Wall:15_FIBO:...) | In | ExtendToStructure | 04 Tulepüsivus
5392284 | 1 korrus | yes | EI 240
5392596 | 1 korrus | yes | EI 240
5392994 | 1 korrus | yes | EI 240
5393390 | 1 korrus | yes | EI 240
5393508 | 1 korrus | yes | EI 240
5393698 | 1 korrus | yes | EI 240
5393741 | 1 korrus | yes | EI 240
5393829 | 1 korrus | yes | EI 240
5393857 | 1 korrus | yes | EI 240
5393866 | 1 korrus | yes | EI 240
5394068 | 1 korrus | yes | EI 240
5394328 | 1 korrus | yes | EI 240
5394418 | 1 korrus | yes | EI 240
5394623 | 1 korrus | yes | EI 240
5394774 | 1 korrus | yes | EI 240
5394874 | 1 korrus | yes | EI 240
5394976 | 1 korrus | yes | EI 240
5395642 | 1 korrus | yes | EI 240
5395956 | 1 korrus | yes | EI 240
5396131 | 1 korrus | yes | EI 240
5396359 | 1 korrus | yes | EI 240
5396673 | 1 korrus | yes | EI 240
5501814 | 2 korrus | yes | EI 240
5501815 | 2 korrus | yes | EI 240
5501816 | 2 korrus | yes | EI 240
5501817 | 2 korrus | yes | EI 240
5501818 | 2 korrus | yes | EI 240
5501819 | 2 korrus | yes | EI 240
5501820 | 2 korrus | yes | EI 240
5501821 | 2 korrus | yes | EI 240
5501822 | 2 korrus | yes | EI 240
5501843 | 3 korrus | no | EI 240
5501844 | 3 korrus | no | EI 240
5501845 | 3 korrus | no | EI 240
5501846 | 3 korrus | no | EI 240
5501847 | 3 korrus | no | EI 240
5501848 | 3 korrus | no | EI 240
5501849 | 3 korrus | no | EI 240
5501850 | 3 korrus | no | EI 240
5502697 | 2 korrus | yes | EI 240
5502956 | 2 korrus | yes | EI 240
5503018 | 2 korrus | yes | EI 240
5503952 | 3 korrus | no | EI 240
5504936 | 3 korrus | no | EI 240
5511571 | 2 korrus | no | EI 240
5512018 | 2 korrus | no | EI 240
5512406 | 2 korrus | no | EI 240
5524719 | 2 korrus | no | EI 240
5525243 | 2 korrus | no | EI 240
5528823 | 1 korrus | no | EI 240
5538867 | Kelder | no | EI 240
5539161 | Kelder | no | EI 240
5539255 | Kelder | no | EI 240
5594805 | 1 korrus | no | EI 240
5595307 | 2 korrus | no | EI 240
5595311 | 3 korrus | no | EI 240
5597984 | 1 korrus | no | EI 240
5610279 | 3 korrus | no | EI 240
5610483 | 3 korrus | no | EI 240
5645268 | Saali lagi | yes | EI 240
5655550 | 1 korrus | no | EI 240
5658986 | 3 korrus | no | EI 240
5661403 | Kelder | no | EI 240
5662688 | 1 korrus | no | EI 240
5663467 | Kelder | no | EI 240
5681550 | 1 korrus | yes | EI 240
5682325 | 1 korrus | no | EI 240
5684183 | 2 korrus | no | EI 240
5684356 | 2 korrus | no | EI 240
5684357 | 2 korrus | no | EI 240
5685368 | 3 korrus | no
5685659 | 3 korrus | no
5734492 | 1 korrus | no

# IfcWallStandardCase: Basic Wall:16_Betoon 2 (5)
Type - PredefinedType: STANDARD; Material: __Betoonelement 160 mm
Pset_WallCommon - LoadBearing: no; IsExternal: yes; Reference: 16_Betoon 2
ARHITEKTUUR - 05 Asukoht(välis): yes; 06 Kandev: no; 02 Materjal: __Betoonelement
Name (Basic Wall:16_Betoon 2:...) | In | ExtendToStructure
4946257 | 1 korrus | yes
4962571 | 1 korrus | yes
4997248 | 2 korrus | yes
5005316 | 3 korrus | no
5130218 | Kelder | no

# IfcWallStandardCase: Basic Wall:17_Betoon, Basic Wall:17_Betoon:4993510
In: 2 korrus
Material: NCS S 2570-R Syvä punainen, matta, ruisku 1 mm, __Betoonelement 170 mm
Pset_WallCommon - LoadBearing: no; IsExternal: yes; ExtendToStructure: yes; Reference: 17_Betoon
ARHITEKTUUR - 05 Asukoht(välis): yes; 06 Kandev: no; 02 Materjal: __Betoonelement

# IfcWallStandardCase: Basic Wall:18_Betoon 3 (4)
Type - PredefinedType: STANDARD; Material: __Betoonelement 180 mm
Pset_WallCommon - LoadBearing: no; IsExternal: yes; Reference: 18_Betoon 3
ARHITEKTUUR - 05 Asukoht(välis): yes; 06 Kandev: no; 02 Materjal: __Betoonelement
Name (Basic Wall:18_Betoon 3:...) | In | ExtendToStructure
4954980 | Kelder | yes
4993304 | 2 korrus | yes
4997079 | 2 korrus | yes
4999660 | 2 korrus | no

# IfcWallStandardCase: Basic Wall:19_Betoon 2 (3)
Type - PredefinedType: STANDARD; Material: __Betoonelement 190 mm
Pset_WallCommon - LoadBearing: no; IsExternal: yes; Reference: 19_Betoon 2
ARHITEKTUUR - 05 Asukoht(välis): yes; 06 Kandev: no; 02 Materjal: __Betoonelement
Name (Basic Wall:19_Betoon 2:...) | In | ExtendToStructure
4946515 | 1 korrus | yes
4961969 | 1 korrus | yes
5520045 | Kelder | no

# IfcWallStandardCase: Basic Wall:20_Betoon (7)
Type - PredefinedType: STANDARD; Material: __Betoonelement 200 mm
Pset_WallCommon - LoadBearing: no; IsExternal: yes; Reference: 20_Betoon
ARHITEKTUUR - 05 Asukoht(välis): yes; 06 Kandev: no; 02 Materjal: __Betoonelement; 03 Kategooria/Tüüp: VS-22
Name (Basic Wall:20_Betoon:...) | In | ExtendToStructure
4944891 | 1 korrus | yes
4948161 | 1 korrus | yes
4948494 | 1 korrus | yes
5003016 | 3 korrus | no
5661888 | 1 korrus | no
5662024 | 1 korrus | no
5662125 | 1 korrus | no

# IfcWallStandardCase: Basic Wall:21_Betoon 2, Basic Wall:21_Betoon 2:5002767
In: 3 korrus
Type - PredefinedType: STANDARD; Material: __Betoonelement 210 mm
Pset_WallCommon - LoadBearing: no; ExtendToStructure: no; IsExternal: yes; Reference: 21_Betoon 2
ARHITEKTUUR - 05 Asukoht(välis): yes; 06 Kandev: no; 02 Materjal: __Betoonelement

# IfcWallStandardCase: Basic Wall:22_Betoon 3, Basic Wall:22_Betoon 3:4997172
In: 2 korrus
Type - PredefinedType: STANDARD; Material: __Betoonelement 220 mm
Pset_WallCommon - LoadBearing: no; IsExternal: yes; ExtendToStructure: yes; Reference: 22_Betoon 3
ARHITEKTUUR - 05 Asukoht(välis): yes; 06 Kandev: no; 02 Materjal: __Betoonelement

# IfcWallStandardCase: Basic Wall:23_Betoon 3 (2)
In: 2 korrus
Type - PredefinedType: STANDARD; Material: __Betoonelement 230 mm
Pset_WallCommon - LoadBearing: no; ExtendToStructure: no; IsExternal: yes; Reference: 23_Betoon 3
ARHITEKTUUR - 05 Asukoht(välis): yes; 06 Kandev: no; 02 Materjal: __Betoonelement
Name (Basic Wall:23_Betoon 3:...)
5200763
5200853 | ARHITEKTUUR - 04 Tulepüsivus: EI 240

# IfcWallStandardCase: Basic Wall:25_Betoon (2)
In: 3 korrus
Material: __Betoonelement 250 mm
Pset_WallCommon - LoadBearing: no; ExtendToStructure: no; IsExternal: yes; Reference: 25_Betoon
ARHITEKTUUR - 05 Asukoht(välis): yes; 06 Kandev: no; 02 Materjal: __Betoonelement
Name (Basic Wall:25_Betoon:...)
5009826
5343545

# IfcWallStandardCase: Basic Wall:26_Betoon 2 (2)
In: 2 korrus
Type - PredefinedType: STANDARD; Material: __Betoonelement 260 mm
Pset_WallCommon - LoadBearing: no; IsExternal: yes; Reference: 26_Betoon 2
ARHITEKTUUR - 05 Asukoht(välis): yes; 06 Kandev: no; 02 Materjal: __Betoonelement
Name (Basic Wall:26_Betoon 2:...) | ExtendToStructure
4994633 | yes
5651419 | no

# IfcWallStandardCase: Basic Wall:27_Betoon 3, Basic Wall:27_Betoon 3:4979301
In: Kelder
Type - PredefinedType: STANDARD; Material: __Betoonelement 270 mm
Pset_WallCommon - LoadBearing: no; IsExternal: yes; ExtendToStructure: yes; Reference: 27_Betoon 3
ARHITEKTUUR - 05 Asukoht(välis): yes; 06 Kandev: no; 02 Materjal: __Betoonelement

# IfcWallStandardCase: Basic Wall:2_Betoon 2, Basic Wall:2_Betoon 2:5182416
In: Kelder
Type - PredefinedType: STANDARD; Material: __Betoonelement 20 mm
Pset_WallCommon - LoadBearing: no; ExtendToStructure: no; IsExternal: yes; Reference: 2_Betoon 2
ARHITEKTUUR - 05 Asukoht(välis): yes; 06 Kandev: no; 02 Materjal: __Betoonelement

# IfcWallStandardCase: Basic Wall:31_Betoon 2, Basic Wall:31_Betoon 2:4994771
In: 2 korrus
Type - PredefinedType: STANDARD; Material: __Betoonelement 310 mm
Pset_WallCommon - LoadBearing: no; IsExternal: yes; ExtendToStructure: yes; Reference: 31_Betoon 2
ARHITEKTUUR - 05 Asukoht(välis): yes; 06 Kandev: no; 02 Materjal: __Betoonelement

# IfcWallStandardCase: Basic Wall:38_Betoon 2, Basic Wall:38_Betoon 2:4951887
In: Kelder
Type - PredefinedType: STANDARD; Material: __Betoonelement 380 mm
Pset_WallCommon - LoadBearing: no; IsExternal: yes; ExtendToStructure: yes; Reference: 38_Betoon 2
ARHITEKTUUR - 05 Asukoht(välis): yes; 06 Kandev: no; 02 Materjal: __Betoonelement

# IfcWallStandardCase: Basic Wall:39_Betoon 3 (5)
Type - PredefinedType: STANDARD; Material: __Betoonelement 390 mm
Pset_WallCommon - LoadBearing: no; IsExternal: yes; Reference: 39_Betoon 3
ARHITEKTUUR - 05 Asukoht(välis): yes; 06 Kandev: no; 02 Materjal: __Betoonelement
Name (Basic Wall:39_Betoon 3:...) | In | ExtendToStructure
4959166 | 1 korrus | yes
4984559 | Kelder | no
5003379 | 3 korrus | no
5004581 | 3 korrus | no
5005466 | 3 korrus | no

# IfcWallStandardCase: Basic Wall:3_Betoon 3, Basic Wall:3_Betoon 3:5203646
In: 2 korrus
Type - PredefinedType: STANDARD; Material: __Betoonelement 30 mm
Pset_WallCommon - LoadBearing: no; ExtendToStructure: no; IsExternal: yes; Reference: 3_Betoon 3
ARHITEKTUUR - 05 Asukoht(välis): yes; 06 Kandev: no; 02 Materjal: __Betoonelement

# IfcWallStandardCase: Basic Wall:40_Betoon (12)
Type - PredefinedType: STANDARD; Material: __Betoonelement 400 mm
Pset_WallCommon - Reference: 40_Betoon; LoadBearing: no; IsExternal: yes
ARHITEKTUUR - 02 Materjal: __Betoonelement; 05 Asukoht(välis): yes; 06 Kandev: no
Name (Basic Wall:40_Betoon:...) | In | ExtendToStructure
4940457 | 1 korrus | no
4944354 | 1 korrus | yes
4963113 | 1 korrus | yes
4996770 | 2 korrus | yes
4996847 | 2 korrus | yes
4997579 | 2 korrus | yes
4997645 | 2 korrus | yes
4997790 | 2 korrus | yes
4999026 | 2 korrus | yes
5005003 | 3 korrus | no
5184274 | 1 korrus | no
5684184 | 2 korrus | no | ARHITEKTUUR - 04 Tulepüsivus: EI 240

# IfcWallStandardCase: Basic Wall:41_Betoon 2 (5)
Type - PredefinedType: STANDARD; Material: __Betoonelement 410 mm
Pset_WallCommon - LoadBearing: no; IsExternal: yes; Reference: 41_Betoon 2
ARHITEKTUUR - 05 Asukoht(välis): yes; 06 Kandev: no; 02 Materjal: __Betoonelement
Name (Basic Wall:41_Betoon 2:...) | In | ExtendToStructure
4946451 | 1 korrus | yes
4992919 | 2 korrus | yes
4997052 | 2 korrus | yes
5005261 | 3 korrus | no
5379063 | 2 korrus | yes

# IfcWallStandardCase: Basic Wall:42_Betoon, Basic Wall:42_Betoon:4998442
In: 2 korrus
Type - PredefinedType: STANDARD; Material: __Betoonelement 420 mm
Pset_WallCommon - LoadBearing: no; IsExternal: yes; ExtendToStructure: yes; Reference: 42_Betoon
ARHITEKTUUR - 05 Asukoht(välis): yes; 06 Kandev: no; 02 Materjal: __Betoonelement

# IfcWallStandardCase: Basic Wall:43_Betoon 2 (2)
Type - PredefinedType: STANDARD; Material: __Betoonelement 430 mm
Pset_WallCommon - LoadBearing: no; IsExternal: yes; Reference: 43_Betoon 2
ARHITEKTUUR - 05 Asukoht(välis): yes; 06 Kandev: no; 02 Materjal: __Betoonelement
Name (Basic Wall:43_Betoon 2:...) | In | ExtendToStructure
4947281 | 1 korrus | yes
5021849 | 3 korrus | no

# IfcWallStandardCase: Basic Wall:45_Betoon, Basic Wall:45_Betoon:4998357
In: 2 korrus
Type - PredefinedType: STANDARD; Material: __Betoonelement 450 mm
Pset_WallCommon - LoadBearing: no; IsExternal: yes; ExtendToStructure: yes; Reference: 45_Betoon
ARHITEKTUUR - 05 Asukoht(välis): yes; 06 Kandev: no; 02 Materjal: __Betoonelement

# IfcWallStandardCase: Basic Wall:47_Betoon, Basic Wall:47_Betoon:5001110
In: 3 korrus
Type - PredefinedType: STANDARD; Material: __Betoonelement 470 mm
Pset_WallCommon - LoadBearing: no; IsExternal: yes; ExtendToStructure: yes; Reference: 47_Betoon
ARHITEKTUUR - 05 Asukoht(välis): yes; 06 Kandev: no; 02 Materjal: __Betoonelement

# IfcWallStandardCase: Basic Wall:50_Betoon + UUS Soojustus 2 (2)
In: 1 korrus
Type - PredefinedType: STANDARD; Material: Plaster 10 mm, Polystyrene, Expanded 150 mm, __Betoonelement 500 mm
Pset_WallCommon - LoadBearing: no; IsExternal: yes; Reference: 50_Betoon + UUS Soojustus 2; ThermalTransmittance: 0.232271 kg/K/s3
ARHITEKTUUR - 05 Asukoht(välis): yes; 06 Kandev: no; 02 Materjal: __Betoonelement
Name (Basic Wall:50_Betoon + UUS Soojustus 2:...) | ExtendToStructure
5384224 | no
5387401 | yes

# IfcWallStandardCase: Basic Wall:51_Betoon 2 (2)
Type - PredefinedType: STANDARD; Material: __Betoonelement 510 mm
Pset_WallCommon - LoadBearing: no; IsExternal: yes; Reference: 51_Betoon 2
ARHITEKTUUR - 05 Asukoht(välis): yes; 06 Kandev: no; 02 Materjal: __Betoonelement
Name (Basic Wall:51_Betoon 2:...) | In | ExtendToStructure
4984686 | Kelder | yes
5001192 | 3 korrus | no

# IfcWallStandardCase: Basic Wall:52_Betoon 2 (3)
Type - PredefinedType: STANDARD; Material: __Betoonelement 520 mm
Pset_WallCommon - LoadBearing: no; IsExternal: yes; Reference: 52_Betoon 2
ARHITEKTUUR - 05 Asukoht(välis): yes; 06 Kandev: no; 02 Materjal: __Betoonelement
Name (Basic Wall:52_Betoon 2:...) | In | ExtendToStructure
4951993 | Kelder | yes
5005821 | 3 korrus | no
5006746 | Kelder | no

# IfcWallStandardCase: Basic Wall:53_Betoon 3 (2)
Type - PredefinedType: STANDARD; Material: __Betoonelement 530 mm
Pset_WallCommon - LoadBearing: no; IsExternal: yes; ExtendToStructure: yes; Reference: 53_Betoon 3
ARHITEKTUUR - 05 Asukoht(välis): yes; 06 Kandev: no; 02 Materjal: __Betoonelement
Name (Basic Wall:53_Betoon 3:...) | In
4986198 | Kelder
4989004 | 2 korrus

# IfcWallStandardCase: Basic Wall:54_Betoon 2 (4)
Type - PredefinedType: STANDARD; Material: __Betoonelement 540 mm
Pset_WallCommon - LoadBearing: no; IsExternal: yes; Reference: 54_Betoon 2
ARHITEKTUUR - 05 Asukoht(välis): yes; 06 Kandev: no; 02 Materjal: __Betoonelement
Name (Basic Wall:54_Betoon 2:...) | In | ExtendToStructure
4947666 | 1 korrus | yes
4958210 | 1 korrus | yes
4978745 | Kelder | yes
4986084 | Kelder | no

# IfcWallStandardCase: Basic Wall:59_Betoon 2, Basic Wall:59_Betoon 2:4944633
In: 1 korrus
Type - PredefinedType: STANDARD; Material: __Betoonelement 590 mm
Pset_WallCommon - LoadBearing: no; ExtendToStructure: no; IsExternal: yes; Reference: 59_Betoon 2
ARHITEKTUUR - 05 Asukoht(välis): yes; 06 Kandev: no; 02 Materjal: __Betoonelement

# IfcWallStandardCase: Basic Wall:61_Betoon 3, Basic Wall:61_Betoon 3:4952200
In: Kelder
Type - PredefinedType: STANDARD; Material: __Betoonelement 610 mm
Pset_WallCommon - LoadBearing: no; ExtendToStructure: no; IsExternal: yes; Reference: 61_Betoon 3
ARHITEKTUUR - 05 Asukoht(välis): yes; 06 Kandev: no; 02 Materjal: __Betoonelement

# IfcWallStandardCase: Basic Wall:62_Betoon 2, Basic Wall:62_Betoon 2:4952505
In: Kelder
Type - PredefinedType: STANDARD; Material: __Betoonelement 620 mm
Pset_WallCommon - LoadBearing: no; IsExternal: yes; ExtendToStructure: yes; Reference: 62_Betoon 2
ARHITEKTUUR - 05 Asukoht(välis): yes; 06 Kandev: no; 02 Materjal: __Betoonelement

# IfcWallStandardCase: Basic Wall:66_Betoon 2, Basic Wall:66_Betoon 2:5130757
In: Kelder
Type - PredefinedType: STANDARD; Material: __Betoonelement 660 mm
Pset_WallCommon - LoadBearing: no; ExtendToStructure: no; IsExternal: yes; Reference: 66_Betoon 2
ARHITEKTUUR - 05 Asukoht(välis): yes; 06 Kandev: no; 02 Materjal: __Betoonelement

# IfcWallStandardCase: Basic Wall:68_Betoon, Basic Wall:68_Betoon:4983572
In: Kelder
Material: __Betoonelement 680 mm
Pset_WallCommon - LoadBearing: no; ExtendToStructure: no; IsExternal: yes; Reference: 68_Betoon
ARHITEKTUUR - 05 Asukoht(välis): yes; 06 Kandev: no; 02 Materjal: __Betoonelement

# IfcWallStandardCase: Basic Wall:70_Betoon, Basic Wall:70_Betoon:4985075
In: Kelder
Type - PredefinedType: STANDARD; Material: __Betoonelement 700 mm
Pset_WallCommon - LoadBearing: no; IsExternal: yes; ExtendToStructure: yes; Reference: 70_Betoon
ARHITEKTUUR - 05 Asukoht(välis): yes; 06 Kandev: no; 02 Materjal: __Betoonelement

# IfcWallStandardCase: Basic Wall:73_Betoon 3 (2)
In: Kelder
Type - PredefinedType: STANDARD; Material: __Betoonelement 730 mm
Pset_WallCommon - LoadBearing: no; IsExternal: yes; ExtendToStructure: yes; Reference: 73_Betoon 3
ARHITEKTUUR - 05 Asukoht(välis): yes; 06 Kandev: no; 02 Materjal: __Betoonelement
Name (Basic Wall:73_Betoon 3:...)
4986886
5007234

# IfcWallStandardCase: Basic Wall:74_Betoon 2, Basic Wall:74_Betoon 2:5009205
In: 3 korrus
Type - PredefinedType: STANDARD; Material: __Betoonelement 740 mm
Pset_WallCommon - LoadBearing: no; ExtendToStructure: no; IsExternal: yes; Reference: 74_Betoon 2
ARHITEKTUUR - 05 Asukoht(välis): yes; 06 Kandev: no; 02 Materjal: __Betoonelement

# IfcWallStandardCase: Basic Wall:76_Betoon 5 (2)
In: Kelder
Type - PredefinedType: STANDARD; Material: __Betoonelement 760 mm
Pset_WallCommon - LoadBearing: no; IsExternal: yes; ExtendToStructure: yes; Reference: 76_Betoon 5
ARHITEKTUUR - 05 Asukoht(välis): yes; 06 Kandev: no; 02 Materjal: __Betoonelement
Name (Basic Wall:76_Betoon 5:...)
4953573
4953727

# IfcWallStandardCase: Basic Wall:83_Betoon 5 (2)
In: Kelder
Type - PredefinedType: STANDARD; Material: __Betoonelement 830 mm
Pset_WallCommon - LoadBearing: no; IsExternal: yes; ExtendToStructure: yes; Reference: 83_Betoon 5
ARHITEKTUUR - 05 Asukoht(välis): yes; 06 Kandev: no; 02 Materjal: __Betoonelement
Name (Basic Wall:83_Betoon 5:...)
4953770
4984205

# IfcWallStandardCase: Basic Wall:86_Betoon 3, Basic Wall:86_Betoon 3:4953474
In: Kelder
Type - PredefinedType: STANDARD; Material: __Betoonelement 860 mm
Pset_WallCommon - LoadBearing: no; IsExternal: yes; ExtendToStructure: yes; Reference: 86_Betoon 3
ARHITEKTUUR - 05 Asukoht(välis): yes; 06 Kandev: no; 02 Materjal: __Betoonelement

# IfcWallStandardCase: Basic Wall:8_Betoon 2 (4)
Type - PredefinedType: STANDARD; Material: NCS S 2570-R Syvä punainen, matta, ruisku 1 mm, __Betoonelement 90 mm
Pset_WallCommon - LoadBearing: no; ExtendToStructure: no; IsExternal: yes; Reference: 8_Betoon 2
ARHITEKTUUR - 05 Asukoht(välis): yes; 06 Kandev: no; 02 Materjal: __Betoonelement
Name (Basic Wall:8_Betoon 2:...) | In
5683381 | Kelder
5683569 | Kelder
5690261 | 2 korrus
5691250 | 2 korrus

# IfcWallStandardCase: Basic Wall:92_Betoon 4, Basic Wall:92_Betoon 4:4986729
In: Kelder
Type - PredefinedType: STANDARD; Material: __Betoonelement 920 mm
Pset_WallCommon - LoadBearing: no; IsExternal: yes; ExtendToStructure: yes; Reference: 92_Betoon 4
ARHITEKTUUR - 05 Asukoht(välis): yes; 06 Kandev: no; 02 Materjal: __Betoonelement

# IfcWallStandardCase: Basic Wall:9_Betoon 2 (2)
Type - PredefinedType: STANDARD; Material: __Betoonelement 90 mm
Pset_WallCommon - LoadBearing: no; IsExternal: yes; ExtendToStructure: yes; Reference: 9_Betoon 2
ARHITEKTUUR - 05 Asukoht(välis): yes; 06 Kandev: no; 02 Materjal: __Betoonelement
Name (Basic Wall:9_Betoon 2:...) | In
4961410 | 1 korrus
4985170 | Kelder

# IfcWallStandardCase: Basic Wall:Kips plaat_tagasein (2)
In: 1 korrus
Type - PredefinedType: STANDARD; Material: EST. Ehitusplaat. Kipsplaat 12.5 mm
Pset_WallCommon - LoadBearing: no; ExtendToStructure: no; IsExternal: no; Reference: Kips plaat_tagasein
ARHITEKTUUR - 06 Kandev: no; 05 Asukoht(välis): no; 01 Nimetus: Sisesein; 07 Helipidavus: -; 08 Soojusläbivus: -
Name (Basic Wall:Kips plaat_tagasein:...)
5770384
5770740

# IfcWallStandardCase: Basic Wall:Kipssirm 1 kordne (43)
Type - PredefinedType: STANDARD; Material: Metal - Stud Layer 30 mm, Gypsum Wall Board 13 mm
Pset_WallCommon - LoadBearing: no; ExtendToStructure: no; IsExternal: yes; Reference: Kipssirm 1 kordne; ThermalTransmittance: 50 kg/K/s3
ARHITEKTUUR - 05 Asukoht(välis): yes; 06 Kandev: no; 02 Materjal: Metal - Stud Layer
Name (Basic Wall:Kipssirm 1 kordne:...) | In
5561395 | 1 korrus
5562356 | 1 korrus
5562606 | 1 korrus
5562818 | 1 korrus
5562941 | 1 korrus
5564277 | 1 korrus
5564466 | 1 korrus
5564578 | 1 korrus
5564717 | 1 korrus
5564818 | 1 korrus
5564962 | 1 korrus
5565072 | 1 korrus
5565348 | 1 korrus
5565613 | 1 korrus
5566106 | 2 korrus
5566261 | 2 korrus
5566374 | 2 korrus
5566503 | 2 korrus
5566616 | 2 korrus
5566789 | 2 korrus
5566917 | 2 korrus
5567122 | 2 korrus
5567314 | 2 korrus
5567548 | 2 korrus
5567691 | 2 korrus
5567779 | 2 korrus
5568403 | 3 korrus
5568555 | 3 korrus
5568690 | 3 korrus
5568810 | 3 korrus
5568936 | 3 korrus
5569317 | 3 korrus
5569456 | 3 korrus
5569619 | 3 korrus
5569821 | 3 korrus
5569925 | 3 korrus
5570037 | 3 korrus
5570122 | 3 korrus
5672659 | 1 korrus
5674263 | 2 korrus
5674430 | 3 korrus
5675845 | 3 korrus
5676880 | 2 korrus

# IfcWallStandardCase: Basic Wall:Olemasolev Soojustatud Välissein (6)
Type - PredefinedType: STANDARD; Material: Plaster 10 mm, Polystyrene 150 mm, __Betoonelement 500 mm
Classification: VS-1 (Uniformat)
Pset_WallCommon - ExtendToStructure: no; IsExternal: yes; Reference: Olemasolev Soojustatud Välissein; FireRating: EI 240; ThermalTransmittance: 0.527814 kg/K/s3
ARHITEKTUUR - 05 Asukoht(välis): yes; 01 Nimetus: Välissein; 02 Materjal: __Betoonelement; 07 Helipidavus: 49 dB; 08 Soojusläbivus: 0.17 W/m2K
Name (Basic Wall:Olemasolev Soojustatud Välissein:...) | In | LoadBearing = 06 Kandev
5376043 | 1 korrus | no
5380696 | 1 korrus | yes
5381178 | 1 korrus | no
5383293 | 1 korrus | no
5388117 | 2 korrus | no
5388423 | 2 korrus | no

# IfcWallStandardCase: Basic Wall:Uus Välissein + Soojustus (2)
In: 1 korrus
Type - PredefinedType: STANDARD; Material: Plaster 10 mm, EST. Soojustus. Kivivill. Default 200 mm, EST. Müüritis. Väikeplokk. Kergkruusplokk 450 mm, Plaster 10 mm
Pset_WallCommon - LoadBearing: no; IsExternal: yes; Reference: Uus Välissein + Soojustus; ThermalTransmittance: 25.5 kg/K/s3
ARHITEKTUUR - 05 Asukoht(välis): yes; 06 Kandev: no; 02 Materjal: EST. Müüritis. Väikeplokk. Kergkruusplokk; 07 Helipidavus: 49 dB; 08 Soojusläbivus: 0.15 W/m2K
Name (Basic Wall:Uus Välissein + Soojustus:...) | ExtendToStructure
5441409 | yes
5441566 | no

# IfcWallStandardCase: Basic Wall:Välissein Betoon190 + Soojustus 200 (2)
In: Kelder
Type - PredefinedType: STANDARD; Material: NCS S 2570-R Syvä punainen, matta, ruisku 1 mm, Plaster 10 mm, EST. Soojustus. Kivivill. Default 200 mm, EST. Müüritis. Väikeplokk. Betoon-õõnesplokk 190 mm
Pset_WallCommon - LoadBearing: no; ExtendToStructure: no; IsExternal: yes; Reference: Välissein Betoon190 + Soojustus 200; FireRating: -; ThermalTransmittance: 51 kg/K/s3
ARHITEKTUUR - 05 Asukoht(välis): yes; 06 Kandev: no; 01 Nimetus: Välissein; 02 Materjal: EST. Müüritis. Väikeplokk. Betoon-õõnesplokk; 03 Kategooria/Tüüp: VS-3; 07 Helipidavus: 51 dB; 08 Soojusläbivus: 0.15 W/m2K
Name (Basic Wall:Välissein Betoon190 + Soojustus 200:...)
5514085
5514292

# IfcWallStandardCase: Basic Wall:WC_tagasein_ metallkarkassein 100(12.5+75) (8)
Type - PredefinedType: STANDARD; Material: EST. Ehitusplaat. Kipsplaat 12.5 mm, EST. Metall. Teras. Tsingitud 75 mm
Pset_WallCommon - LoadBearing: no; ExtendToStructure: no; IsExternal: no; Reference: WC_tagasein_ metallkarkassein 100(12.5+75)
ARHITEKTUUR - 06 Kandev: no; 05 Asukoht(välis): no; 01 Nimetus: Sisesein; 03 Kategooria/Tüüp: SS-6; 07 Helipidavus: -; 08 Soojusläbivus: -
Name (Basic Wall:WC_tagasein_ metallkarkassein 100(12.5+75):...) | In
5722727 | 1 korrus
5723724 | 1 korrus
5724173 | 1 korrus
5724402 | 1 korrus
5724743 | 2 korrus
5725144 | 2 korrus
5725445 | 3 korrus
5725655 | 3 korrus

# IfcWindow: A-1 UUS 2050 x 1730mm Avatav (5)
Type - ParameterTakesPrecedence: no; Sizeable: no; Material: PVC, Glass
OverallHeight: 1730 mm; OverallWidth: 2050 mm
Pset_WindowCommon - IsExternal: yes; Reference: A-1 UUS 2050 x 1730mm Avatav
ARHITEKTUUR(AVATÄITED) - 02 Materjal: Plastikaken; 03 Kategooria/Tüüp: Saksa tüüpi aken; 06 Soojusläbivus: Kogu akna U≤1,2 W/m²K; 07 Helipidavus: 35dB; 08 Veepidavus: 7A; 09 Õhuläbilaskvus: klass 4; 11 Vastupanu tuulekoormusele: C5/B5; 12 Klaaspakett: Kolmekordne klaaspakett, täidetud argooniga; 14 Päikesekiirgustegur: 0,3; 15 Käelisus: Sissepoole, vt. joonist; 16 Liigendatus: 2 ruuduga; 18 Viimistlus: RAL 9003 (Valge)
Name (sma_W2:A-1 UUS 2050 x 1730mm Avatav:...) | In
5383687 | 2 korrus
5383691 | 3 korrus
5388931 | 2 korrus
5516155 | 3 korrus
5516291 | 3 korrus

# IfcWindow: A-1* 2050 x 1730mm Avatav (46)
Type - ConstructionType: OTHER_CONSTRUCTION; ParameterTakesPrecedence: no; Sizeable: no; Material: PVC, Glass
OverallHeight: 1730 mm; OverallWidth: 2050 mm
Pset_WindowCommon - IsExternal: yes; Reference: A-1* 2050 x 1730mm Avatav
ARHITEKTUUR(AVATÄITED) - 01 Nimetus: Välisaken; 02 Materjal: Plastikaken; 03 Kategooria/Tüüp: Saksa tüüpi aken; 06 Soojusläbivus: Kogu akna U≤1,2 W/m²K; 07 Helipidavus: 35dB; 08 Veepidavus: 7A; 09 Õhuläbilaskvus: klass 4; 11 Vastupanu tuulekoormusele: C5/B5; 12 Klaaspakett: Kolmekordne klaaspakett, täidetud argooniga; 14 Päikesekiirgustegur: 0,3; 15 Käelisus: Sissepoole, vt. joonist; 16 Liigendatus: 2 ruuduga; 18 Viimistlus: RAL 9003 (Valge)
Name (sma_W2:A-1* 2050 x 1730mm Avatav:...) | In
5376354 | 1 korrus
5376976 | 1 korrus
5377496 | 1 korrus
5377605 | 1 korrus
5377736 | 1 korrus
5377839 | 1 korrus
5378010 | 1 korrus
5378157 | 1 korrus
5379609 | 2 korrus
5379610 | 2 korrus
5379611 | 2 korrus
5379612 | 2 korrus
5379613 | 2 korrus
5379614 | 2 korrus
5379615 | 2 korrus
5379619 | 3 korrus
5379620 | 3 korrus
5379621 | 3 korrus
5379622 | 3 korrus
5379623 | 3 korrus
5379624 | 3 korrus
5379625 | 3 korrus
5379659 | 2 korrus
5379691 | 3 korrus
5381426 | 1 korrus
5381567 | 1 korrus
5381680 | 1 korrus
5381827 | 1 korrus
5381942 | 1 korrus
5382079 | 1 korrus
5382204 | 1 korrus
5382349 | 2 korrus
5382350 | 2 korrus
5382351 | 2 korrus
5382352 | 2 korrus
5382353 | 2 korrus
5382354 | 2 korrus
5382355 | 2 korrus
5382359 | 3 korrus
5382360 | 3 korrus
5382361 | 3 korrus
5382362 | 3 korrus
5382363 | 3 korrus
5382364 | 3 korrus
5382365 | 3 korrus
5383425 | 1 korrus

# IfcWindow: A-2 2050 x 1430mm Avatav (2)
In: 1 korrus
Type - ConstructionType: OTHER_CONSTRUCTION; ParameterTakesPrecedence: no; Sizeable: no; Material: PVC, Glass
OverallHeight: 1600 mm; OverallWidth: 2050 mm
Pset_WindowCommon - IsExternal: yes; Reference: A-2 2050 x 1430mm Avatav
ARHITEKTUUR(AVATÄITED) - 01 Nimetus: Välisaken; 02 Materjal: Plastikaken; 03 Kategooria/Tüüp: Saksa tüüpi aken; 06 Soojusläbivus: Kogu akna U≤1,2 W/m²K; 07 Helipidavus: 35dB; 08 Veepidavus: 7A; 09 Õhuläbilaskvus: klass 4; 11 Vastupanu tuulekoormusele: C5/B5; 12 Klaaspakett: Vähemalt kahekordne klaaspakett, sisemine klaas selektiivklaas; 14 Päikesekiirgustegur: 0,3; 15 Käelisus: Sissepoole, vt. joonist; 16 Liigendatus: 2 ruuduga; 18 Viimistlus: RAL 9003 (Valge)
Name (sma_W2:A-2 2050 x 1430mm Avatav:...)
5441705
5443804

# IfcWindow: A-3 3490 x 1700mm Avatav, sma_W5:A-3 3490 x 1700mm Avatav:5516959
In: 2 korrus
Type - ConstructionType: OTHER_CONSTRUCTION; ParameterTakesPrecedence: no; Sizeable: no; Material: Glass, Default, PVC, Flexible
OverallHeight: 1700 mm; OverallWidth: 3490 mm
Pset_WindowCommon - IsExternal: yes; Reference: A-3 3490 x 1700mm Avatav
ARHITEKTUUR(AVATÄITED) - 02 Materjal: Plastikaken; 03 Kategooria/Tüüp: Saksa tüüpi aken; 06 Soojusläbivus: Kogu akna U≤1,2 W/m²K; 07 Helipidavus: 35 dB; 08 Veepidavus: 7A; 09 Õhuläbilaskvus: klass 4; 11 Vastupanu tuulekoormusele: C5/B5; 12 Klaaspakett: kolmekordne klaaspakett, täidetud argooniga; 14 Päikesekiirgustegur: 0,3; 15 Käelisus: Sissepoole, vt. joonist; 16 Liigendatus: 3 ruuduga; 18 Viimistlus: RAL 9003 (Valge)

# IfcWindow: A-4 2470 x 1200mm Avatav (2)
In: 2 korrus
Type - ConstructionType: OTHER_CONSTRUCTION; ParameterTakesPrecedence: no; Sizeable: no; Material: Glass, Default, PVC, Flexible
OverallHeight: 1700 mm; OverallWidth: 2730 mm
Pset_WindowCommon - IsExternal: yes; Reference: A-4 2470 x 1200mm Avatav
ARHITEKTUUR(AVATÄITED) - 02 Materjal: Plastikaken; 03 Kategooria/Tüüp: Saksa tüüpi aken; 06 Soojusläbivus: Kogu akna U≤1,2 W/m²K; 07 Helipidavus: 35 dB; 08 Veepidavus: 7A; 09 Õhuläbilaskvus: klass 4; 11 Vastupanu tuulekoormusele: C5/B5; 12 Klaaspakett: kolmekordne klaaspakett, täidetud argooniga; 14 Päikesekiirgustegur: 0,3; 15 Käelisus: Sissepoole, vt. joonist; 16 Liigendatus: 3 ruuduga; 18 Viimistlus: RAL 9003 (Valge)
Name (sma_W5:A-4 2470 x 1200mm Avatav:...)
5516456
5517125

# IfcWindow: A-6 2590 x 1700mm Mitteavatav (3)
In: 1 korrus
Type - ConstructionType: OTHER_CONSTRUCTION; ParameterTakesPrecedence: no; Sizeable: no; Material: Glass, PVC
OverallHeight: 1860 mm; OverallWidth: 2590 mm
Pset_WindowCommon - IsExternal: yes; Reference: A-6 2590 x 1700mm Mitteavatav
ARHITEKTUUR(AVATÄITED) - 01 Nimetus: Välisaken; 02 Materjal: Plastikaken; 03 Kategooria/Tüüp: Klaasfassaad; 06 Soojusläbivus: Kogu akna U≤1,2 W/m²K; 07 Helipidavus: 35 dB; 08 Veepidavus: 7A; 09 Õhuläbilaskvus: klass 4; 11 Vastupanu tuulekoormusele: C5/B5; 12 Klaaspakett: kolmekordne klaaspakett, täidetud argooniga; 14 Päikesekiirgustegur: 0,3; 15 Käelisus: mitteavanev (vt. joonist); 16 Liigendatus: 3 ruuduga; 18 Viimistlus: RAL7047 (Helehall)
Name (sma_W5:A-6 2590 x 1700mm Mitteavatav:...)
5443895
5444136
5444269

# IfcWindow: Family7, Family7:Family7:5032530
In: 1 korrus
Type - ParameterTakesPrecedence: no; Sizeable: no; Material: Glass
OverallHeight: 8060 mm; OverallWidth: 2750 mm
Pset_WindowCommon - IsExternal: yes; Reference: Family7

# IfcWindow: Family8 (2)
In: Kelder
Type - ParameterTakesPrecedence: no; Sizeable: no; Material: Glass
OverallHeight: 2200 mm; OverallWidth: 790 mm
Pset_WindowCommon - IsExternal: yes; Reference: Family8
Name (Family8:Family8:...)
5048661
5049596

# IfcWindow: Kupu 1000 x 1000, Orivent 01:Kupu 1000 x 1000:5718317
In: Katus 2
Type - ParameterTakesPrecedence: no; Sizeable: no; Material: PC_kirkas, RR 20
OverallHeight: 1067.33 mm; OverallWidth: 1275.75 mm
Pset_WindowCommon - IsExternal: yes; Reference: Kupu 1000 x 1000; FireRating: B 300
Pset_ManufacturerTypeInformation - Manufacturer: Kera Group Oy
ARHITEKTUUR(AVATÄITED) - 01 Nimetus: Savunpoistoluukku, puurunko - 3-kert.kupu; 19 Mudel/Toote nimetus: Orivent 01; 20 Tootja: Kera Group Oy

# IfcWindow: VR-03 LAI REST, VR-03:VR-03 LAI REST:5613851
In: Saali lagi
Type - ParameterTakesPrecedence: no; Sizeable: no; Material: __Aken/Uks_hall
OverallHeight: 1000 mm; OverallWidth: 1500 mm
Pset_WindowCommon - IsExternal: yes; Reference: VR-03 LAI REST
ARHITEKTUUR(AVATÄITED) - 02 Materjal: Terasraam; 03 Kategooria/Tüüp: Vent. rest; 06 Soojusläbivus: -; 07 Helipidavus: vastavalt normile; 12 Klaaspakett: -; 15 Käelisus: mitteavanev (vt. joonist); 18 Viimistlus: Tumehall RAL7043
